VERSION 5.8 ;
BUSBITCHARS "[]" ;
DIVIDERCHAR "/" ;
UNITS
    DATABASE MICRONS 1000 ;
END UNITS

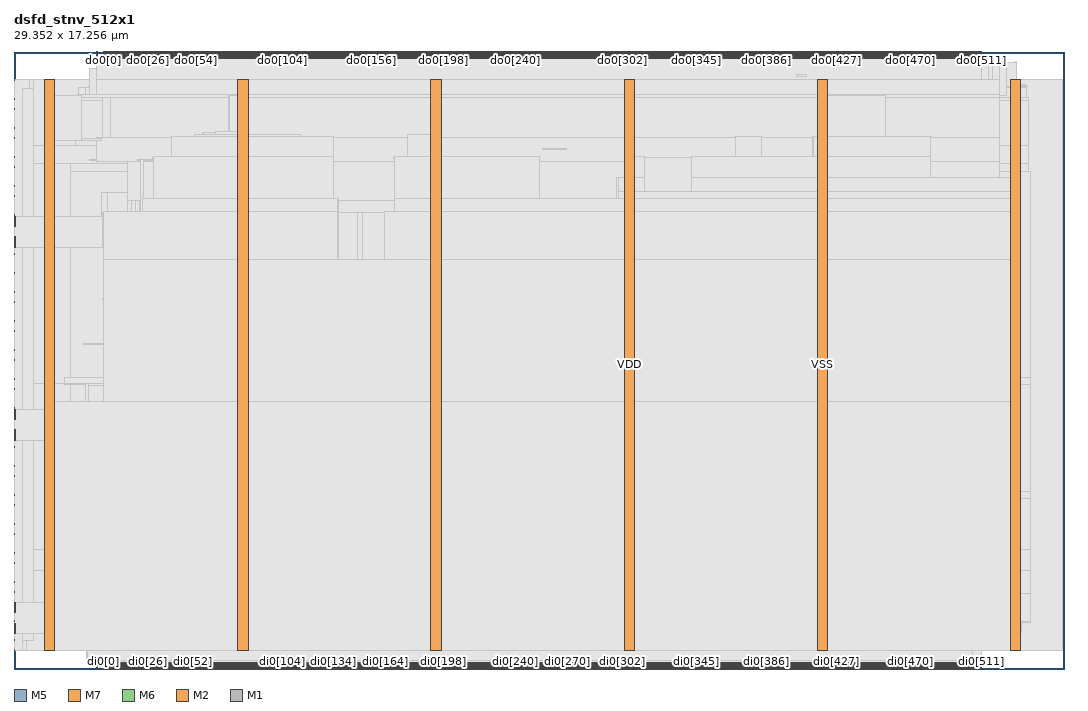
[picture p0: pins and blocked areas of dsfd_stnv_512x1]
MACRO dsfd_stnv_512x1
  FOREIGN dsfd_stnv_512x1 0 0 ;
  CLASS BLOCK ;
  SIZE 29.352 BY 17.256 ;
  PIN di0[0]
    DIRECTION INPUT ;
    USE SIGNAL ;
    PORT
      LAYER M5 ;
        RECT  2.496 0 2.52 0.192 ;
    END
  END di0[0]
  PIN di0[100]
    DIRECTION INPUT ;
    USE SIGNAL ;
    PORT
      LAYER M5 ;
        RECT  7.296 0 7.32 0.192 ;
    END
  END di0[100]
  PIN di0[101]
    DIRECTION INPUT ;
    USE SIGNAL ;
    PORT
      LAYER M5 ;
        RECT  7.344 0 7.368 0.192 ;
    END
  END di0[101]
  PIN di0[102]
    DIRECTION INPUT ;
    USE SIGNAL ;
    PORT
      LAYER M5 ;
        RECT  7.392 0 7.416 0.192 ;
    END
  END di0[102]
  PIN di0[103]
    DIRECTION INPUT ;
    USE SIGNAL ;
    PORT
      LAYER M5 ;
        RECT  7.44 0 7.464 0.192 ;
    END
  END di0[103]
  PIN di0[104]
    DIRECTION INPUT ;
    USE SIGNAL ;
    PORT
      LAYER M5 ;
        RECT  7.488 0 7.512 0.192 ;
    END
  END di0[104]
  PIN di0[105]
    DIRECTION INPUT ;
    USE SIGNAL ;
    PORT
      LAYER M5 ;
        RECT  7.536 0 7.56 0.192 ;
    END
  END di0[105]
  PIN di0[106]
    DIRECTION INPUT ;
    USE SIGNAL ;
    PORT
      LAYER M5 ;
        RECT  7.584 0 7.608 0.192 ;
    END
  END di0[106]
  PIN di0[107]
    DIRECTION INPUT ;
    USE SIGNAL ;
    PORT
      LAYER M5 ;
        RECT  7.632 0 7.656 0.192 ;
    END
  END di0[107]
  PIN di0[108]
    DIRECTION INPUT ;
    USE SIGNAL ;
    PORT
      LAYER M5 ;
        RECT  7.68 0 7.704 0.192 ;
    END
  END di0[108]
  PIN di0[109]
    DIRECTION INPUT ;
    USE SIGNAL ;
    PORT
      LAYER M5 ;
        RECT  7.728 0 7.752 0.192 ;
    END
  END di0[109]
  PIN di0[10]
    DIRECTION INPUT ;
    USE SIGNAL ;
    PORT
      LAYER M5 ;
        RECT  2.976 0 3 0.192 ;
    END
  END di0[10]
  PIN di0[110]
    DIRECTION INPUT ;
    USE SIGNAL ;
    PORT
      LAYER M5 ;
        RECT  7.776 0 7.8 0.192 ;
    END
  END di0[110]
  PIN di0[111]
    DIRECTION INPUT ;
    USE SIGNAL ;
    PORT
      LAYER M5 ;
        RECT  7.824 0 7.848 0.192 ;
    END
  END di0[111]
  PIN di0[112]
    DIRECTION INPUT ;
    USE SIGNAL ;
    PORT
      LAYER M5 ;
        RECT  7.872 0 7.896 0.192 ;
    END
  END di0[112]
  PIN di0[113]
    DIRECTION INPUT ;
    USE SIGNAL ;
    PORT
      LAYER M5 ;
        RECT  7.92 0 7.944 0.192 ;
    END
  END di0[113]
  PIN di0[114]
    DIRECTION INPUT ;
    USE SIGNAL ;
    PORT
      LAYER M5 ;
        RECT  7.968 0 7.992 0.192 ;
    END
  END di0[114]
  PIN di0[115]
    DIRECTION INPUT ;
    USE SIGNAL ;
    PORT
      LAYER M5 ;
        RECT  8.016 0 8.04 0.192 ;
    END
  END di0[115]
  PIN di0[116]
    DIRECTION INPUT ;
    USE SIGNAL ;
    PORT
      LAYER M5 ;
        RECT  8.064 0 8.088 0.192 ;
    END
  END di0[116]
  PIN di0[117]
    DIRECTION INPUT ;
    USE SIGNAL ;
    PORT
      LAYER M5 ;
        RECT  8.112 0 8.136 0.192 ;
    END
  END di0[117]
  PIN di0[118]
    DIRECTION INPUT ;
    USE SIGNAL ;
    PORT
      LAYER M5 ;
        RECT  8.16 0 8.184 0.192 ;
    END
  END di0[118]
  PIN di0[119]
    DIRECTION INPUT ;
    USE SIGNAL ;
    PORT
      LAYER M5 ;
        RECT  8.208 0 8.232 0.192 ;
    END
  END di0[119]
  PIN di0[11]
    DIRECTION INPUT ;
    USE SIGNAL ;
    PORT
      LAYER M5 ;
        RECT  3.024 0 3.048 0.192 ;
    END
  END di0[11]
  PIN di0[120]
    DIRECTION INPUT ;
    USE SIGNAL ;
    PORT
      LAYER M5 ;
        RECT  8.256 0 8.28 0.192 ;
    END
  END di0[120]
  PIN di0[121]
    DIRECTION INPUT ;
    USE SIGNAL ;
    PORT
      LAYER M5 ;
        RECT  8.304 0 8.328 0.192 ;
    END
  END di0[121]
  PIN di0[122]
    DIRECTION INPUT ;
    USE SIGNAL ;
    PORT
      LAYER M5 ;
        RECT  8.352 0 8.376 0.192 ;
    END
  END di0[122]
  PIN di0[123]
    DIRECTION INPUT ;
    USE SIGNAL ;
    PORT
      LAYER M5 ;
        RECT  8.4 0 8.424 0.192 ;
    END
  END di0[123]
  PIN di0[124]
    DIRECTION INPUT ;
    USE SIGNAL ;
    PORT
      LAYER M5 ;
        RECT  8.448 0 8.472 0.192 ;
    END
  END di0[124]
  PIN di0[125]
    DIRECTION INPUT ;
    USE SIGNAL ;
    PORT
      LAYER M5 ;
        RECT  8.496 0 8.52 0.192 ;
    END
  END di0[125]
  PIN di0[126]
    DIRECTION INPUT ;
    USE SIGNAL ;
    PORT
      LAYER M5 ;
        RECT  8.544 0 8.568 0.192 ;
    END
  END di0[126]
  PIN di0[127]
    DIRECTION INPUT ;
    USE SIGNAL ;
    PORT
      LAYER M5 ;
        RECT  8.592 0 8.616 0.192 ;
    END
  END di0[127]
  PIN di0[128]
    DIRECTION INPUT ;
    USE SIGNAL ;
    PORT
      LAYER M5 ;
        RECT  8.64 0 8.664 0.192 ;
    END
  END di0[128]
  PIN di0[129]
    DIRECTION INPUT ;
    USE SIGNAL ;
    PORT
      LAYER M5 ;
        RECT  8.688 0 8.712 0.192 ;
    END
  END di0[129]
  PIN di0[12]
    DIRECTION INPUT ;
    USE SIGNAL ;
    PORT
      LAYER M5 ;
        RECT  3.072 0 3.096 0.192 ;
    END
  END di0[12]
  PIN di0[130]
    DIRECTION INPUT ;
    USE SIGNAL ;
    PORT
      LAYER M5 ;
        RECT  8.736 0 8.76 0.192 ;
    END
  END di0[130]
  PIN di0[131]
    DIRECTION INPUT ;
    USE SIGNAL ;
    PORT
      LAYER M5 ;
        RECT  8.784 0 8.808 0.192 ;
    END
  END di0[131]
  PIN di0[132]
    DIRECTION INPUT ;
    USE SIGNAL ;
    PORT
      LAYER M5 ;
        RECT  8.832 0 8.856 0.192 ;
    END
  END di0[132]
  PIN di0[133]
    DIRECTION INPUT ;
    USE SIGNAL ;
    PORT
      LAYER M5 ;
        RECT  8.88 0 8.904 0.192 ;
    END
  END di0[133]
  PIN di0[134]
    DIRECTION INPUT ;
    USE SIGNAL ;
    PORT
      LAYER M5 ;
        RECT  8.928 0 8.952 0.192 ;
    END
  END di0[134]
  PIN di0[135]
    DIRECTION INPUT ;
    USE SIGNAL ;
    PORT
      LAYER M5 ;
        RECT  8.976 0 9 0.192 ;
    END
  END di0[135]
  PIN di0[136]
    DIRECTION INPUT ;
    USE SIGNAL ;
    PORT
      LAYER M5 ;
        RECT  9.024 0 9.048 0.192 ;
    END
  END di0[136]
  PIN di0[137]
    DIRECTION INPUT ;
    USE SIGNAL ;
    PORT
      LAYER M5 ;
        RECT  9.072 0 9.096 0.192 ;
    END
  END di0[137]
  PIN di0[138]
    DIRECTION INPUT ;
    USE SIGNAL ;
    PORT
      LAYER M5 ;
        RECT  9.12 0 9.144 0.192 ;
    END
  END di0[138]
  PIN di0[139]
    DIRECTION INPUT ;
    USE SIGNAL ;
    PORT
      LAYER M5 ;
        RECT  9.168 0 9.192 0.192 ;
    END
  END di0[139]
  PIN di0[13]
    DIRECTION INPUT ;
    USE SIGNAL ;
    PORT
      LAYER M5 ;
        RECT  3.12 0 3.144 0.192 ;
    END
  END di0[13]
  PIN di0[140]
    DIRECTION INPUT ;
    USE SIGNAL ;
    PORT
      LAYER M5 ;
        RECT  9.216 0 9.24 0.192 ;
    END
  END di0[140]
  PIN di0[141]
    DIRECTION INPUT ;
    USE SIGNAL ;
    PORT
      LAYER M5 ;
        RECT  9.264 0 9.288 0.192 ;
    END
  END di0[141]
  PIN di0[142]
    DIRECTION INPUT ;
    USE SIGNAL ;
    PORT
      LAYER M5 ;
        RECT  9.312 0 9.336 0.192 ;
    END
  END di0[142]
  PIN di0[143]
    DIRECTION INPUT ;
    USE SIGNAL ;
    PORT
      LAYER M5 ;
        RECT  9.36 0 9.384 0.192 ;
    END
  END di0[143]
  PIN di0[144]
    DIRECTION INPUT ;
    USE SIGNAL ;
    PORT
      LAYER M5 ;
        RECT  9.408 0 9.432 0.192 ;
    END
  END di0[144]
  PIN di0[145]
    DIRECTION INPUT ;
    USE SIGNAL ;
    PORT
      LAYER M5 ;
        RECT  9.456 0 9.48 0.192 ;
    END
  END di0[145]
  PIN di0[146]
    DIRECTION INPUT ;
    USE SIGNAL ;
    PORT
      LAYER M5 ;
        RECT  9.504 0 9.528 0.192 ;
    END
  END di0[146]
  PIN di0[147]
    DIRECTION INPUT ;
    USE SIGNAL ;
    PORT
      LAYER M5 ;
        RECT  9.552 0 9.576 0.192 ;
    END
  END di0[147]
  PIN di0[148]
    DIRECTION INPUT ;
    USE SIGNAL ;
    PORT
      LAYER M5 ;
        RECT  9.6 0 9.624 0.192 ;
    END
  END di0[148]
  PIN di0[149]
    DIRECTION INPUT ;
    USE SIGNAL ;
    PORT
      LAYER M5 ;
        RECT  9.648 0 9.672 0.192 ;
    END
  END di0[149]
  PIN di0[14]
    DIRECTION INPUT ;
    USE SIGNAL ;
    PORT
      LAYER M5 ;
        RECT  3.168 0 3.192 0.192 ;
    END
  END di0[14]
  PIN di0[150]
    DIRECTION INPUT ;
    USE SIGNAL ;
    PORT
      LAYER M5 ;
        RECT  9.696 0 9.72 0.192 ;
    END
  END di0[150]
  PIN di0[151]
    DIRECTION INPUT ;
    USE SIGNAL ;
    PORT
      LAYER M5 ;
        RECT  9.744 0 9.768 0.192 ;
    END
  END di0[151]
  PIN di0[152]
    DIRECTION INPUT ;
    USE SIGNAL ;
    PORT
      LAYER M5 ;
        RECT  9.792 0 9.816 0.192 ;
    END
  END di0[152]
  PIN di0[153]
    DIRECTION INPUT ;
    USE SIGNAL ;
    PORT
      LAYER M5 ;
        RECT  9.84 0 9.864 0.192 ;
    END
  END di0[153]
  PIN di0[154]
    DIRECTION INPUT ;
    USE SIGNAL ;
    PORT
      LAYER M5 ;
        RECT  9.888 0 9.912 0.192 ;
    END
  END di0[154]
  PIN di0[155]
    DIRECTION INPUT ;
    USE SIGNAL ;
    PORT
      LAYER M5 ;
        RECT  9.936 0 9.96 0.192 ;
    END
  END di0[155]
  PIN di0[156]
    DIRECTION INPUT ;
    USE SIGNAL ;
    PORT
      LAYER M5 ;
        RECT  9.984 0 10.008 0.192 ;
    END
  END di0[156]
  PIN di0[157]
    DIRECTION INPUT ;
    USE SIGNAL ;
    PORT
      LAYER M5 ;
        RECT  10.032 0 10.056 0.192 ;
    END
  END di0[157]
  PIN di0[158]
    DIRECTION INPUT ;
    USE SIGNAL ;
    PORT
      LAYER M5 ;
        RECT  10.08 0 10.104 0.192 ;
    END
  END di0[158]
  PIN di0[159]
    DIRECTION INPUT ;
    USE SIGNAL ;
    PORT
      LAYER M5 ;
        RECT  10.128 0 10.152 0.192 ;
    END
  END di0[159]
  PIN di0[15]
    DIRECTION INPUT ;
    USE SIGNAL ;
    PORT
      LAYER M5 ;
        RECT  3.216 0 3.24 0.192 ;
    END
  END di0[15]
  PIN di0[160]
    DIRECTION INPUT ;
    USE SIGNAL ;
    PORT
      LAYER M5 ;
        RECT  10.176 0 10.2 0.192 ;
    END
  END di0[160]
  PIN di0[161]
    DIRECTION INPUT ;
    USE SIGNAL ;
    PORT
      LAYER M5 ;
        RECT  10.224 0 10.248 0.192 ;
    END
  END di0[161]
  PIN di0[162]
    DIRECTION INPUT ;
    USE SIGNAL ;
    PORT
      LAYER M5 ;
        RECT  10.272 0 10.296 0.192 ;
    END
  END di0[162]
  PIN di0[163]
    DIRECTION INPUT ;
    USE SIGNAL ;
    PORT
      LAYER M5 ;
        RECT  10.32 0 10.344 0.192 ;
    END
  END di0[163]
  PIN di0[164]
    DIRECTION INPUT ;
    USE SIGNAL ;
    PORT
      LAYER M5 ;
        RECT  10.368 0 10.392 0.192 ;
    END
  END di0[164]
  PIN di0[165]
    DIRECTION INPUT ;
    USE SIGNAL ;
    PORT
      LAYER M5 ;
        RECT  10.416 0 10.44 0.192 ;
    END
  END di0[165]
  PIN di0[166]
    DIRECTION INPUT ;
    USE SIGNAL ;
    PORT
      LAYER M5 ;
        RECT  10.464 0 10.488 0.192 ;
    END
  END di0[166]
  PIN di0[167]
    DIRECTION INPUT ;
    USE SIGNAL ;
    PORT
      LAYER M5 ;
        RECT  10.512 0 10.536 0.192 ;
    END
  END di0[167]
  PIN di0[168]
    DIRECTION INPUT ;
    USE SIGNAL ;
    PORT
      LAYER M5 ;
        RECT  10.56 0 10.584 0.192 ;
    END
  END di0[168]
  PIN di0[169]
    DIRECTION INPUT ;
    USE SIGNAL ;
    PORT
      LAYER M5 ;
        RECT  10.608 0 10.632 0.192 ;
    END
  END di0[169]
  PIN di0[16]
    DIRECTION INPUT ;
    USE SIGNAL ;
    PORT
      LAYER M5 ;
        RECT  3.264 0 3.288 0.192 ;
    END
  END di0[16]
  PIN di0[170]
    DIRECTION INPUT ;
    USE SIGNAL ;
    PORT
      LAYER M5 ;
        RECT  10.656 0 10.68 0.192 ;
    END
  END di0[170]
  PIN di0[171]
    DIRECTION INPUT ;
    USE SIGNAL ;
    PORT
      LAYER M5 ;
        RECT  10.704 0 10.728 0.192 ;
    END
  END di0[171]
  PIN di0[172]
    DIRECTION INPUT ;
    USE SIGNAL ;
    PORT
      LAYER M5 ;
        RECT  10.752 0 10.776 0.192 ;
    END
  END di0[172]
  PIN di0[173]
    DIRECTION INPUT ;
    USE SIGNAL ;
    PORT
      LAYER M5 ;
        RECT  10.8 0 10.824 0.192 ;
    END
  END di0[173]
  PIN di0[174]
    DIRECTION INPUT ;
    USE SIGNAL ;
    PORT
      LAYER M5 ;
        RECT  10.848 0 10.872 0.192 ;
    END
  END di0[174]
  PIN di0[175]
    DIRECTION INPUT ;
    USE SIGNAL ;
    PORT
      LAYER M5 ;
        RECT  10.896 0 10.92 0.192 ;
    END
  END di0[175]
  PIN di0[176]
    DIRECTION INPUT ;
    USE SIGNAL ;
    PORT
      LAYER M5 ;
        RECT  10.944 0 10.968 0.192 ;
    END
  END di0[176]
  PIN di0[177]
    DIRECTION INPUT ;
    USE SIGNAL ;
    PORT
      LAYER M5 ;
        RECT  10.992 0 11.016 0.192 ;
    END
  END di0[177]
  PIN di0[178]
    DIRECTION INPUT ;
    USE SIGNAL ;
    PORT
      LAYER M5 ;
        RECT  11.04 0 11.064 0.192 ;
    END
  END di0[178]
  PIN di0[179]
    DIRECTION INPUT ;
    USE SIGNAL ;
    PORT
      LAYER M5 ;
        RECT  11.088 0 11.112 0.192 ;
    END
  END di0[179]
  PIN di0[17]
    DIRECTION INPUT ;
    USE SIGNAL ;
    PORT
      LAYER M5 ;
        RECT  3.312 0 3.336 0.192 ;
    END
  END di0[17]
  PIN di0[180]
    DIRECTION INPUT ;
    USE SIGNAL ;
    PORT
      LAYER M5 ;
        RECT  11.136 0 11.16 0.192 ;
    END
  END di0[180]
  PIN di0[181]
    DIRECTION INPUT ;
    USE SIGNAL ;
    PORT
      LAYER M5 ;
        RECT  11.184 0 11.208 0.192 ;
    END
  END di0[181]
  PIN di0[182]
    DIRECTION INPUT ;
    USE SIGNAL ;
    PORT
      LAYER M5 ;
        RECT  11.232 0 11.256 0.192 ;
    END
  END di0[182]
  PIN di0[183]
    DIRECTION INPUT ;
    USE SIGNAL ;
    PORT
      LAYER M5 ;
        RECT  11.28 0 11.304 0.192 ;
    END
  END di0[183]
  PIN di0[184]
    DIRECTION INPUT ;
    USE SIGNAL ;
    PORT
      LAYER M5 ;
        RECT  11.328 0 11.352 0.192 ;
    END
  END di0[184]
  PIN di0[185]
    DIRECTION INPUT ;
    USE SIGNAL ;
    PORT
      LAYER M5 ;
        RECT  11.376 0 11.4 0.192 ;
    END
  END di0[185]
  PIN di0[186]
    DIRECTION INPUT ;
    USE SIGNAL ;
    PORT
      LAYER M5 ;
        RECT  11.424 0 11.448 0.192 ;
    END
  END di0[186]
  PIN di0[187]
    DIRECTION INPUT ;
    USE SIGNAL ;
    PORT
      LAYER M5 ;
        RECT  11.472 0 11.496 0.192 ;
    END
  END di0[187]
  PIN di0[188]
    DIRECTION INPUT ;
    USE SIGNAL ;
    PORT
      LAYER M5 ;
        RECT  11.52 0 11.544 0.192 ;
    END
  END di0[188]
  PIN di0[189]
    DIRECTION INPUT ;
    USE SIGNAL ;
    PORT
      LAYER M5 ;
        RECT  11.568 0 11.592 0.192 ;
    END
  END di0[189]
  PIN di0[18]
    DIRECTION INPUT ;
    USE SIGNAL ;
    PORT
      LAYER M5 ;
        RECT  3.36 0 3.384 0.192 ;
    END
  END di0[18]
  PIN di0[190]
    DIRECTION INPUT ;
    USE SIGNAL ;
    PORT
      LAYER M5 ;
        RECT  11.616 0 11.64 0.192 ;
    END
  END di0[190]
  PIN di0[191]
    DIRECTION INPUT ;
    USE SIGNAL ;
    PORT
      LAYER M5 ;
        RECT  11.664 0 11.688 0.192 ;
    END
  END di0[191]
  PIN di0[192]
    DIRECTION INPUT ;
    USE SIGNAL ;
    PORT
      LAYER M5 ;
        RECT  11.712 0 11.736 0.192 ;
    END
  END di0[192]
  PIN di0[193]
    DIRECTION INPUT ;
    USE SIGNAL ;
    PORT
      LAYER M5 ;
        RECT  11.76 0 11.784 0.192 ;
    END
  END di0[193]
  PIN di0[194]
    DIRECTION INPUT ;
    USE SIGNAL ;
    PORT
      LAYER M5 ;
        RECT  11.808 0 11.832 0.192 ;
    END
  END di0[194]
  PIN di0[195]
    DIRECTION INPUT ;
    USE SIGNAL ;
    PORT
      LAYER M5 ;
        RECT  11.856 0 11.88 0.192 ;
    END
  END di0[195]
  PIN di0[196]
    DIRECTION INPUT ;
    USE SIGNAL ;
    PORT
      LAYER M5 ;
        RECT  11.904 0 11.928 0.192 ;
    END
  END di0[196]
  PIN di0[197]
    DIRECTION INPUT ;
    USE SIGNAL ;
    PORT
      LAYER M5 ;
        RECT  11.952 0 11.976 0.192 ;
    END
  END di0[197]
  PIN di0[198]
    DIRECTION INPUT ;
    USE SIGNAL ;
    PORT
      LAYER M5 ;
        RECT  12 0 12.024 0.192 ;
    END
  END di0[198]
  PIN di0[199]
    DIRECTION INPUT ;
    USE SIGNAL ;
    PORT
      LAYER M5 ;
        RECT  12.048 0 12.072 0.192 ;
    END
  END di0[199]
  PIN di0[19]
    DIRECTION INPUT ;
    USE SIGNAL ;
    PORT
      LAYER M5 ;
        RECT  3.408 0 3.432 0.192 ;
    END
  END di0[19]
  PIN di0[1]
    DIRECTION INPUT ;
    USE SIGNAL ;
    PORT
      LAYER M5 ;
        RECT  2.544 0 2.568 0.192 ;
    END
  END di0[1]
  PIN di0[200]
    DIRECTION INPUT ;
    USE SIGNAL ;
    PORT
      LAYER M5 ;
        RECT  12.096 0 12.12 0.192 ;
    END
  END di0[200]
  PIN di0[201]
    DIRECTION INPUT ;
    USE SIGNAL ;
    PORT
      LAYER M5 ;
        RECT  12.144 0 12.168 0.192 ;
    END
  END di0[201]
  PIN di0[202]
    DIRECTION INPUT ;
    USE SIGNAL ;
    PORT
      LAYER M5 ;
        RECT  12.192 0 12.216 0.192 ;
    END
  END di0[202]
  PIN di0[203]
    DIRECTION INPUT ;
    USE SIGNAL ;
    PORT
      LAYER M5 ;
        RECT  12.24 0 12.264 0.192 ;
    END
  END di0[203]
  PIN di0[204]
    DIRECTION INPUT ;
    USE SIGNAL ;
    PORT
      LAYER M5 ;
        RECT  12.288 0 12.312 0.192 ;
    END
  END di0[204]
  PIN di0[205]
    DIRECTION INPUT ;
    USE SIGNAL ;
    PORT
      LAYER M5 ;
        RECT  12.336 0 12.36 0.192 ;
    END
  END di0[205]
  PIN di0[206]
    DIRECTION INPUT ;
    USE SIGNAL ;
    PORT
      LAYER M5 ;
        RECT  12.384 0 12.408 0.192 ;
    END
  END di0[206]
  PIN di0[207]
    DIRECTION INPUT ;
    USE SIGNAL ;
    PORT
      LAYER M5 ;
        RECT  12.432 0 12.456 0.192 ;
    END
  END di0[207]
  PIN di0[208]
    DIRECTION INPUT ;
    USE SIGNAL ;
    PORT
      LAYER M5 ;
        RECT  12.48 0 12.504 0.192 ;
    END
  END di0[208]
  PIN di0[209]
    DIRECTION INPUT ;
    USE SIGNAL ;
    PORT
      LAYER M5 ;
        RECT  12.528 0 12.552 0.192 ;
    END
  END di0[209]
  PIN di0[20]
    DIRECTION INPUT ;
    USE SIGNAL ;
    PORT
      LAYER M5 ;
        RECT  3.456 0 3.48 0.192 ;
    END
  END di0[20]
  PIN di0[210]
    DIRECTION INPUT ;
    USE SIGNAL ;
    PORT
      LAYER M5 ;
        RECT  12.576 0 12.6 0.192 ;
    END
  END di0[210]
  PIN di0[211]
    DIRECTION INPUT ;
    USE SIGNAL ;
    PORT
      LAYER M5 ;
        RECT  12.624 0 12.648 0.192 ;
    END
  END di0[211]
  PIN di0[212]
    DIRECTION INPUT ;
    USE SIGNAL ;
    PORT
      LAYER M5 ;
        RECT  12.672 0 12.696 0.192 ;
    END
  END di0[212]
  PIN di0[213]
    DIRECTION INPUT ;
    USE SIGNAL ;
    PORT
      LAYER M5 ;
        RECT  12.72 0 12.744 0.192 ;
    END
  END di0[213]
  PIN di0[214]
    DIRECTION INPUT ;
    USE SIGNAL ;
    PORT
      LAYER M5 ;
        RECT  12.768 0 12.792 0.192 ;
    END
  END di0[214]
  PIN di0[215]
    DIRECTION INPUT ;
    USE SIGNAL ;
    PORT
      LAYER M5 ;
        RECT  12.816 0 12.84 0.192 ;
    END
  END di0[215]
  PIN di0[216]
    DIRECTION INPUT ;
    USE SIGNAL ;
    PORT
      LAYER M5 ;
        RECT  12.864 0 12.888 0.192 ;
    END
  END di0[216]
  PIN di0[217]
    DIRECTION INPUT ;
    USE SIGNAL ;
    PORT
      LAYER M5 ;
        RECT  12.912 0 12.936 0.192 ;
    END
  END di0[217]
  PIN di0[218]
    DIRECTION INPUT ;
    USE SIGNAL ;
    PORT
      LAYER M5 ;
        RECT  12.96 0 12.984 0.192 ;
    END
  END di0[218]
  PIN di0[219]
    DIRECTION INPUT ;
    USE SIGNAL ;
    PORT
      LAYER M5 ;
        RECT  13.008 0 13.032 0.192 ;
    END
  END di0[219]
  PIN di0[21]
    DIRECTION INPUT ;
    USE SIGNAL ;
    PORT
      LAYER M5 ;
        RECT  3.504 0 3.528 0.192 ;
    END
  END di0[21]
  PIN di0[220]
    DIRECTION INPUT ;
    USE SIGNAL ;
    PORT
      LAYER M5 ;
        RECT  13.056 0 13.08 0.192 ;
    END
  END di0[220]
  PIN di0[221]
    DIRECTION INPUT ;
    USE SIGNAL ;
    PORT
      LAYER M5 ;
        RECT  13.104 0 13.128 0.192 ;
    END
  END di0[221]
  PIN di0[222]
    DIRECTION INPUT ;
    USE SIGNAL ;
    PORT
      LAYER M5 ;
        RECT  13.152 0 13.176 0.192 ;
    END
  END di0[222]
  PIN di0[223]
    DIRECTION INPUT ;
    USE SIGNAL ;
    PORT
      LAYER M5 ;
        RECT  13.2 0 13.224 0.192 ;
    END
  END di0[223]
  PIN di0[224]
    DIRECTION INPUT ;
    USE SIGNAL ;
    PORT
      LAYER M5 ;
        RECT  13.248 0 13.272 0.192 ;
    END
  END di0[224]
  PIN di0[225]
    DIRECTION INPUT ;
    USE SIGNAL ;
    PORT
      LAYER M5 ;
        RECT  13.296 0 13.32 0.192 ;
    END
  END di0[225]
  PIN di0[226]
    DIRECTION INPUT ;
    USE SIGNAL ;
    PORT
      LAYER M5 ;
        RECT  13.344 0 13.368 0.192 ;
    END
  END di0[226]
  PIN di0[227]
    DIRECTION INPUT ;
    USE SIGNAL ;
    PORT
      LAYER M5 ;
        RECT  13.392 0 13.416 0.192 ;
    END
  END di0[227]
  PIN di0[228]
    DIRECTION INPUT ;
    USE SIGNAL ;
    PORT
      LAYER M5 ;
        RECT  13.44 0 13.464 0.192 ;
    END
  END di0[228]
  PIN di0[229]
    DIRECTION INPUT ;
    USE SIGNAL ;
    PORT
      LAYER M5 ;
        RECT  13.488 0 13.512 0.192 ;
    END
  END di0[229]
  PIN di0[22]
    DIRECTION INPUT ;
    USE SIGNAL ;
    PORT
      LAYER M5 ;
        RECT  3.552 0 3.576 0.192 ;
    END
  END di0[22]
  PIN di0[230]
    DIRECTION INPUT ;
    USE SIGNAL ;
    PORT
      LAYER M5 ;
        RECT  13.536 0 13.56 0.192 ;
    END
  END di0[230]
  PIN di0[231]
    DIRECTION INPUT ;
    USE SIGNAL ;
    PORT
      LAYER M5 ;
        RECT  13.584 0 13.608 0.192 ;
    END
  END di0[231]
  PIN di0[232]
    DIRECTION INPUT ;
    USE SIGNAL ;
    PORT
      LAYER M5 ;
        RECT  13.632 0 13.656 0.192 ;
    END
  END di0[232]
  PIN di0[233]
    DIRECTION INPUT ;
    USE SIGNAL ;
    PORT
      LAYER M5 ;
        RECT  13.68 0 13.704 0.192 ;
    END
  END di0[233]
  PIN di0[234]
    DIRECTION INPUT ;
    USE SIGNAL ;
    PORT
      LAYER M5 ;
        RECT  13.728 0 13.752 0.192 ;
    END
  END di0[234]
  PIN di0[235]
    DIRECTION INPUT ;
    USE SIGNAL ;
    PORT
      LAYER M5 ;
        RECT  13.776 0 13.8 0.192 ;
    END
  END di0[235]
  PIN di0[236]
    DIRECTION INPUT ;
    USE SIGNAL ;
    PORT
      LAYER M5 ;
        RECT  13.824 0 13.848 0.192 ;
    END
  END di0[236]
  PIN di0[237]
    DIRECTION INPUT ;
    USE SIGNAL ;
    PORT
      LAYER M5 ;
        RECT  13.872 0 13.896 0.192 ;
    END
  END di0[237]
  PIN di0[238]
    DIRECTION INPUT ;
    USE SIGNAL ;
    PORT
      LAYER M5 ;
        RECT  13.92 0 13.944 0.192 ;
    END
  END di0[238]
  PIN di0[239]
    DIRECTION INPUT ;
    USE SIGNAL ;
    PORT
      LAYER M5 ;
        RECT  13.968 0 13.992 0.192 ;
    END
  END di0[239]
  PIN di0[23]
    DIRECTION INPUT ;
    USE SIGNAL ;
    PORT
      LAYER M5 ;
        RECT  3.6 0 3.624 0.192 ;
    END
  END di0[23]
  PIN di0[240]
    DIRECTION INPUT ;
    USE SIGNAL ;
    PORT
      LAYER M5 ;
        RECT  14.016 0 14.04 0.192 ;
    END
  END di0[240]
  PIN di0[241]
    DIRECTION INPUT ;
    USE SIGNAL ;
    PORT
      LAYER M5 ;
        RECT  14.064 0 14.088 0.192 ;
    END
  END di0[241]
  PIN di0[242]
    DIRECTION INPUT ;
    USE SIGNAL ;
    PORT
      LAYER M5 ;
        RECT  14.112 0 14.136 0.192 ;
    END
  END di0[242]
  PIN di0[243]
    DIRECTION INPUT ;
    USE SIGNAL ;
    PORT
      LAYER M5 ;
        RECT  14.16 0 14.184 0.192 ;
    END
  END di0[243]
  PIN di0[244]
    DIRECTION INPUT ;
    USE SIGNAL ;
    PORT
      LAYER M5 ;
        RECT  14.208 0 14.232 0.192 ;
    END
  END di0[244]
  PIN di0[245]
    DIRECTION INPUT ;
    USE SIGNAL ;
    PORT
      LAYER M5 ;
        RECT  14.256 0 14.28 0.192 ;
    END
  END di0[245]
  PIN di0[246]
    DIRECTION INPUT ;
    USE SIGNAL ;
    PORT
      LAYER M5 ;
        RECT  14.304 0 14.328 0.192 ;
    END
  END di0[246]
  PIN di0[247]
    DIRECTION INPUT ;
    USE SIGNAL ;
    PORT
      LAYER M5 ;
        RECT  14.352 0 14.376 0.192 ;
    END
  END di0[247]
  PIN di0[248]
    DIRECTION INPUT ;
    USE SIGNAL ;
    PORT
      LAYER M5 ;
        RECT  14.4 0 14.424 0.192 ;
    END
  END di0[248]
  PIN di0[249]
    DIRECTION INPUT ;
    USE SIGNAL ;
    PORT
      LAYER M5 ;
        RECT  14.448 0 14.472 0.192 ;
    END
  END di0[249]
  PIN di0[24]
    DIRECTION INPUT ;
    USE SIGNAL ;
    PORT
      LAYER M5 ;
        RECT  3.648 0 3.672 0.192 ;
    END
  END di0[24]
  PIN di0[250]
    DIRECTION INPUT ;
    USE SIGNAL ;
    PORT
      LAYER M5 ;
        RECT  14.496 0 14.52 0.192 ;
    END
  END di0[250]
  PIN di0[251]
    DIRECTION INPUT ;
    USE SIGNAL ;
    PORT
      LAYER M5 ;
        RECT  14.544 0 14.568 0.192 ;
    END
  END di0[251]
  PIN di0[252]
    DIRECTION INPUT ;
    USE SIGNAL ;
    PORT
      LAYER M5 ;
        RECT  14.592 0 14.616 0.192 ;
    END
  END di0[252]
  PIN di0[253]
    DIRECTION INPUT ;
    USE SIGNAL ;
    PORT
      LAYER M5 ;
        RECT  14.64 0 14.664 0.192 ;
    END
  END di0[253]
  PIN di0[254]
    DIRECTION INPUT ;
    USE SIGNAL ;
    PORT
      LAYER M5 ;
        RECT  14.688 0 14.712 0.192 ;
    END
  END di0[254]
  PIN di0[255]
    DIRECTION INPUT ;
    USE SIGNAL ;
    PORT
      LAYER M5 ;
        RECT  14.736 0 14.76 0.192 ;
    END
  END di0[255]
  PIN di0[256]
    DIRECTION INPUT ;
    USE SIGNAL ;
    PORT
      LAYER M5 ;
        RECT  14.784 0 14.808 0.192 ;
    END
  END di0[256]
  PIN di0[257]
    DIRECTION INPUT ;
    USE SIGNAL ;
    PORT
      LAYER M5 ;
        RECT  14.832 0 14.856 0.192 ;
    END
  END di0[257]
  PIN di0[258]
    DIRECTION INPUT ;
    USE SIGNAL ;
    PORT
      LAYER M5 ;
        RECT  14.88 0 14.904 0.192 ;
    END
  END di0[258]
  PIN di0[259]
    DIRECTION INPUT ;
    USE SIGNAL ;
    PORT
      LAYER M5 ;
        RECT  14.928 0 14.952 0.192 ;
    END
  END di0[259]
  PIN di0[25]
    DIRECTION INPUT ;
    USE SIGNAL ;
    PORT
      LAYER M5 ;
        RECT  3.696 0 3.72 0.192 ;
    END
  END di0[25]
  PIN di0[260]
    DIRECTION INPUT ;
    USE SIGNAL ;
    PORT
      LAYER M5 ;
        RECT  14.976 0 15 0.192 ;
    END
  END di0[260]
  PIN di0[261]
    DIRECTION INPUT ;
    USE SIGNAL ;
    PORT
      LAYER M5 ;
        RECT  15.024 0 15.048 0.192 ;
    END
  END di0[261]
  PIN di0[262]
    DIRECTION INPUT ;
    USE SIGNAL ;
    PORT
      LAYER M5 ;
        RECT  15.072 0 15.096 0.192 ;
    END
  END di0[262]
  PIN di0[263]
    DIRECTION INPUT ;
    USE SIGNAL ;
    PORT
      LAYER M5 ;
        RECT  15.12 0 15.144 0.192 ;
    END
  END di0[263]
  PIN di0[264]
    DIRECTION INPUT ;
    USE SIGNAL ;
    PORT
      LAYER M5 ;
        RECT  15.168 0 15.192 0.192 ;
    END
  END di0[264]
  PIN di0[265]
    DIRECTION INPUT ;
    USE SIGNAL ;
    PORT
      LAYER M5 ;
        RECT  15.216 0 15.24 0.192 ;
    END
  END di0[265]
  PIN di0[266]
    DIRECTION INPUT ;
    USE SIGNAL ;
    PORT
      LAYER M5 ;
        RECT  15.264 0 15.288 0.192 ;
    END
  END di0[266]
  PIN di0[267]
    DIRECTION INPUT ;
    USE SIGNAL ;
    PORT
      LAYER M5 ;
        RECT  15.312 0 15.336 0.192 ;
    END
  END di0[267]
  PIN di0[268]
    DIRECTION INPUT ;
    USE SIGNAL ;
    PORT
      LAYER M5 ;
        RECT  15.36 0 15.384 0.192 ;
    END
  END di0[268]
  PIN di0[269]
    DIRECTION INPUT ;
    USE SIGNAL ;
    PORT
      LAYER M5 ;
        RECT  15.408 0 15.432 0.192 ;
    END
  END di0[269]
  PIN di0[26]
    DIRECTION INPUT ;
    USE SIGNAL ;
    PORT
      LAYER M5 ;
        RECT  3.744 0 3.768 0.192 ;
    END
  END di0[26]
  PIN di0[270]
    DIRECTION INPUT ;
    USE SIGNAL ;
    PORT
      LAYER M5 ;
        RECT  15.456 0 15.48 0.192 ;
    END
  END di0[270]
  PIN di0[271]
    DIRECTION INPUT ;
    USE SIGNAL ;
    PORT
      LAYER M5 ;
        RECT  15.504 0 15.528 0.192 ;
    END
  END di0[271]
  PIN di0[272]
    DIRECTION INPUT ;
    USE SIGNAL ;
    PORT
      LAYER M5 ;
        RECT  15.552 0 15.576 0.192 ;
    END
  END di0[272]
  PIN di0[273]
    DIRECTION INPUT ;
    USE SIGNAL ;
    PORT
      LAYER M5 ;
        RECT  15.6 0 15.624 0.192 ;
    END
  END di0[273]
  PIN di0[274]
    DIRECTION INPUT ;
    USE SIGNAL ;
    PORT
      LAYER M5 ;
        RECT  15.648 0 15.672 0.192 ;
    END
  END di0[274]
  PIN di0[275]
    DIRECTION INPUT ;
    USE SIGNAL ;
    PORT
      LAYER M5 ;
        RECT  15.696 0 15.72 0.192 ;
    END
  END di0[275]
  PIN di0[276]
    DIRECTION INPUT ;
    USE SIGNAL ;
    PORT
      LAYER M5 ;
        RECT  15.744 0 15.768 0.192 ;
    END
  END di0[276]
  PIN di0[277]
    DIRECTION INPUT ;
    USE SIGNAL ;
    PORT
      LAYER M5 ;
        RECT  15.792 0 15.816 0.192 ;
    END
  END di0[277]
  PIN di0[278]
    DIRECTION INPUT ;
    USE SIGNAL ;
    PORT
      LAYER M5 ;
        RECT  15.84 0 15.864 0.192 ;
    END
  END di0[278]
  PIN di0[279]
    DIRECTION INPUT ;
    USE SIGNAL ;
    PORT
      LAYER M5 ;
        RECT  15.888 0 15.912 0.192 ;
    END
  END di0[279]
  PIN di0[27]
    DIRECTION INPUT ;
    USE SIGNAL ;
    PORT
      LAYER M5 ;
        RECT  3.792 0 3.816 0.192 ;
    END
  END di0[27]
  PIN di0[280]
    DIRECTION INPUT ;
    USE SIGNAL ;
    PORT
      LAYER M5 ;
        RECT  15.936 0 15.96 0.192 ;
    END
  END di0[280]
  PIN di0[281]
    DIRECTION INPUT ;
    USE SIGNAL ;
    PORT
      LAYER M5 ;
        RECT  15.984 0 16.008 0.192 ;
    END
  END di0[281]
  PIN di0[282]
    DIRECTION INPUT ;
    USE SIGNAL ;
    PORT
      LAYER M5 ;
        RECT  16.032 0 16.056 0.192 ;
    END
  END di0[282]
  PIN di0[283]
    DIRECTION INPUT ;
    USE SIGNAL ;
    PORT
      LAYER M5 ;
        RECT  16.08 0 16.104 0.192 ;
    END
  END di0[283]
  PIN di0[284]
    DIRECTION INPUT ;
    USE SIGNAL ;
    PORT
      LAYER M5 ;
        RECT  16.128 0 16.152 0.192 ;
    END
  END di0[284]
  PIN di0[285]
    DIRECTION INPUT ;
    USE SIGNAL ;
    PORT
      LAYER M5 ;
        RECT  16.176 0 16.2 0.192 ;
    END
  END di0[285]
  PIN di0[286]
    DIRECTION INPUT ;
    USE SIGNAL ;
    PORT
      LAYER M5 ;
        RECT  16.224 0 16.248 0.192 ;
    END
  END di0[286]
  PIN di0[287]
    DIRECTION INPUT ;
    USE SIGNAL ;
    PORT
      LAYER M5 ;
        RECT  16.272 0 16.296 0.192 ;
    END
  END di0[287]
  PIN di0[288]
    DIRECTION INPUT ;
    USE SIGNAL ;
    PORT
      LAYER M5 ;
        RECT  16.32 0 16.344 0.192 ;
    END
  END di0[288]
  PIN di0[289]
    DIRECTION INPUT ;
    USE SIGNAL ;
    PORT
      LAYER M5 ;
        RECT  16.368 0 16.392 0.192 ;
    END
  END di0[289]
  PIN di0[28]
    DIRECTION INPUT ;
    USE SIGNAL ;
    PORT
      LAYER M5 ;
        RECT  3.84 0 3.864 0.192 ;
    END
  END di0[28]
  PIN di0[290]
    DIRECTION INPUT ;
    USE SIGNAL ;
    PORT
      LAYER M5 ;
        RECT  16.416 0 16.44 0.192 ;
    END
  END di0[290]
  PIN di0[291]
    DIRECTION INPUT ;
    USE SIGNAL ;
    PORT
      LAYER M5 ;
        RECT  16.464 0 16.488 0.192 ;
    END
  END di0[291]
  PIN di0[292]
    DIRECTION INPUT ;
    USE SIGNAL ;
    PORT
      LAYER M5 ;
        RECT  16.512 0 16.536 0.192 ;
    END
  END di0[292]
  PIN di0[293]
    DIRECTION INPUT ;
    USE SIGNAL ;
    PORT
      LAYER M5 ;
        RECT  16.56 0 16.584 0.192 ;
    END
  END di0[293]
  PIN di0[294]
    DIRECTION INPUT ;
    USE SIGNAL ;
    PORT
      LAYER M5 ;
        RECT  16.608 0 16.632 0.192 ;
    END
  END di0[294]
  PIN di0[295]
    DIRECTION INPUT ;
    USE SIGNAL ;
    PORT
      LAYER M5 ;
        RECT  16.656 0 16.68 0.192 ;
    END
  END di0[295]
  PIN di0[296]
    DIRECTION INPUT ;
    USE SIGNAL ;
    PORT
      LAYER M5 ;
        RECT  16.704 0 16.728 0.192 ;
    END
  END di0[296]
  PIN di0[297]
    DIRECTION INPUT ;
    USE SIGNAL ;
    PORT
      LAYER M5 ;
        RECT  16.752 0 16.776 0.192 ;
    END
  END di0[297]
  PIN di0[298]
    DIRECTION INPUT ;
    USE SIGNAL ;
    PORT
      LAYER M5 ;
        RECT  16.8 0 16.824 0.192 ;
    END
  END di0[298]
  PIN di0[299]
    DIRECTION INPUT ;
    USE SIGNAL ;
    PORT
      LAYER M5 ;
        RECT  16.848 0 16.872 0.192 ;
    END
  END di0[299]
  PIN di0[29]
    DIRECTION INPUT ;
    USE SIGNAL ;
    PORT
      LAYER M5 ;
        RECT  3.888 0 3.912 0.192 ;
    END
  END di0[29]
  PIN di0[2]
    DIRECTION INPUT ;
    USE SIGNAL ;
    PORT
      LAYER M5 ;
        RECT  2.592 0 2.616 0.192 ;
    END
  END di0[2]
  PIN di0[300]
    DIRECTION INPUT ;
    USE SIGNAL ;
    PORT
      LAYER M5 ;
        RECT  16.896 0 16.92 0.192 ;
    END
  END di0[300]
  PIN di0[301]
    DIRECTION INPUT ;
    USE SIGNAL ;
    PORT
      LAYER M5 ;
        RECT  16.944 0 16.968 0.192 ;
    END
  END di0[301]
  PIN di0[302]
    DIRECTION INPUT ;
    USE SIGNAL ;
    PORT
      LAYER M5 ;
        RECT  16.992 0 17.016 0.192 ;
    END
  END di0[302]
  PIN di0[303]
    DIRECTION INPUT ;
    USE SIGNAL ;
    PORT
      LAYER M5 ;
        RECT  17.04 0 17.064 0.192 ;
    END
  END di0[303]
  PIN di0[304]
    DIRECTION INPUT ;
    USE SIGNAL ;
    PORT
      LAYER M5 ;
        RECT  17.088 0 17.112 0.192 ;
    END
  END di0[304]
  PIN di0[305]
    DIRECTION INPUT ;
    USE SIGNAL ;
    PORT
      LAYER M5 ;
        RECT  17.136 0 17.16 0.192 ;
    END
  END di0[305]
  PIN di0[306]
    DIRECTION INPUT ;
    USE SIGNAL ;
    PORT
      LAYER M5 ;
        RECT  17.184 0 17.208 0.192 ;
    END
  END di0[306]
  PIN di0[307]
    DIRECTION INPUT ;
    USE SIGNAL ;
    PORT
      LAYER M5 ;
        RECT  17.232 0 17.256 0.192 ;
    END
  END di0[307]
  PIN di0[308]
    DIRECTION INPUT ;
    USE SIGNAL ;
    PORT
      LAYER M5 ;
        RECT  17.28 0 17.304 0.192 ;
    END
  END di0[308]
  PIN di0[309]
    DIRECTION INPUT ;
    USE SIGNAL ;
    PORT
      LAYER M5 ;
        RECT  17.328 0 17.352 0.192 ;
    END
  END di0[309]
  PIN di0[30]
    DIRECTION INPUT ;
    USE SIGNAL ;
    PORT
      LAYER M5 ;
        RECT  3.936 0 3.96 0.192 ;
    END
  END di0[30]
  PIN di0[310]
    DIRECTION INPUT ;
    USE SIGNAL ;
    PORT
      LAYER M5 ;
        RECT  17.376 0 17.4 0.192 ;
    END
  END di0[310]
  PIN di0[311]
    DIRECTION INPUT ;
    USE SIGNAL ;
    PORT
      LAYER M5 ;
        RECT  17.424 0 17.448 0.192 ;
    END
  END di0[311]
  PIN di0[312]
    DIRECTION INPUT ;
    USE SIGNAL ;
    PORT
      LAYER M5 ;
        RECT  17.472 0 17.496 0.192 ;
    END
  END di0[312]
  PIN di0[313]
    DIRECTION INPUT ;
    USE SIGNAL ;
    PORT
      LAYER M5 ;
        RECT  17.52 0 17.544 0.192 ;
    END
  END di0[313]
  PIN di0[314]
    DIRECTION INPUT ;
    USE SIGNAL ;
    PORT
      LAYER M5 ;
        RECT  17.568 0 17.592 0.192 ;
    END
  END di0[314]
  PIN di0[315]
    DIRECTION INPUT ;
    USE SIGNAL ;
    PORT
      LAYER M5 ;
        RECT  17.616 0 17.64 0.192 ;
    END
  END di0[315]
  PIN di0[316]
    DIRECTION INPUT ;
    USE SIGNAL ;
    PORT
      LAYER M5 ;
        RECT  17.664 0 17.688 0.192 ;
    END
  END di0[316]
  PIN di0[317]
    DIRECTION INPUT ;
    USE SIGNAL ;
    PORT
      LAYER M5 ;
        RECT  17.712 0 17.736 0.192 ;
    END
  END di0[317]
  PIN di0[318]
    DIRECTION INPUT ;
    USE SIGNAL ;
    PORT
      LAYER M5 ;
        RECT  17.76 0 17.784 0.192 ;
    END
  END di0[318]
  PIN di0[319]
    DIRECTION INPUT ;
    USE SIGNAL ;
    PORT
      LAYER M5 ;
        RECT  17.808 0 17.832 0.192 ;
    END
  END di0[319]
  PIN di0[31]
    DIRECTION INPUT ;
    USE SIGNAL ;
    PORT
      LAYER M5 ;
        RECT  3.984 0 4.008 0.192 ;
    END
  END di0[31]
  PIN di0[320]
    DIRECTION INPUT ;
    USE SIGNAL ;
    PORT
      LAYER M5 ;
        RECT  17.856 0 17.88 0.192 ;
    END
  END di0[320]
  PIN di0[321]
    DIRECTION INPUT ;
    USE SIGNAL ;
    PORT
      LAYER M5 ;
        RECT  17.904 0 17.928 0.192 ;
    END
  END di0[321]
  PIN di0[322]
    DIRECTION INPUT ;
    USE SIGNAL ;
    PORT
      LAYER M5 ;
        RECT  17.952 0 17.976 0.192 ;
    END
  END di0[322]
  PIN di0[323]
    DIRECTION INPUT ;
    USE SIGNAL ;
    PORT
      LAYER M5 ;
        RECT  18 0 18.024 0.192 ;
    END
  END di0[323]
  PIN di0[324]
    DIRECTION INPUT ;
    USE SIGNAL ;
    PORT
      LAYER M5 ;
        RECT  18.048 0 18.072 0.192 ;
    END
  END di0[324]
  PIN di0[325]
    DIRECTION INPUT ;
    USE SIGNAL ;
    PORT
      LAYER M5 ;
        RECT  18.096 0 18.12 0.192 ;
    END
  END di0[325]
  PIN di0[326]
    DIRECTION INPUT ;
    USE SIGNAL ;
    PORT
      LAYER M5 ;
        RECT  18.144 0 18.168 0.192 ;
    END
  END di0[326]
  PIN di0[327]
    DIRECTION INPUT ;
    USE SIGNAL ;
    PORT
      LAYER M5 ;
        RECT  18.192 0 18.216 0.192 ;
    END
  END di0[327]
  PIN di0[328]
    DIRECTION INPUT ;
    USE SIGNAL ;
    PORT
      LAYER M5 ;
        RECT  18.24 0 18.264 0.192 ;
    END
  END di0[328]
  PIN di0[329]
    DIRECTION INPUT ;
    USE SIGNAL ;
    PORT
      LAYER M5 ;
        RECT  18.288 0 18.312 0.192 ;
    END
  END di0[329]
  PIN di0[32]
    DIRECTION INPUT ;
    USE SIGNAL ;
    PORT
      LAYER M5 ;
        RECT  4.032 0 4.056 0.192 ;
    END
  END di0[32]
  PIN di0[330]
    DIRECTION INPUT ;
    USE SIGNAL ;
    PORT
      LAYER M5 ;
        RECT  18.336 0 18.36 0.192 ;
    END
  END di0[330]
  PIN di0[331]
    DIRECTION INPUT ;
    USE SIGNAL ;
    PORT
      LAYER M5 ;
        RECT  18.384 0 18.408 0.192 ;
    END
  END di0[331]
  PIN di0[332]
    DIRECTION INPUT ;
    USE SIGNAL ;
    PORT
      LAYER M5 ;
        RECT  18.432 0 18.456 0.192 ;
    END
  END di0[332]
  PIN di0[333]
    DIRECTION INPUT ;
    USE SIGNAL ;
    PORT
      LAYER M5 ;
        RECT  18.48 0 18.504 0.192 ;
    END
  END di0[333]
  PIN di0[334]
    DIRECTION INPUT ;
    USE SIGNAL ;
    PORT
      LAYER M5 ;
        RECT  18.528 0 18.552 0.192 ;
    END
  END di0[334]
  PIN di0[335]
    DIRECTION INPUT ;
    USE SIGNAL ;
    PORT
      LAYER M5 ;
        RECT  18.576 0 18.6 0.192 ;
    END
  END di0[335]
  PIN di0[336]
    DIRECTION INPUT ;
    USE SIGNAL ;
    PORT
      LAYER M5 ;
        RECT  18.624 0 18.648 0.192 ;
    END
  END di0[336]
  PIN di0[337]
    DIRECTION INPUT ;
    USE SIGNAL ;
    PORT
      LAYER M5 ;
        RECT  18.672 0 18.696 0.192 ;
    END
  END di0[337]
  PIN di0[338]
    DIRECTION INPUT ;
    USE SIGNAL ;
    PORT
      LAYER M5 ;
        RECT  18.72 0 18.744 0.192 ;
    END
  END di0[338]
  PIN di0[339]
    DIRECTION INPUT ;
    USE SIGNAL ;
    PORT
      LAYER M5 ;
        RECT  18.768 0 18.792 0.192 ;
    END
  END di0[339]
  PIN di0[33]
    DIRECTION INPUT ;
    USE SIGNAL ;
    PORT
      LAYER M5 ;
        RECT  4.08 0 4.104 0.192 ;
    END
  END di0[33]
  PIN di0[340]
    DIRECTION INPUT ;
    USE SIGNAL ;
    PORT
      LAYER M5 ;
        RECT  18.816 0 18.84 0.192 ;
    END
  END di0[340]
  PIN di0[341]
    DIRECTION INPUT ;
    USE SIGNAL ;
    PORT
      LAYER M5 ;
        RECT  18.864 0 18.888 0.192 ;
    END
  END di0[341]
  PIN di0[342]
    DIRECTION INPUT ;
    USE SIGNAL ;
    PORT
      LAYER M5 ;
        RECT  18.912 0 18.936 0.192 ;
    END
  END di0[342]
  PIN di0[343]
    DIRECTION INPUT ;
    USE SIGNAL ;
    PORT
      LAYER M5 ;
        RECT  18.96 0 18.984 0.192 ;
    END
  END di0[343]
  PIN di0[344]
    DIRECTION INPUT ;
    USE SIGNAL ;
    PORT
      LAYER M5 ;
        RECT  19.008 0 19.032 0.192 ;
    END
  END di0[344]
  PIN di0[345]
    DIRECTION INPUT ;
    USE SIGNAL ;
    PORT
      LAYER M5 ;
        RECT  19.056 0 19.08 0.192 ;
    END
  END di0[345]
  PIN di0[346]
    DIRECTION INPUT ;
    USE SIGNAL ;
    PORT
      LAYER M5 ;
        RECT  19.104 0 19.128 0.192 ;
    END
  END di0[346]
  PIN di0[347]
    DIRECTION INPUT ;
    USE SIGNAL ;
    PORT
      LAYER M5 ;
        RECT  19.152 0 19.176 0.192 ;
    END
  END di0[347]
  PIN di0[348]
    DIRECTION INPUT ;
    USE SIGNAL ;
    PORT
      LAYER M5 ;
        RECT  19.2 0 19.224 0.192 ;
    END
  END di0[348]
  PIN di0[349]
    DIRECTION INPUT ;
    USE SIGNAL ;
    PORT
      LAYER M5 ;
        RECT  19.248 0 19.272 0.192 ;
    END
  END di0[349]
  PIN di0[34]
    DIRECTION INPUT ;
    USE SIGNAL ;
    PORT
      LAYER M5 ;
        RECT  4.128 0 4.152 0.192 ;
    END
  END di0[34]
  PIN di0[350]
    DIRECTION INPUT ;
    USE SIGNAL ;
    PORT
      LAYER M5 ;
        RECT  19.296 0 19.32 0.192 ;
    END
  END di0[350]
  PIN di0[351]
    DIRECTION INPUT ;
    USE SIGNAL ;
    PORT
      LAYER M5 ;
        RECT  19.344 0 19.368 0.192 ;
    END
  END di0[351]
  PIN di0[352]
    DIRECTION INPUT ;
    USE SIGNAL ;
    PORT
      LAYER M5 ;
        RECT  19.392 0 19.416 0.192 ;
    END
  END di0[352]
  PIN di0[353]
    DIRECTION INPUT ;
    USE SIGNAL ;
    PORT
      LAYER M5 ;
        RECT  19.44 0 19.464 0.192 ;
    END
  END di0[353]
  PIN di0[354]
    DIRECTION INPUT ;
    USE SIGNAL ;
    PORT
      LAYER M5 ;
        RECT  19.488 0 19.512 0.192 ;
    END
  END di0[354]
  PIN di0[355]
    DIRECTION INPUT ;
    USE SIGNAL ;
    PORT
      LAYER M5 ;
        RECT  19.536 0 19.56 0.192 ;
    END
  END di0[355]
  PIN di0[356]
    DIRECTION INPUT ;
    USE SIGNAL ;
    PORT
      LAYER M5 ;
        RECT  19.584 0 19.608 0.192 ;
    END
  END di0[356]
  PIN di0[357]
    DIRECTION INPUT ;
    USE SIGNAL ;
    PORT
      LAYER M5 ;
        RECT  19.632 0 19.656 0.192 ;
    END
  END di0[357]
  PIN di0[358]
    DIRECTION INPUT ;
    USE SIGNAL ;
    PORT
      LAYER M5 ;
        RECT  19.68 0 19.704 0.192 ;
    END
  END di0[358]
  PIN di0[359]
    DIRECTION INPUT ;
    USE SIGNAL ;
    PORT
      LAYER M5 ;
        RECT  19.728 0 19.752 0.192 ;
    END
  END di0[359]
  PIN di0[35]
    DIRECTION INPUT ;
    USE SIGNAL ;
    PORT
      LAYER M5 ;
        RECT  4.176 0 4.2 0.192 ;
    END
  END di0[35]
  PIN di0[360]
    DIRECTION INPUT ;
    USE SIGNAL ;
    PORT
      LAYER M5 ;
        RECT  19.776 0 19.8 0.192 ;
    END
  END di0[360]
  PIN di0[361]
    DIRECTION INPUT ;
    USE SIGNAL ;
    PORT
      LAYER M5 ;
        RECT  19.824 0 19.848 0.192 ;
    END
  END di0[361]
  PIN di0[362]
    DIRECTION INPUT ;
    USE SIGNAL ;
    PORT
      LAYER M5 ;
        RECT  19.872 0 19.896 0.192 ;
    END
  END di0[362]
  PIN di0[363]
    DIRECTION INPUT ;
    USE SIGNAL ;
    PORT
      LAYER M5 ;
        RECT  19.92 0 19.944 0.192 ;
    END
  END di0[363]
  PIN di0[364]
    DIRECTION INPUT ;
    USE SIGNAL ;
    PORT
      LAYER M5 ;
        RECT  19.968 0 19.992 0.192 ;
    END
  END di0[364]
  PIN di0[365]
    DIRECTION INPUT ;
    USE SIGNAL ;
    PORT
      LAYER M5 ;
        RECT  20.016 0 20.04 0.192 ;
    END
  END di0[365]
  PIN di0[366]
    DIRECTION INPUT ;
    USE SIGNAL ;
    PORT
      LAYER M5 ;
        RECT  20.064 0 20.088 0.192 ;
    END
  END di0[366]
  PIN di0[367]
    DIRECTION INPUT ;
    USE SIGNAL ;
    PORT
      LAYER M5 ;
        RECT  20.112 0 20.136 0.192 ;
    END
  END di0[367]
  PIN di0[368]
    DIRECTION INPUT ;
    USE SIGNAL ;
    PORT
      LAYER M5 ;
        RECT  20.16 0 20.184 0.192 ;
    END
  END di0[368]
  PIN di0[369]
    DIRECTION INPUT ;
    USE SIGNAL ;
    PORT
      LAYER M5 ;
        RECT  20.208 0 20.232 0.192 ;
    END
  END di0[369]
  PIN di0[36]
    DIRECTION INPUT ;
    USE SIGNAL ;
    PORT
      LAYER M5 ;
        RECT  4.224 0 4.248 0.192 ;
    END
  END di0[36]
  PIN di0[370]
    DIRECTION INPUT ;
    USE SIGNAL ;
    PORT
      LAYER M5 ;
        RECT  20.256 0 20.28 0.192 ;
    END
  END di0[370]
  PIN di0[371]
    DIRECTION INPUT ;
    USE SIGNAL ;
    PORT
      LAYER M5 ;
        RECT  20.304 0 20.328 0.192 ;
    END
  END di0[371]
  PIN di0[372]
    DIRECTION INPUT ;
    USE SIGNAL ;
    PORT
      LAYER M5 ;
        RECT  20.352 0 20.376 0.192 ;
    END
  END di0[372]
  PIN di0[373]
    DIRECTION INPUT ;
    USE SIGNAL ;
    PORT
      LAYER M5 ;
        RECT  20.4 0 20.424 0.192 ;
    END
  END di0[373]
  PIN di0[374]
    DIRECTION INPUT ;
    USE SIGNAL ;
    PORT
      LAYER M5 ;
        RECT  20.448 0 20.472 0.192 ;
    END
  END di0[374]
  PIN di0[375]
    DIRECTION INPUT ;
    USE SIGNAL ;
    PORT
      LAYER M5 ;
        RECT  20.496 0 20.52 0.192 ;
    END
  END di0[375]
  PIN di0[376]
    DIRECTION INPUT ;
    USE SIGNAL ;
    PORT
      LAYER M5 ;
        RECT  20.544 0 20.568 0.192 ;
    END
  END di0[376]
  PIN di0[377]
    DIRECTION INPUT ;
    USE SIGNAL ;
    PORT
      LAYER M5 ;
        RECT  20.592 0 20.616 0.192 ;
    END
  END di0[377]
  PIN di0[378]
    DIRECTION INPUT ;
    USE SIGNAL ;
    PORT
      LAYER M5 ;
        RECT  20.64 0 20.664 0.192 ;
    END
  END di0[378]
  PIN di0[379]
    DIRECTION INPUT ;
    USE SIGNAL ;
    PORT
      LAYER M5 ;
        RECT  20.688 0 20.712 0.192 ;
    END
  END di0[379]
  PIN di0[37]
    DIRECTION INPUT ;
    USE SIGNAL ;
    PORT
      LAYER M5 ;
        RECT  4.272 0 4.296 0.192 ;
    END
  END di0[37]
  PIN di0[380]
    DIRECTION INPUT ;
    USE SIGNAL ;
    PORT
      LAYER M5 ;
        RECT  20.736 0 20.76 0.192 ;
    END
  END di0[380]
  PIN di0[381]
    DIRECTION INPUT ;
    USE SIGNAL ;
    PORT
      LAYER M5 ;
        RECT  20.784 0 20.808 0.192 ;
    END
  END di0[381]
  PIN di0[382]
    DIRECTION INPUT ;
    USE SIGNAL ;
    PORT
      LAYER M5 ;
        RECT  20.832 0 20.856 0.192 ;
    END
  END di0[382]
  PIN di0[383]
    DIRECTION INPUT ;
    USE SIGNAL ;
    PORT
      LAYER M5 ;
        RECT  20.88 0 20.904 0.192 ;
    END
  END di0[383]
  PIN di0[384]
    DIRECTION INPUT ;
    USE SIGNAL ;
    PORT
      LAYER M5 ;
        RECT  20.928 0 20.952 0.192 ;
    END
  END di0[384]
  PIN di0[385]
    DIRECTION INPUT ;
    USE SIGNAL ;
    PORT
      LAYER M5 ;
        RECT  20.976 0 21 0.192 ;
    END
  END di0[385]
  PIN di0[386]
    DIRECTION INPUT ;
    USE SIGNAL ;
    PORT
      LAYER M5 ;
        RECT  21.024 0 21.048 0.192 ;
    END
  END di0[386]
  PIN di0[387]
    DIRECTION INPUT ;
    USE SIGNAL ;
    PORT
      LAYER M5 ;
        RECT  21.072 0 21.096 0.192 ;
    END
  END di0[387]
  PIN di0[388]
    DIRECTION INPUT ;
    USE SIGNAL ;
    PORT
      LAYER M5 ;
        RECT  21.12 0 21.144 0.192 ;
    END
  END di0[388]
  PIN di0[389]
    DIRECTION INPUT ;
    USE SIGNAL ;
    PORT
      LAYER M5 ;
        RECT  21.168 0 21.192 0.192 ;
    END
  END di0[389]
  PIN di0[38]
    DIRECTION INPUT ;
    USE SIGNAL ;
    PORT
      LAYER M5 ;
        RECT  4.32 0 4.344 0.192 ;
    END
  END di0[38]
  PIN di0[390]
    DIRECTION INPUT ;
    USE SIGNAL ;
    PORT
      LAYER M5 ;
        RECT  21.216 0 21.24 0.192 ;
    END
  END di0[390]
  PIN di0[391]
    DIRECTION INPUT ;
    USE SIGNAL ;
    PORT
      LAYER M5 ;
        RECT  21.264 0 21.288 0.192 ;
    END
  END di0[391]
  PIN di0[392]
    DIRECTION INPUT ;
    USE SIGNAL ;
    PORT
      LAYER M5 ;
        RECT  21.312 0 21.336 0.192 ;
    END
  END di0[392]
  PIN di0[393]
    DIRECTION INPUT ;
    USE SIGNAL ;
    PORT
      LAYER M5 ;
        RECT  21.36 0 21.384 0.192 ;
    END
  END di0[393]
  PIN di0[394]
    DIRECTION INPUT ;
    USE SIGNAL ;
    PORT
      LAYER M5 ;
        RECT  21.408 0 21.432 0.192 ;
    END
  END di0[394]
  PIN di0[395]
    DIRECTION INPUT ;
    USE SIGNAL ;
    PORT
      LAYER M5 ;
        RECT  21.456 0 21.48 0.192 ;
    END
  END di0[395]
  PIN di0[396]
    DIRECTION INPUT ;
    USE SIGNAL ;
    PORT
      LAYER M5 ;
        RECT  21.504 0 21.528 0.192 ;
    END
  END di0[396]
  PIN di0[397]
    DIRECTION INPUT ;
    USE SIGNAL ;
    PORT
      LAYER M5 ;
        RECT  21.552 0 21.576 0.192 ;
    END
  END di0[397]
  PIN di0[398]
    DIRECTION INPUT ;
    USE SIGNAL ;
    PORT
      LAYER M5 ;
        RECT  21.6 0 21.624 0.192 ;
    END
  END di0[398]
  PIN di0[399]
    DIRECTION INPUT ;
    USE SIGNAL ;
    PORT
      LAYER M5 ;
        RECT  21.648 0 21.672 0.192 ;
    END
  END di0[399]
  PIN di0[39]
    DIRECTION INPUT ;
    USE SIGNAL ;
    PORT
      LAYER M5 ;
        RECT  4.368 0 4.392 0.192 ;
    END
  END di0[39]
  PIN di0[3]
    DIRECTION INPUT ;
    USE SIGNAL ;
    PORT
      LAYER M5 ;
        RECT  2.64 0 2.664 0.192 ;
    END
  END di0[3]
  PIN di0[400]
    DIRECTION INPUT ;
    USE SIGNAL ;
    PORT
      LAYER M5 ;
        RECT  21.696 0 21.72 0.192 ;
    END
  END di0[400]
  PIN di0[401]
    DIRECTION INPUT ;
    USE SIGNAL ;
    PORT
      LAYER M5 ;
        RECT  21.744 0 21.768 0.192 ;
    END
  END di0[401]
  PIN di0[402]
    DIRECTION INPUT ;
    USE SIGNAL ;
    PORT
      LAYER M5 ;
        RECT  21.792 0 21.816 0.192 ;
    END
  END di0[402]
  PIN di0[403]
    DIRECTION INPUT ;
    USE SIGNAL ;
    PORT
      LAYER M5 ;
        RECT  21.84 0 21.864 0.192 ;
    END
  END di0[403]
  PIN di0[404]
    DIRECTION INPUT ;
    USE SIGNAL ;
    PORT
      LAYER M5 ;
        RECT  21.888 0 21.912 0.192 ;
    END
  END di0[404]
  PIN di0[405]
    DIRECTION INPUT ;
    USE SIGNAL ;
    PORT
      LAYER M5 ;
        RECT  21.936 0 21.96 0.192 ;
    END
  END di0[405]
  PIN di0[406]
    DIRECTION INPUT ;
    USE SIGNAL ;
    PORT
      LAYER M5 ;
        RECT  21.984 0 22.008 0.192 ;
    END
  END di0[406]
  PIN di0[407]
    DIRECTION INPUT ;
    USE SIGNAL ;
    PORT
      LAYER M5 ;
        RECT  22.032 0 22.056 0.192 ;
    END
  END di0[407]
  PIN di0[408]
    DIRECTION INPUT ;
    USE SIGNAL ;
    PORT
      LAYER M5 ;
        RECT  22.08 0 22.104 0.192 ;
    END
  END di0[408]
  PIN di0[409]
    DIRECTION INPUT ;
    USE SIGNAL ;
    PORT
      LAYER M5 ;
        RECT  22.128 0 22.152 0.192 ;
    END
  END di0[409]
  PIN di0[40]
    DIRECTION INPUT ;
    USE SIGNAL ;
    PORT
      LAYER M5 ;
        RECT  4.416 0 4.44 0.192 ;
    END
  END di0[40]
  PIN di0[410]
    DIRECTION INPUT ;
    USE SIGNAL ;
    PORT
      LAYER M5 ;
        RECT  22.176 0 22.2 0.192 ;
    END
  END di0[410]
  PIN di0[411]
    DIRECTION INPUT ;
    USE SIGNAL ;
    PORT
      LAYER M5 ;
        RECT  22.224 0 22.248 0.192 ;
    END
  END di0[411]
  PIN di0[412]
    DIRECTION INPUT ;
    USE SIGNAL ;
    PORT
      LAYER M5 ;
        RECT  22.272 0 22.296 0.192 ;
    END
  END di0[412]
  PIN di0[413]
    DIRECTION INPUT ;
    USE SIGNAL ;
    PORT
      LAYER M5 ;
        RECT  22.32 0 22.344 0.192 ;
    END
  END di0[413]
  PIN di0[414]
    DIRECTION INPUT ;
    USE SIGNAL ;
    PORT
      LAYER M5 ;
        RECT  22.368 0 22.392 0.192 ;
    END
  END di0[414]
  PIN di0[415]
    DIRECTION INPUT ;
    USE SIGNAL ;
    PORT
      LAYER M5 ;
        RECT  22.416 0 22.44 0.192 ;
    END
  END di0[415]
  PIN di0[416]
    DIRECTION INPUT ;
    USE SIGNAL ;
    PORT
      LAYER M5 ;
        RECT  22.464 0 22.488 0.192 ;
    END
  END di0[416]
  PIN di0[417]
    DIRECTION INPUT ;
    USE SIGNAL ;
    PORT
      LAYER M5 ;
        RECT  22.512 0 22.536 0.192 ;
    END
  END di0[417]
  PIN di0[418]
    DIRECTION INPUT ;
    USE SIGNAL ;
    PORT
      LAYER M5 ;
        RECT  22.56 0 22.584 0.192 ;
    END
  END di0[418]
  PIN di0[419]
    DIRECTION INPUT ;
    USE SIGNAL ;
    PORT
      LAYER M5 ;
        RECT  22.608 0 22.632 0.192 ;
    END
  END di0[419]
  PIN di0[41]
    DIRECTION INPUT ;
    USE SIGNAL ;
    PORT
      LAYER M5 ;
        RECT  4.464 0 4.488 0.192 ;
    END
  END di0[41]
  PIN di0[420]
    DIRECTION INPUT ;
    USE SIGNAL ;
    PORT
      LAYER M5 ;
        RECT  22.656 0 22.68 0.192 ;
    END
  END di0[420]
  PIN di0[421]
    DIRECTION INPUT ;
    USE SIGNAL ;
    PORT
      LAYER M5 ;
        RECT  22.704 0 22.728 0.192 ;
    END
  END di0[421]
  PIN di0[422]
    DIRECTION INPUT ;
    USE SIGNAL ;
    PORT
      LAYER M5 ;
        RECT  22.752 0 22.776 0.192 ;
    END
  END di0[422]
  PIN di0[423]
    DIRECTION INPUT ;
    USE SIGNAL ;
    PORT
      LAYER M5 ;
        RECT  22.8 0 22.824 0.192 ;
    END
  END di0[423]
  PIN di0[424]
    DIRECTION INPUT ;
    USE SIGNAL ;
    PORT
      LAYER M5 ;
        RECT  22.848 0 22.872 0.192 ;
    END
  END di0[424]
  PIN di0[425]
    DIRECTION INPUT ;
    USE SIGNAL ;
    PORT
      LAYER M5 ;
        RECT  22.896 0 22.92 0.192 ;
    END
  END di0[425]
  PIN di0[426]
    DIRECTION INPUT ;
    USE SIGNAL ;
    PORT
      LAYER M5 ;
        RECT  22.944 0 22.968 0.192 ;
    END
  END di0[426]
  PIN di0[427]
    DIRECTION INPUT ;
    USE SIGNAL ;
    PORT
      LAYER M5 ;
        RECT  22.992 0 23.016 0.192 ;
    END
  END di0[427]
  PIN di0[428]
    DIRECTION INPUT ;
    USE SIGNAL ;
    PORT
      LAYER M5 ;
        RECT  23.04 0 23.064 0.192 ;
    END
  END di0[428]
  PIN di0[429]
    DIRECTION INPUT ;
    USE SIGNAL ;
    PORT
      LAYER M5 ;
        RECT  23.088 0 23.112 0.192 ;
    END
  END di0[429]
  PIN di0[42]
    DIRECTION INPUT ;
    USE SIGNAL ;
    PORT
      LAYER M5 ;
        RECT  4.512 0 4.536 0.192 ;
    END
  END di0[42]
  PIN di0[430]
    DIRECTION INPUT ;
    USE SIGNAL ;
    PORT
      LAYER M5 ;
        RECT  23.136 0 23.16 0.192 ;
    END
  END di0[430]
  PIN di0[431]
    DIRECTION INPUT ;
    USE SIGNAL ;
    PORT
      LAYER M5 ;
        RECT  23.184 0 23.208 0.192 ;
    END
  END di0[431]
  PIN di0[432]
    DIRECTION INPUT ;
    USE SIGNAL ;
    PORT
      LAYER M5 ;
        RECT  23.232 0 23.256 0.192 ;
    END
  END di0[432]
  PIN di0[433]
    DIRECTION INPUT ;
    USE SIGNAL ;
    PORT
      LAYER M5 ;
        RECT  23.28 0 23.304 0.192 ;
    END
  END di0[433]
  PIN di0[434]
    DIRECTION INPUT ;
    USE SIGNAL ;
    PORT
      LAYER M5 ;
        RECT  23.328 0 23.352 0.192 ;
    END
  END di0[434]
  PIN di0[435]
    DIRECTION INPUT ;
    USE SIGNAL ;
    PORT
      LAYER M5 ;
        RECT  23.376 0 23.4 0.192 ;
    END
  END di0[435]
  PIN di0[436]
    DIRECTION INPUT ;
    USE SIGNAL ;
    PORT
      LAYER M5 ;
        RECT  23.424 0 23.448 0.192 ;
    END
  END di0[436]
  PIN di0[437]
    DIRECTION INPUT ;
    USE SIGNAL ;
    PORT
      LAYER M5 ;
        RECT  23.472 0 23.496 0.192 ;
    END
  END di0[437]
  PIN di0[438]
    DIRECTION INPUT ;
    USE SIGNAL ;
    PORT
      LAYER M5 ;
        RECT  23.52 0 23.544 0.192 ;
    END
  END di0[438]
  PIN di0[439]
    DIRECTION INPUT ;
    USE SIGNAL ;
    PORT
      LAYER M5 ;
        RECT  23.568 0 23.592 0.192 ;
    END
  END di0[439]
  PIN di0[43]
    DIRECTION INPUT ;
    USE SIGNAL ;
    PORT
      LAYER M5 ;
        RECT  4.56 0 4.584 0.192 ;
    END
  END di0[43]
  PIN di0[440]
    DIRECTION INPUT ;
    USE SIGNAL ;
    PORT
      LAYER M5 ;
        RECT  23.616 0 23.64 0.192 ;
    END
  END di0[440]
  PIN di0[441]
    DIRECTION INPUT ;
    USE SIGNAL ;
    PORT
      LAYER M5 ;
        RECT  23.664 0 23.688 0.192 ;
    END
  END di0[441]
  PIN di0[442]
    DIRECTION INPUT ;
    USE SIGNAL ;
    PORT
      LAYER M5 ;
        RECT  23.712 0 23.736 0.192 ;
    END
  END di0[442]
  PIN di0[443]
    DIRECTION INPUT ;
    USE SIGNAL ;
    PORT
      LAYER M5 ;
        RECT  23.76 0 23.784 0.192 ;
    END
  END di0[443]
  PIN di0[444]
    DIRECTION INPUT ;
    USE SIGNAL ;
    PORT
      LAYER M5 ;
        RECT  23.808 0 23.832 0.192 ;
    END
  END di0[444]
  PIN di0[445]
    DIRECTION INPUT ;
    USE SIGNAL ;
    PORT
      LAYER M5 ;
        RECT  23.856 0 23.88 0.192 ;
    END
  END di0[445]
  PIN di0[446]
    DIRECTION INPUT ;
    USE SIGNAL ;
    PORT
      LAYER M5 ;
        RECT  23.904 0 23.928 0.192 ;
    END
  END di0[446]
  PIN di0[447]
    DIRECTION INPUT ;
    USE SIGNAL ;
    PORT
      LAYER M5 ;
        RECT  23.952 0 23.976 0.192 ;
    END
  END di0[447]
  PIN di0[448]
    DIRECTION INPUT ;
    USE SIGNAL ;
    PORT
      LAYER M5 ;
        RECT  24 0 24.024 0.192 ;
    END
  END di0[448]
  PIN di0[449]
    DIRECTION INPUT ;
    USE SIGNAL ;
    PORT
      LAYER M5 ;
        RECT  24.048 0 24.072 0.192 ;
    END
  END di0[449]
  PIN di0[44]
    DIRECTION INPUT ;
    USE SIGNAL ;
    PORT
      LAYER M5 ;
        RECT  4.608 0 4.632 0.192 ;
    END
  END di0[44]
  PIN di0[450]
    DIRECTION INPUT ;
    USE SIGNAL ;
    PORT
      LAYER M5 ;
        RECT  24.096 0 24.12 0.192 ;
    END
  END di0[450]
  PIN di0[451]
    DIRECTION INPUT ;
    USE SIGNAL ;
    PORT
      LAYER M5 ;
        RECT  24.144 0 24.168 0.192 ;
    END
  END di0[451]
  PIN di0[452]
    DIRECTION INPUT ;
    USE SIGNAL ;
    PORT
      LAYER M5 ;
        RECT  24.192 0 24.216 0.192 ;
    END
  END di0[452]
  PIN di0[453]
    DIRECTION INPUT ;
    USE SIGNAL ;
    PORT
      LAYER M5 ;
        RECT  24.24 0 24.264 0.192 ;
    END
  END di0[453]
  PIN di0[454]
    DIRECTION INPUT ;
    USE SIGNAL ;
    PORT
      LAYER M5 ;
        RECT  24.288 0 24.312 0.192 ;
    END
  END di0[454]
  PIN di0[455]
    DIRECTION INPUT ;
    USE SIGNAL ;
    PORT
      LAYER M5 ;
        RECT  24.336 0 24.36 0.192 ;
    END
  END di0[455]
  PIN di0[456]
    DIRECTION INPUT ;
    USE SIGNAL ;
    PORT
      LAYER M5 ;
        RECT  24.384 0 24.408 0.192 ;
    END
  END di0[456]
  PIN di0[457]
    DIRECTION INPUT ;
    USE SIGNAL ;
    PORT
      LAYER M5 ;
        RECT  24.432 0 24.456 0.192 ;
    END
  END di0[457]
  PIN di0[458]
    DIRECTION INPUT ;
    USE SIGNAL ;
    PORT
      LAYER M5 ;
        RECT  24.48 0 24.504 0.192 ;
    END
  END di0[458]
  PIN di0[459]
    DIRECTION INPUT ;
    USE SIGNAL ;
    PORT
      LAYER M5 ;
        RECT  24.528 0 24.552 0.192 ;
    END
  END di0[459]
  PIN di0[45]
    DIRECTION INPUT ;
    USE SIGNAL ;
    PORT
      LAYER M5 ;
        RECT  4.656 0 4.68 0.192 ;
    END
  END di0[45]
  PIN di0[460]
    DIRECTION INPUT ;
    USE SIGNAL ;
    PORT
      LAYER M5 ;
        RECT  24.576 0 24.6 0.192 ;
    END
  END di0[460]
  PIN di0[461]
    DIRECTION INPUT ;
    USE SIGNAL ;
    PORT
      LAYER M5 ;
        RECT  24.624 0 24.648 0.192 ;
    END
  END di0[461]
  PIN di0[462]
    DIRECTION INPUT ;
    USE SIGNAL ;
    PORT
      LAYER M5 ;
        RECT  24.672 0 24.696 0.192 ;
    END
  END di0[462]
  PIN di0[463]
    DIRECTION INPUT ;
    USE SIGNAL ;
    PORT
      LAYER M5 ;
        RECT  24.72 0 24.744 0.192 ;
    END
  END di0[463]
  PIN di0[464]
    DIRECTION INPUT ;
    USE SIGNAL ;
    PORT
      LAYER M5 ;
        RECT  24.768 0 24.792 0.192 ;
    END
  END di0[464]
  PIN di0[465]
    DIRECTION INPUT ;
    USE SIGNAL ;
    PORT
      LAYER M5 ;
        RECT  24.816 0 24.84 0.192 ;
    END
  END di0[465]
  PIN di0[466]
    DIRECTION INPUT ;
    USE SIGNAL ;
    PORT
      LAYER M5 ;
        RECT  24.864 0 24.888 0.192 ;
    END
  END di0[466]
  PIN di0[467]
    DIRECTION INPUT ;
    USE SIGNAL ;
    PORT
      LAYER M5 ;
        RECT  24.912 0 24.936 0.192 ;
    END
  END di0[467]
  PIN di0[468]
    DIRECTION INPUT ;
    USE SIGNAL ;
    PORT
      LAYER M5 ;
        RECT  24.96 0 24.984 0.192 ;
    END
  END di0[468]
  PIN di0[469]
    DIRECTION INPUT ;
    USE SIGNAL ;
    PORT
      LAYER M5 ;
        RECT  25.008 0 25.032 0.192 ;
    END
  END di0[469]
  PIN di0[46]
    DIRECTION INPUT ;
    USE SIGNAL ;
    PORT
      LAYER M5 ;
        RECT  4.704 0 4.728 0.192 ;
    END
  END di0[46]
  PIN di0[470]
    DIRECTION INPUT ;
    USE SIGNAL ;
    PORT
      LAYER M5 ;
        RECT  25.056 0 25.08 0.192 ;
    END
  END di0[470]
  PIN di0[471]
    DIRECTION INPUT ;
    USE SIGNAL ;
    PORT
      LAYER M5 ;
        RECT  25.104 0 25.128 0.192 ;
    END
  END di0[471]
  PIN di0[472]
    DIRECTION INPUT ;
    USE SIGNAL ;
    PORT
      LAYER M5 ;
        RECT  25.152 0 25.176 0.192 ;
    END
  END di0[472]
  PIN di0[473]
    DIRECTION INPUT ;
    USE SIGNAL ;
    PORT
      LAYER M5 ;
        RECT  25.2 0 25.224 0.192 ;
    END
  END di0[473]
  PIN di0[474]
    DIRECTION INPUT ;
    USE SIGNAL ;
    PORT
      LAYER M5 ;
        RECT  25.248 0 25.272 0.192 ;
    END
  END di0[474]
  PIN di0[475]
    DIRECTION INPUT ;
    USE SIGNAL ;
    PORT
      LAYER M5 ;
        RECT  25.296 0 25.32 0.192 ;
    END
  END di0[475]
  PIN di0[476]
    DIRECTION INPUT ;
    USE SIGNAL ;
    PORT
      LAYER M5 ;
        RECT  25.344 0 25.368 0.192 ;
    END
  END di0[476]
  PIN di0[477]
    DIRECTION INPUT ;
    USE SIGNAL ;
    PORT
      LAYER M5 ;
        RECT  25.392 0 25.416 0.192 ;
    END
  END di0[477]
  PIN di0[478]
    DIRECTION INPUT ;
    USE SIGNAL ;
    PORT
      LAYER M5 ;
        RECT  25.44 0 25.464 0.192 ;
    END
  END di0[478]
  PIN di0[479]
    DIRECTION INPUT ;
    USE SIGNAL ;
    PORT
      LAYER M5 ;
        RECT  25.488 0 25.512 0.192 ;
    END
  END di0[479]
  PIN di0[47]
    DIRECTION INPUT ;
    USE SIGNAL ;
    PORT
      LAYER M5 ;
        RECT  4.752 0 4.776 0.192 ;
    END
  END di0[47]
  PIN di0[480]
    DIRECTION INPUT ;
    USE SIGNAL ;
    PORT
      LAYER M5 ;
        RECT  25.536 0 25.56 0.192 ;
    END
  END di0[480]
  PIN di0[481]
    DIRECTION INPUT ;
    USE SIGNAL ;
    PORT
      LAYER M5 ;
        RECT  25.584 0 25.608 0.192 ;
    END
  END di0[481]
  PIN di0[482]
    DIRECTION INPUT ;
    USE SIGNAL ;
    PORT
      LAYER M5 ;
        RECT  25.632 0 25.656 0.192 ;
    END
  END di0[482]
  PIN di0[483]
    DIRECTION INPUT ;
    USE SIGNAL ;
    PORT
      LAYER M5 ;
        RECT  25.68 0 25.704 0.192 ;
    END
  END di0[483]
  PIN di0[484]
    DIRECTION INPUT ;
    USE SIGNAL ;
    PORT
      LAYER M5 ;
        RECT  25.728 0 25.752 0.192 ;
    END
  END di0[484]
  PIN di0[485]
    DIRECTION INPUT ;
    USE SIGNAL ;
    PORT
      LAYER M5 ;
        RECT  25.776 0 25.8 0.192 ;
    END
  END di0[485]
  PIN di0[486]
    DIRECTION INPUT ;
    USE SIGNAL ;
    PORT
      LAYER M5 ;
        RECT  25.824 0 25.848 0.192 ;
    END
  END di0[486]
  PIN di0[487]
    DIRECTION INPUT ;
    USE SIGNAL ;
    PORT
      LAYER M5 ;
        RECT  25.872 0 25.896 0.192 ;
    END
  END di0[487]
  PIN di0[488]
    DIRECTION INPUT ;
    USE SIGNAL ;
    PORT
      LAYER M5 ;
        RECT  25.92 0 25.944 0.192 ;
    END
  END di0[488]
  PIN di0[489]
    DIRECTION INPUT ;
    USE SIGNAL ;
    PORT
      LAYER M5 ;
        RECT  25.968 0 25.992 0.192 ;
    END
  END di0[489]
  PIN di0[48]
    DIRECTION INPUT ;
    USE SIGNAL ;
    PORT
      LAYER M5 ;
        RECT  4.8 0 4.824 0.192 ;
    END
  END di0[48]
  PIN di0[490]
    DIRECTION INPUT ;
    USE SIGNAL ;
    PORT
      LAYER M5 ;
        RECT  26.016 0 26.04 0.192 ;
    END
  END di0[490]
  PIN di0[491]
    DIRECTION INPUT ;
    USE SIGNAL ;
    PORT
      LAYER M5 ;
        RECT  26.064 0 26.088 0.192 ;
    END
  END di0[491]
  PIN di0[492]
    DIRECTION INPUT ;
    USE SIGNAL ;
    PORT
      LAYER M5 ;
        RECT  26.112 0 26.136 0.192 ;
    END
  END di0[492]
  PIN di0[493]
    DIRECTION INPUT ;
    USE SIGNAL ;
    PORT
      LAYER M5 ;
        RECT  26.16 0 26.184 0.192 ;
    END
  END di0[493]
  PIN di0[494]
    DIRECTION INPUT ;
    USE SIGNAL ;
    PORT
      LAYER M5 ;
        RECT  26.208 0 26.232 0.192 ;
    END
  END di0[494]
  PIN di0[495]
    DIRECTION INPUT ;
    USE SIGNAL ;
    PORT
      LAYER M5 ;
        RECT  26.256 0 26.28 0.192 ;
    END
  END di0[495]
  PIN di0[496]
    DIRECTION INPUT ;
    USE SIGNAL ;
    PORT
      LAYER M5 ;
        RECT  26.304 0 26.328 0.192 ;
    END
  END di0[496]
  PIN di0[497]
    DIRECTION INPUT ;
    USE SIGNAL ;
    PORT
      LAYER M5 ;
        RECT  26.352 0 26.376 0.192 ;
    END
  END di0[497]
  PIN di0[498]
    DIRECTION INPUT ;
    USE SIGNAL ;
    PORT
      LAYER M5 ;
        RECT  26.4 0 26.424 0.192 ;
    END
  END di0[498]
  PIN di0[499]
    DIRECTION INPUT ;
    USE SIGNAL ;
    PORT
      LAYER M5 ;
        RECT  26.448 0 26.472 0.192 ;
    END
  END di0[499]
  PIN di0[49]
    DIRECTION INPUT ;
    USE SIGNAL ;
    PORT
      LAYER M5 ;
        RECT  4.848 0 4.872 0.192 ;
    END
  END di0[49]
  PIN di0[4]
    DIRECTION INPUT ;
    USE SIGNAL ;
    PORT
      LAYER M5 ;
        RECT  2.688 0 2.712 0.192 ;
    END
  END di0[4]
  PIN di0[500]
    DIRECTION INPUT ;
    USE SIGNAL ;
    PORT
      LAYER M5 ;
        RECT  26.496 0 26.52 0.192 ;
    END
  END di0[500]
  PIN di0[501]
    DIRECTION INPUT ;
    USE SIGNAL ;
    PORT
      LAYER M5 ;
        RECT  26.544 0 26.568 0.192 ;
    END
  END di0[501]
  PIN di0[502]
    DIRECTION INPUT ;
    USE SIGNAL ;
    PORT
      LAYER M5 ;
        RECT  26.592 0 26.616 0.192 ;
    END
  END di0[502]
  PIN di0[503]
    DIRECTION INPUT ;
    USE SIGNAL ;
    PORT
      LAYER M5 ;
        RECT  26.64 0 26.664 0.192 ;
    END
  END di0[503]
  PIN di0[504]
    DIRECTION INPUT ;
    USE SIGNAL ;
    PORT
      LAYER M5 ;
        RECT  26.688 0 26.712 0.192 ;
    END
  END di0[504]
  PIN di0[505]
    DIRECTION INPUT ;
    USE SIGNAL ;
    PORT
      LAYER M5 ;
        RECT  26.736 0 26.76 0.192 ;
    END
  END di0[505]
  PIN di0[506]
    DIRECTION INPUT ;
    USE SIGNAL ;
    PORT
      LAYER M5 ;
        RECT  26.784 0 26.808 0.192 ;
    END
  END di0[506]
  PIN di0[507]
    DIRECTION INPUT ;
    USE SIGNAL ;
    PORT
      LAYER M5 ;
        RECT  26.832 0 26.856 0.192 ;
    END
  END di0[507]
  PIN di0[508]
    DIRECTION INPUT ;
    USE SIGNAL ;
    PORT
      LAYER M5 ;
        RECT  26.88 0 26.904 0.192 ;
    END
  END di0[508]
  PIN di0[509]
    DIRECTION INPUT ;
    USE SIGNAL ;
    PORT
      LAYER M5 ;
        RECT  26.928 0 26.952 0.192 ;
    END
  END di0[509]
  PIN di0[50]
    DIRECTION INPUT ;
    USE SIGNAL ;
    PORT
      LAYER M5 ;
        RECT  4.896 0 4.92 0.192 ;
    END
  END di0[50]
  PIN di0[510]
    DIRECTION INPUT ;
    USE SIGNAL ;
    PORT
      LAYER M5 ;
        RECT  26.976 0 27 0.192 ;
    END
  END di0[510]
  PIN di0[511]
    DIRECTION INPUT ;
    USE SIGNAL ;
    PORT
      LAYER M5 ;
        RECT  27.024 0 27.048 0.192 ;
    END
  END di0[511]
  PIN di0[51]
    DIRECTION INPUT ;
    USE SIGNAL ;
    PORT
      LAYER M5 ;
        RECT  4.944 0 4.968 0.192 ;
    END
  END di0[51]
  PIN di0[52]
    DIRECTION INPUT ;
    USE SIGNAL ;
    PORT
      LAYER M5 ;
        RECT  4.992 0 5.016 0.192 ;
    END
  END di0[52]
  PIN di0[53]
    DIRECTION INPUT ;
    USE SIGNAL ;
    PORT
      LAYER M5 ;
        RECT  5.04 0 5.064 0.192 ;
    END
  END di0[53]
  PIN di0[54]
    DIRECTION INPUT ;
    USE SIGNAL ;
    PORT
      LAYER M5 ;
        RECT  5.088 0 5.112 0.192 ;
    END
  END di0[54]
  PIN di0[55]
    DIRECTION INPUT ;
    USE SIGNAL ;
    PORT
      LAYER M5 ;
        RECT  5.136 0 5.16 0.192 ;
    END
  END di0[55]
  PIN di0[56]
    DIRECTION INPUT ;
    USE SIGNAL ;
    PORT
      LAYER M5 ;
        RECT  5.184 0 5.208 0.192 ;
    END
  END di0[56]
  PIN di0[57]
    DIRECTION INPUT ;
    USE SIGNAL ;
    PORT
      LAYER M5 ;
        RECT  5.232 0 5.256 0.192 ;
    END
  END di0[57]
  PIN di0[58]
    DIRECTION INPUT ;
    USE SIGNAL ;
    PORT
      LAYER M5 ;
        RECT  5.28 0 5.304 0.192 ;
    END
  END di0[58]
  PIN di0[59]
    DIRECTION INPUT ;
    USE SIGNAL ;
    PORT
      LAYER M5 ;
        RECT  5.328 0 5.352 0.192 ;
    END
  END di0[59]
  PIN di0[5]
    DIRECTION INPUT ;
    USE SIGNAL ;
    PORT
      LAYER M5 ;
        RECT  2.736 0 2.76 0.192 ;
    END
  END di0[5]
  PIN di0[60]
    DIRECTION INPUT ;
    USE SIGNAL ;
    PORT
      LAYER M5 ;
        RECT  5.376 0 5.4 0.192 ;
    END
  END di0[60]
  PIN di0[61]
    DIRECTION INPUT ;
    USE SIGNAL ;
    PORT
      LAYER M5 ;
        RECT  5.424 0 5.448 0.192 ;
    END
  END di0[61]
  PIN di0[62]
    DIRECTION INPUT ;
    USE SIGNAL ;
    PORT
      LAYER M5 ;
        RECT  5.472 0 5.496 0.192 ;
    END
  END di0[62]
  PIN di0[63]
    DIRECTION INPUT ;
    USE SIGNAL ;
    PORT
      LAYER M5 ;
        RECT  5.52 0 5.544 0.192 ;
    END
  END di0[63]
  PIN di0[64]
    DIRECTION INPUT ;
    USE SIGNAL ;
    PORT
      LAYER M5 ;
        RECT  5.568 0 5.592 0.192 ;
    END
  END di0[64]
  PIN di0[65]
    DIRECTION INPUT ;
    USE SIGNAL ;
    PORT
      LAYER M5 ;
        RECT  5.616 0 5.64 0.192 ;
    END
  END di0[65]
  PIN di0[66]
    DIRECTION INPUT ;
    USE SIGNAL ;
    PORT
      LAYER M5 ;
        RECT  5.664 0 5.688 0.192 ;
    END
  END di0[66]
  PIN di0[67]
    DIRECTION INPUT ;
    USE SIGNAL ;
    PORT
      LAYER M5 ;
        RECT  5.712 0 5.736 0.192 ;
    END
  END di0[67]
  PIN di0[68]
    DIRECTION INPUT ;
    USE SIGNAL ;
    PORT
      LAYER M5 ;
        RECT  5.76 0 5.784 0.192 ;
    END
  END di0[68]
  PIN di0[69]
    DIRECTION INPUT ;
    USE SIGNAL ;
    PORT
      LAYER M5 ;
        RECT  5.808 0 5.832 0.192 ;
    END
  END di0[69]
  PIN di0[6]
    DIRECTION INPUT ;
    USE SIGNAL ;
    PORT
      LAYER M5 ;
        RECT  2.784 0 2.808 0.192 ;
    END
  END di0[6]
  PIN di0[70]
    DIRECTION INPUT ;
    USE SIGNAL ;
    PORT
      LAYER M5 ;
        RECT  5.856 0 5.88 0.192 ;
    END
  END di0[70]
  PIN di0[71]
    DIRECTION INPUT ;
    USE SIGNAL ;
    PORT
      LAYER M5 ;
        RECT  5.904 0 5.928 0.192 ;
    END
  END di0[71]
  PIN di0[72]
    DIRECTION INPUT ;
    USE SIGNAL ;
    PORT
      LAYER M5 ;
        RECT  5.952 0 5.976 0.192 ;
    END
  END di0[72]
  PIN di0[73]
    DIRECTION INPUT ;
    USE SIGNAL ;
    PORT
      LAYER M5 ;
        RECT  6 0 6.024 0.192 ;
    END
  END di0[73]
  PIN di0[74]
    DIRECTION INPUT ;
    USE SIGNAL ;
    PORT
      LAYER M5 ;
        RECT  6.048 0 6.072 0.192 ;
    END
  END di0[74]
  PIN di0[75]
    DIRECTION INPUT ;
    USE SIGNAL ;
    PORT
      LAYER M5 ;
        RECT  6.096 0 6.12 0.192 ;
    END
  END di0[75]
  PIN di0[76]
    DIRECTION INPUT ;
    USE SIGNAL ;
    PORT
      LAYER M5 ;
        RECT  6.144 0 6.168 0.192 ;
    END
  END di0[76]
  PIN di0[77]
    DIRECTION INPUT ;
    USE SIGNAL ;
    PORT
      LAYER M5 ;
        RECT  6.192 0 6.216 0.192 ;
    END
  END di0[77]
  PIN di0[78]
    DIRECTION INPUT ;
    USE SIGNAL ;
    PORT
      LAYER M5 ;
        RECT  6.24 0 6.264 0.192 ;
    END
  END di0[78]
  PIN di0[79]
    DIRECTION INPUT ;
    USE SIGNAL ;
    PORT
      LAYER M5 ;
        RECT  6.288 0 6.312 0.192 ;
    END
  END di0[79]
  PIN di0[7]
    DIRECTION INPUT ;
    USE SIGNAL ;
    PORT
      LAYER M5 ;
        RECT  2.832 0 2.856 0.192 ;
    END
  END di0[7]
  PIN di0[80]
    DIRECTION INPUT ;
    USE SIGNAL ;
    PORT
      LAYER M5 ;
        RECT  6.336 0 6.36 0.192 ;
    END
  END di0[80]
  PIN di0[81]
    DIRECTION INPUT ;
    USE SIGNAL ;
    PORT
      LAYER M5 ;
        RECT  6.384 0 6.408 0.192 ;
    END
  END di0[81]
  PIN di0[82]
    DIRECTION INPUT ;
    USE SIGNAL ;
    PORT
      LAYER M5 ;
        RECT  6.432 0 6.456 0.192 ;
    END
  END di0[82]
  PIN di0[83]
    DIRECTION INPUT ;
    USE SIGNAL ;
    PORT
      LAYER M5 ;
        RECT  6.48 0 6.504 0.192 ;
    END
  END di0[83]
  PIN di0[84]
    DIRECTION INPUT ;
    USE SIGNAL ;
    PORT
      LAYER M5 ;
        RECT  6.528 0 6.552 0.192 ;
    END
  END di0[84]
  PIN di0[85]
    DIRECTION INPUT ;
    USE SIGNAL ;
    PORT
      LAYER M5 ;
        RECT  6.576 0 6.6 0.192 ;
    END
  END di0[85]
  PIN di0[86]
    DIRECTION INPUT ;
    USE SIGNAL ;
    PORT
      LAYER M5 ;
        RECT  6.624 0 6.648 0.192 ;
    END
  END di0[86]
  PIN di0[87]
    DIRECTION INPUT ;
    USE SIGNAL ;
    PORT
      LAYER M5 ;
        RECT  6.672 0 6.696 0.192 ;
    END
  END di0[87]
  PIN di0[88]
    DIRECTION INPUT ;
    USE SIGNAL ;
    PORT
      LAYER M5 ;
        RECT  6.72 0 6.744 0.192 ;
    END
  END di0[88]
  PIN di0[89]
    DIRECTION INPUT ;
    USE SIGNAL ;
    PORT
      LAYER M5 ;
        RECT  6.768 0 6.792 0.192 ;
    END
  END di0[89]
  PIN di0[8]
    DIRECTION INPUT ;
    USE SIGNAL ;
    PORT
      LAYER M5 ;
        RECT  2.88 0 2.904 0.192 ;
    END
  END di0[8]
  PIN di0[90]
    DIRECTION INPUT ;
    USE SIGNAL ;
    PORT
      LAYER M5 ;
        RECT  6.816 0 6.84 0.192 ;
    END
  END di0[90]
  PIN di0[91]
    DIRECTION INPUT ;
    USE SIGNAL ;
    PORT
      LAYER M5 ;
        RECT  6.864 0 6.888 0.192 ;
    END
  END di0[91]
  PIN di0[92]
    DIRECTION INPUT ;
    USE SIGNAL ;
    PORT
      LAYER M5 ;
        RECT  6.912 0 6.936 0.192 ;
    END
  END di0[92]
  PIN di0[93]
    DIRECTION INPUT ;
    USE SIGNAL ;
    PORT
      LAYER M5 ;
        RECT  6.96 0 6.984 0.192 ;
    END
  END di0[93]
  PIN di0[94]
    DIRECTION INPUT ;
    USE SIGNAL ;
    PORT
      LAYER M5 ;
        RECT  7.008 0 7.032 0.192 ;
    END
  END di0[94]
  PIN di0[95]
    DIRECTION INPUT ;
    USE SIGNAL ;
    PORT
      LAYER M5 ;
        RECT  7.056 0 7.08 0.192 ;
    END
  END di0[95]
  PIN di0[96]
    DIRECTION INPUT ;
    USE SIGNAL ;
    PORT
      LAYER M5 ;
        RECT  7.104 0 7.128 0.192 ;
    END
  END di0[96]
  PIN di0[97]
    DIRECTION INPUT ;
    USE SIGNAL ;
    PORT
      LAYER M5 ;
        RECT  7.152 0 7.176 0.192 ;
    END
  END di0[97]
  PIN di0[98]
    DIRECTION INPUT ;
    USE SIGNAL ;
    PORT
      LAYER M5 ;
        RECT  7.2 0 7.224 0.192 ;
    END
  END di0[98]
  PIN di0[99]
    DIRECTION INPUT ;
    USE SIGNAL ;
    PORT
      LAYER M5 ;
        RECT  7.248 0 7.272 0.192 ;
    END
  END di0[99]
  PIN di0[9]
    DIRECTION INPUT ;
    USE SIGNAL ;
    PORT
      LAYER M5 ;
        RECT  2.928 0 2.952 0.192 ;
    END
  END di0[9]
  PIN do0[0]
    DIRECTION OUTPUT ;
    USE SIGNAL ;
    PORT
      LAYER M5 ;
        RECT  2.496 17.064 2.52 17.256 ;
    END
  END do0[0]
  PIN do0[100]
    DIRECTION OUTPUT ;
    USE SIGNAL ;
    PORT
      LAYER M5 ;
        RECT  7.296 17.064 7.32 17.256 ;
    END
  END do0[100]
  PIN do0[101]
    DIRECTION OUTPUT ;
    USE SIGNAL ;
    PORT
      LAYER M5 ;
        RECT  7.344 17.064 7.368 17.256 ;
    END
  END do0[101]
  PIN do0[102]
    DIRECTION OUTPUT ;
    USE SIGNAL ;
    PORT
      LAYER M5 ;
        RECT  7.392 17.064 7.416 17.256 ;
    END
  END do0[102]
  PIN do0[103]
    DIRECTION OUTPUT ;
    USE SIGNAL ;
    PORT
      LAYER M5 ;
        RECT  7.44 17.064 7.464 17.256 ;
    END
  END do0[103]
  PIN do0[104]
    DIRECTION OUTPUT ;
    USE SIGNAL ;
    PORT
      LAYER M5 ;
        RECT  7.488 17.064 7.512 17.256 ;
    END
  END do0[104]
  PIN do0[105]
    DIRECTION OUTPUT ;
    USE SIGNAL ;
    PORT
      LAYER M5 ;
        RECT  7.536 17.064 7.56 17.256 ;
    END
  END do0[105]
  PIN do0[106]
    DIRECTION OUTPUT ;
    USE SIGNAL ;
    PORT
      LAYER M5 ;
        RECT  7.584 17.064 7.608 17.256 ;
    END
  END do0[106]
  PIN do0[107]
    DIRECTION OUTPUT ;
    USE SIGNAL ;
    PORT
      LAYER M5 ;
        RECT  7.632 17.064 7.656 17.256 ;
    END
  END do0[107]
  PIN do0[108]
    DIRECTION OUTPUT ;
    USE SIGNAL ;
    PORT
      LAYER M5 ;
        RECT  7.68 17.064 7.704 17.256 ;
    END
  END do0[108]
  PIN do0[109]
    DIRECTION OUTPUT ;
    USE SIGNAL ;
    PORT
      LAYER M5 ;
        RECT  7.728 17.064 7.752 17.256 ;
    END
  END do0[109]
  PIN do0[10]
    DIRECTION OUTPUT ;
    USE SIGNAL ;
    PORT
      LAYER M5 ;
        RECT  2.976 17.064 3 17.256 ;
    END
  END do0[10]
  PIN do0[110]
    DIRECTION OUTPUT ;
    USE SIGNAL ;
    PORT
      LAYER M5 ;
        RECT  7.776 17.064 7.8 17.256 ;
    END
  END do0[110]
  PIN do0[111]
    DIRECTION OUTPUT ;
    USE SIGNAL ;
    PORT
      LAYER M5 ;
        RECT  7.824 17.064 7.848 17.256 ;
    END
  END do0[111]
  PIN do0[112]
    DIRECTION OUTPUT ;
    USE SIGNAL ;
    PORT
      LAYER M5 ;
        RECT  7.872 17.064 7.896 17.256 ;
    END
  END do0[112]
  PIN do0[113]
    DIRECTION OUTPUT ;
    USE SIGNAL ;
    PORT
      LAYER M5 ;
        RECT  7.92 17.064 7.944 17.256 ;
    END
  END do0[113]
  PIN do0[114]
    DIRECTION OUTPUT ;
    USE SIGNAL ;
    PORT
      LAYER M5 ;
        RECT  7.968 17.064 7.992 17.256 ;
    END
  END do0[114]
  PIN do0[115]
    DIRECTION OUTPUT ;
    USE SIGNAL ;
    PORT
      LAYER M5 ;
        RECT  8.016 17.064 8.04 17.256 ;
    END
  END do0[115]
  PIN do0[116]
    DIRECTION OUTPUT ;
    USE SIGNAL ;
    PORT
      LAYER M5 ;
        RECT  8.064 17.064 8.088 17.256 ;
    END
  END do0[116]
  PIN do0[117]
    DIRECTION OUTPUT ;
    USE SIGNAL ;
    PORT
      LAYER M5 ;
        RECT  8.112 17.064 8.136 17.256 ;
    END
  END do0[117]
  PIN do0[118]
    DIRECTION OUTPUT ;
    USE SIGNAL ;
    PORT
      LAYER M5 ;
        RECT  8.16 17.064 8.184 17.256 ;
    END
  END do0[118]
  PIN do0[119]
    DIRECTION OUTPUT ;
    USE SIGNAL ;
    PORT
      LAYER M5 ;
        RECT  8.208 17.064 8.232 17.256 ;
    END
  END do0[119]
  PIN do0[11]
    DIRECTION OUTPUT ;
    USE SIGNAL ;
    PORT
      LAYER M5 ;
        RECT  3.024 17.064 3.048 17.256 ;
    END
  END do0[11]
  PIN do0[120]
    DIRECTION OUTPUT ;
    USE SIGNAL ;
    PORT
      LAYER M5 ;
        RECT  8.256 17.064 8.28 17.256 ;
    END
  END do0[120]
  PIN do0[121]
    DIRECTION OUTPUT ;
    USE SIGNAL ;
    PORT
      LAYER M5 ;
        RECT  8.304 17.064 8.328 17.256 ;
    END
  END do0[121]
  PIN do0[122]
    DIRECTION OUTPUT ;
    USE SIGNAL ;
    PORT
      LAYER M5 ;
        RECT  8.352 17.064 8.376 17.256 ;
    END
  END do0[122]
  PIN do0[123]
    DIRECTION OUTPUT ;
    USE SIGNAL ;
    PORT
      LAYER M5 ;
        RECT  8.4 17.064 8.424 17.256 ;
    END
  END do0[123]
  PIN do0[124]
    DIRECTION OUTPUT ;
    USE SIGNAL ;
    PORT
      LAYER M5 ;
        RECT  8.448 17.064 8.472 17.256 ;
    END
  END do0[124]
  PIN do0[125]
    DIRECTION OUTPUT ;
    USE SIGNAL ;
    PORT
      LAYER M5 ;
        RECT  8.496 17.064 8.52 17.256 ;
    END
  END do0[125]
  PIN do0[126]
    DIRECTION OUTPUT ;
    USE SIGNAL ;
    PORT
      LAYER M5 ;
        RECT  8.544 17.064 8.568 17.256 ;
    END
  END do0[126]
  PIN do0[127]
    DIRECTION OUTPUT ;
    USE SIGNAL ;
    PORT
      LAYER M5 ;
        RECT  8.592 17.064 8.616 17.256 ;
    END
  END do0[127]
  PIN do0[128]
    DIRECTION OUTPUT ;
    USE SIGNAL ;
    PORT
      LAYER M5 ;
        RECT  8.64 17.064 8.664 17.256 ;
    END
  END do0[128]
  PIN do0[129]
    DIRECTION OUTPUT ;
    USE SIGNAL ;
    PORT
      LAYER M5 ;
        RECT  8.688 17.064 8.712 17.256 ;
    END
  END do0[129]
  PIN do0[12]
    DIRECTION OUTPUT ;
    USE SIGNAL ;
    PORT
      LAYER M5 ;
        RECT  3.072 17.064 3.096 17.256 ;
    END
  END do0[12]
  PIN do0[130]
    DIRECTION OUTPUT ;
    USE SIGNAL ;
    PORT
      LAYER M5 ;
        RECT  8.736 17.064 8.76 17.256 ;
    END
  END do0[130]
  PIN do0[131]
    DIRECTION OUTPUT ;
    USE SIGNAL ;
    PORT
      LAYER M5 ;
        RECT  8.784 17.064 8.808 17.256 ;
    END
  END do0[131]
  PIN do0[132]
    DIRECTION OUTPUT ;
    USE SIGNAL ;
    PORT
      LAYER M5 ;
        RECT  8.832 17.064 8.856 17.256 ;
    END
  END do0[132]
  PIN do0[133]
    DIRECTION OUTPUT ;
    USE SIGNAL ;
    PORT
      LAYER M5 ;
        RECT  8.88 17.064 8.904 17.256 ;
    END
  END do0[133]
  PIN do0[134]
    DIRECTION OUTPUT ;
    USE SIGNAL ;
    PORT
      LAYER M5 ;
        RECT  8.928 17.064 8.952 17.256 ;
    END
  END do0[134]
  PIN do0[135]
    DIRECTION OUTPUT ;
    USE SIGNAL ;
    PORT
      LAYER M5 ;
        RECT  8.976 17.064 9 17.256 ;
    END
  END do0[135]
  PIN do0[136]
    DIRECTION OUTPUT ;
    USE SIGNAL ;
    PORT
      LAYER M5 ;
        RECT  9.024 17.064 9.048 17.256 ;
    END
  END do0[136]
  PIN do0[137]
    DIRECTION OUTPUT ;
    USE SIGNAL ;
    PORT
      LAYER M5 ;
        RECT  9.072 17.064 9.096 17.256 ;
    END
  END do0[137]
  PIN do0[138]
    DIRECTION OUTPUT ;
    USE SIGNAL ;
    PORT
      LAYER M5 ;
        RECT  9.12 17.064 9.144 17.256 ;
    END
  END do0[138]
  PIN do0[139]
    DIRECTION OUTPUT ;
    USE SIGNAL ;
    PORT
      LAYER M5 ;
        RECT  9.168 17.064 9.192 17.256 ;
    END
  END do0[139]
  PIN do0[13]
    DIRECTION OUTPUT ;
    USE SIGNAL ;
    PORT
      LAYER M5 ;
        RECT  3.12 17.064 3.144 17.256 ;
    END
  END do0[13]
  PIN do0[140]
    DIRECTION OUTPUT ;
    USE SIGNAL ;
    PORT
      LAYER M5 ;
        RECT  9.216 17.064 9.24 17.256 ;
    END
  END do0[140]
  PIN do0[141]
    DIRECTION OUTPUT ;
    USE SIGNAL ;
    PORT
      LAYER M5 ;
        RECT  9.264 17.064 9.288 17.256 ;
    END
  END do0[141]
  PIN do0[142]
    DIRECTION OUTPUT ;
    USE SIGNAL ;
    PORT
      LAYER M5 ;
        RECT  9.312 17.064 9.336 17.256 ;
    END
  END do0[142]
  PIN do0[143]
    DIRECTION OUTPUT ;
    USE SIGNAL ;
    PORT
      LAYER M5 ;
        RECT  9.36 17.064 9.384 17.256 ;
    END
  END do0[143]
  PIN do0[144]
    DIRECTION OUTPUT ;
    USE SIGNAL ;
    PORT
      LAYER M5 ;
        RECT  9.408 17.064 9.432 17.256 ;
    END
  END do0[144]
  PIN do0[145]
    DIRECTION OUTPUT ;
    USE SIGNAL ;
    PORT
      LAYER M5 ;
        RECT  9.456 17.064 9.48 17.256 ;
    END
  END do0[145]
  PIN do0[146]
    DIRECTION OUTPUT ;
    USE SIGNAL ;
    PORT
      LAYER M5 ;
        RECT  9.504 17.064 9.528 17.256 ;
    END
  END do0[146]
  PIN do0[147]
    DIRECTION OUTPUT ;
    USE SIGNAL ;
    PORT
      LAYER M5 ;
        RECT  9.552 17.064 9.576 17.256 ;
    END
  END do0[147]
  PIN do0[148]
    DIRECTION OUTPUT ;
    USE SIGNAL ;
    PORT
      LAYER M5 ;
        RECT  9.6 17.064 9.624 17.256 ;
    END
  END do0[148]
  PIN do0[149]
    DIRECTION OUTPUT ;
    USE SIGNAL ;
    PORT
      LAYER M5 ;
        RECT  9.648 17.064 9.672 17.256 ;
    END
  END do0[149]
  PIN do0[14]
    DIRECTION OUTPUT ;
    USE SIGNAL ;
    PORT
      LAYER M5 ;
        RECT  3.168 17.064 3.192 17.256 ;
    END
  END do0[14]
  PIN do0[150]
    DIRECTION OUTPUT ;
    USE SIGNAL ;
    PORT
      LAYER M5 ;
        RECT  9.696 17.064 9.72 17.256 ;
    END
  END do0[150]
  PIN do0[151]
    DIRECTION OUTPUT ;
    USE SIGNAL ;
    PORT
      LAYER M5 ;
        RECT  9.744 17.064 9.768 17.256 ;
    END
  END do0[151]
  PIN do0[152]
    DIRECTION OUTPUT ;
    USE SIGNAL ;
    PORT
      LAYER M5 ;
        RECT  9.792 17.064 9.816 17.256 ;
    END
  END do0[152]
  PIN do0[153]
    DIRECTION OUTPUT ;
    USE SIGNAL ;
    PORT
      LAYER M5 ;
        RECT  9.84 17.064 9.864 17.256 ;
    END
  END do0[153]
  PIN do0[154]
    DIRECTION OUTPUT ;
    USE SIGNAL ;
    PORT
      LAYER M5 ;
        RECT  9.888 17.064 9.912 17.256 ;
    END
  END do0[154]
  PIN do0[155]
    DIRECTION OUTPUT ;
    USE SIGNAL ;
    PORT
      LAYER M5 ;
        RECT  9.936 17.064 9.96 17.256 ;
    END
  END do0[155]
  PIN do0[156]
    DIRECTION OUTPUT ;
    USE SIGNAL ;
    PORT
      LAYER M5 ;
        RECT  9.984 17.064 10.008 17.256 ;
    END
  END do0[156]
  PIN do0[157]
    DIRECTION OUTPUT ;
    USE SIGNAL ;
    PORT
      LAYER M5 ;
        RECT  10.032 17.064 10.056 17.256 ;
    END
  END do0[157]
  PIN do0[158]
    DIRECTION OUTPUT ;
    USE SIGNAL ;
    PORT
      LAYER M5 ;
        RECT  10.08 17.064 10.104 17.256 ;
    END
  END do0[158]
  PIN do0[159]
    DIRECTION OUTPUT ;
    USE SIGNAL ;
    PORT
      LAYER M5 ;
        RECT  10.128 17.064 10.152 17.256 ;
    END
  END do0[159]
  PIN do0[15]
    DIRECTION OUTPUT ;
    USE SIGNAL ;
    PORT
      LAYER M5 ;
        RECT  3.216 17.064 3.24 17.256 ;
    END
  END do0[15]
  PIN do0[160]
    DIRECTION OUTPUT ;
    USE SIGNAL ;
    PORT
      LAYER M5 ;
        RECT  10.176 17.064 10.2 17.256 ;
    END
  END do0[160]
  PIN do0[161]
    DIRECTION OUTPUT ;
    USE SIGNAL ;
    PORT
      LAYER M5 ;
        RECT  10.224 17.064 10.248 17.256 ;
    END
  END do0[161]
  PIN do0[162]
    DIRECTION OUTPUT ;
    USE SIGNAL ;
    PORT
      LAYER M5 ;
        RECT  10.272 17.064 10.296 17.256 ;
    END
  END do0[162]
  PIN do0[163]
    DIRECTION OUTPUT ;
    USE SIGNAL ;
    PORT
      LAYER M5 ;
        RECT  10.32 17.064 10.344 17.256 ;
    END
  END do0[163]
  PIN do0[164]
    DIRECTION OUTPUT ;
    USE SIGNAL ;
    PORT
      LAYER M5 ;
        RECT  10.368 17.064 10.392 17.256 ;
    END
  END do0[164]
  PIN do0[165]
    DIRECTION OUTPUT ;
    USE SIGNAL ;
    PORT
      LAYER M5 ;
        RECT  10.416 17.064 10.44 17.256 ;
    END
  END do0[165]
  PIN do0[166]
    DIRECTION OUTPUT ;
    USE SIGNAL ;
    PORT
      LAYER M5 ;
        RECT  10.464 17.064 10.488 17.256 ;
    END
  END do0[166]
  PIN do0[167]
    DIRECTION OUTPUT ;
    USE SIGNAL ;
    PORT
      LAYER M5 ;
        RECT  10.512 17.064 10.536 17.256 ;
    END
  END do0[167]
  PIN do0[168]
    DIRECTION OUTPUT ;
    USE SIGNAL ;
    PORT
      LAYER M5 ;
        RECT  10.56 17.064 10.584 17.256 ;
    END
  END do0[168]
  PIN do0[169]
    DIRECTION OUTPUT ;
    USE SIGNAL ;
    PORT
      LAYER M5 ;
        RECT  10.608 17.064 10.632 17.256 ;
    END
  END do0[169]
  PIN do0[16]
    DIRECTION OUTPUT ;
    USE SIGNAL ;
    PORT
      LAYER M5 ;
        RECT  3.264 17.064 3.288 17.256 ;
    END
  END do0[16]
  PIN do0[170]
    DIRECTION OUTPUT ;
    USE SIGNAL ;
    PORT
      LAYER M5 ;
        RECT  10.656 17.064 10.68 17.256 ;
    END
  END do0[170]
  PIN do0[171]
    DIRECTION OUTPUT ;
    USE SIGNAL ;
    PORT
      LAYER M5 ;
        RECT  10.704 17.064 10.728 17.256 ;
    END
  END do0[171]
  PIN do0[172]
    DIRECTION OUTPUT ;
    USE SIGNAL ;
    PORT
      LAYER M5 ;
        RECT  10.752 17.064 10.776 17.256 ;
    END
  END do0[172]
  PIN do0[173]
    DIRECTION OUTPUT ;
    USE SIGNAL ;
    PORT
      LAYER M5 ;
        RECT  10.8 17.064 10.824 17.256 ;
    END
  END do0[173]
  PIN do0[174]
    DIRECTION OUTPUT ;
    USE SIGNAL ;
    PORT
      LAYER M5 ;
        RECT  10.848 17.064 10.872 17.256 ;
    END
  END do0[174]
  PIN do0[175]
    DIRECTION OUTPUT ;
    USE SIGNAL ;
    PORT
      LAYER M5 ;
        RECT  10.896 17.064 10.92 17.256 ;
    END
  END do0[175]
  PIN do0[176]
    DIRECTION OUTPUT ;
    USE SIGNAL ;
    PORT
      LAYER M5 ;
        RECT  10.944 17.064 10.968 17.256 ;
    END
  END do0[176]
  PIN do0[177]
    DIRECTION OUTPUT ;
    USE SIGNAL ;
    PORT
      LAYER M5 ;
        RECT  10.992 17.064 11.016 17.256 ;
    END
  END do0[177]
  PIN do0[178]
    DIRECTION OUTPUT ;
    USE SIGNAL ;
    PORT
      LAYER M5 ;
        RECT  11.04 17.064 11.064 17.256 ;
    END
  END do0[178]
  PIN do0[179]
    DIRECTION OUTPUT ;
    USE SIGNAL ;
    PORT
      LAYER M5 ;
        RECT  11.088 17.064 11.112 17.256 ;
    END
  END do0[179]
  PIN do0[17]
    DIRECTION OUTPUT ;
    USE SIGNAL ;
    PORT
      LAYER M5 ;
        RECT  3.312 17.064 3.336 17.256 ;
    END
  END do0[17]
  PIN do0[180]
    DIRECTION OUTPUT ;
    USE SIGNAL ;
    PORT
      LAYER M5 ;
        RECT  11.136 17.064 11.16 17.256 ;
    END
  END do0[180]
  PIN do0[181]
    DIRECTION OUTPUT ;
    USE SIGNAL ;
    PORT
      LAYER M5 ;
        RECT  11.184 17.064 11.208 17.256 ;
    END
  END do0[181]
  PIN do0[182]
    DIRECTION OUTPUT ;
    USE SIGNAL ;
    PORT
      LAYER M5 ;
        RECT  11.232 17.064 11.256 17.256 ;
    END
  END do0[182]
  PIN do0[183]
    DIRECTION OUTPUT ;
    USE SIGNAL ;
    PORT
      LAYER M5 ;
        RECT  11.28 17.064 11.304 17.256 ;
    END
  END do0[183]
  PIN do0[184]
    DIRECTION OUTPUT ;
    USE SIGNAL ;
    PORT
      LAYER M5 ;
        RECT  11.328 17.064 11.352 17.256 ;
    END
  END do0[184]
  PIN do0[185]
    DIRECTION OUTPUT ;
    USE SIGNAL ;
    PORT
      LAYER M5 ;
        RECT  11.376 17.064 11.4 17.256 ;
    END
  END do0[185]
  PIN do0[186]
    DIRECTION OUTPUT ;
    USE SIGNAL ;
    PORT
      LAYER M5 ;
        RECT  11.424 17.064 11.448 17.256 ;
    END
  END do0[186]
  PIN do0[187]
    DIRECTION OUTPUT ;
    USE SIGNAL ;
    PORT
      LAYER M5 ;
        RECT  11.472 17.064 11.496 17.256 ;
    END
  END do0[187]
  PIN do0[188]
    DIRECTION OUTPUT ;
    USE SIGNAL ;
    PORT
      LAYER M5 ;
        RECT  11.52 17.064 11.544 17.256 ;
    END
  END do0[188]
  PIN do0[189]
    DIRECTION OUTPUT ;
    USE SIGNAL ;
    PORT
      LAYER M5 ;
        RECT  11.568 17.064 11.592 17.256 ;
    END
  END do0[189]
  PIN do0[18]
    DIRECTION OUTPUT ;
    USE SIGNAL ;
    PORT
      LAYER M5 ;
        RECT  3.36 17.064 3.384 17.256 ;
    END
  END do0[18]
  PIN do0[190]
    DIRECTION OUTPUT ;
    USE SIGNAL ;
    PORT
      LAYER M5 ;
        RECT  11.616 17.064 11.64 17.256 ;
    END
  END do0[190]
  PIN do0[191]
    DIRECTION OUTPUT ;
    USE SIGNAL ;
    PORT
      LAYER M5 ;
        RECT  11.664 17.064 11.688 17.256 ;
    END
  END do0[191]
  PIN do0[192]
    DIRECTION OUTPUT ;
    USE SIGNAL ;
    PORT
      LAYER M5 ;
        RECT  11.712 17.064 11.736 17.256 ;
    END
  END do0[192]
  PIN do0[193]
    DIRECTION OUTPUT ;
    USE SIGNAL ;
    PORT
      LAYER M5 ;
        RECT  11.76 17.064 11.784 17.256 ;
    END
  END do0[193]
  PIN do0[194]
    DIRECTION OUTPUT ;
    USE SIGNAL ;
    PORT
      LAYER M5 ;
        RECT  11.808 17.064 11.832 17.256 ;
    END
  END do0[194]
  PIN do0[195]
    DIRECTION OUTPUT ;
    USE SIGNAL ;
    PORT
      LAYER M5 ;
        RECT  11.856 17.064 11.88 17.256 ;
    END
  END do0[195]
  PIN do0[196]
    DIRECTION OUTPUT ;
    USE SIGNAL ;
    PORT
      LAYER M5 ;
        RECT  11.904 17.064 11.928 17.256 ;
    END
  END do0[196]
  PIN do0[197]
    DIRECTION OUTPUT ;
    USE SIGNAL ;
    PORT
      LAYER M5 ;
        RECT  11.952 17.064 11.976 17.256 ;
    END
  END do0[197]
  PIN do0[198]
    DIRECTION OUTPUT ;
    USE SIGNAL ;
    PORT
      LAYER M5 ;
        RECT  12 17.064 12.024 17.256 ;
    END
  END do0[198]
  PIN do0[199]
    DIRECTION OUTPUT ;
    USE SIGNAL ;
    PORT
      LAYER M5 ;
        RECT  12.048 17.064 12.072 17.256 ;
    END
  END do0[199]
  PIN do0[19]
    DIRECTION OUTPUT ;
    USE SIGNAL ;
    PORT
      LAYER M5 ;
        RECT  3.408 17.064 3.432 17.256 ;
    END
  END do0[19]
  PIN do0[1]
    DIRECTION OUTPUT ;
    USE SIGNAL ;
    PORT
      LAYER M5 ;
        RECT  2.544 17.064 2.568 17.256 ;
    END
  END do0[1]
  PIN do0[200]
    DIRECTION OUTPUT ;
    USE SIGNAL ;
    PORT
      LAYER M5 ;
        RECT  12.096 17.064 12.12 17.256 ;
    END
  END do0[200]
  PIN do0[201]
    DIRECTION OUTPUT ;
    USE SIGNAL ;
    PORT
      LAYER M5 ;
        RECT  12.144 17.064 12.168 17.256 ;
    END
  END do0[201]
  PIN do0[202]
    DIRECTION OUTPUT ;
    USE SIGNAL ;
    PORT
      LAYER M5 ;
        RECT  12.192 17.064 12.216 17.256 ;
    END
  END do0[202]
  PIN do0[203]
    DIRECTION OUTPUT ;
    USE SIGNAL ;
    PORT
      LAYER M5 ;
        RECT  12.24 17.064 12.264 17.256 ;
    END
  END do0[203]
  PIN do0[204]
    DIRECTION OUTPUT ;
    USE SIGNAL ;
    PORT
      LAYER M5 ;
        RECT  12.288 17.064 12.312 17.256 ;
    END
  END do0[204]
  PIN do0[205]
    DIRECTION OUTPUT ;
    USE SIGNAL ;
    PORT
      LAYER M5 ;
        RECT  12.336 17.064 12.36 17.256 ;
    END
  END do0[205]
  PIN do0[206]
    DIRECTION OUTPUT ;
    USE SIGNAL ;
    PORT
      LAYER M5 ;
        RECT  12.384 17.064 12.408 17.256 ;
    END
  END do0[206]
  PIN do0[207]
    DIRECTION OUTPUT ;
    USE SIGNAL ;
    PORT
      LAYER M5 ;
        RECT  12.432 17.064 12.456 17.256 ;
    END
  END do0[207]
  PIN do0[208]
    DIRECTION OUTPUT ;
    USE SIGNAL ;
    PORT
      LAYER M5 ;
        RECT  12.48 17.064 12.504 17.256 ;
    END
  END do0[208]
  PIN do0[209]
    DIRECTION OUTPUT ;
    USE SIGNAL ;
    PORT
      LAYER M5 ;
        RECT  12.528 17.064 12.552 17.256 ;
    END
  END do0[209]
  PIN do0[20]
    DIRECTION OUTPUT ;
    USE SIGNAL ;
    PORT
      LAYER M5 ;
        RECT  3.456 17.064 3.48 17.256 ;
    END
  END do0[20]
  PIN do0[210]
    DIRECTION OUTPUT ;
    USE SIGNAL ;
    PORT
      LAYER M5 ;
        RECT  12.576 17.064 12.6 17.256 ;
    END
  END do0[210]
  PIN do0[211]
    DIRECTION OUTPUT ;
    USE SIGNAL ;
    PORT
      LAYER M5 ;
        RECT  12.624 17.064 12.648 17.256 ;
    END
  END do0[211]
  PIN do0[212]
    DIRECTION OUTPUT ;
    USE SIGNAL ;
    PORT
      LAYER M5 ;
        RECT  12.672 17.064 12.696 17.256 ;
    END
  END do0[212]
  PIN do0[213]
    DIRECTION OUTPUT ;
    USE SIGNAL ;
    PORT
      LAYER M5 ;
        RECT  12.72 17.064 12.744 17.256 ;
    END
  END do0[213]
  PIN do0[214]
    DIRECTION OUTPUT ;
    USE SIGNAL ;
    PORT
      LAYER M5 ;
        RECT  12.768 17.064 12.792 17.256 ;
    END
  END do0[214]
  PIN do0[215]
    DIRECTION OUTPUT ;
    USE SIGNAL ;
    PORT
      LAYER M5 ;
        RECT  12.816 17.064 12.84 17.256 ;
    END
  END do0[215]
  PIN do0[216]
    DIRECTION OUTPUT ;
    USE SIGNAL ;
    PORT
      LAYER M5 ;
        RECT  12.864 17.064 12.888 17.256 ;
    END
  END do0[216]
  PIN do0[217]
    DIRECTION OUTPUT ;
    USE SIGNAL ;
    PORT
      LAYER M5 ;
        RECT  12.912 17.064 12.936 17.256 ;
    END
  END do0[217]
  PIN do0[218]
    DIRECTION OUTPUT ;
    USE SIGNAL ;
    PORT
      LAYER M5 ;
        RECT  12.96 17.064 12.984 17.256 ;
    END
  END do0[218]
  PIN do0[219]
    DIRECTION OUTPUT ;
    USE SIGNAL ;
    PORT
      LAYER M5 ;
        RECT  13.008 17.064 13.032 17.256 ;
    END
  END do0[219]
  PIN do0[21]
    DIRECTION OUTPUT ;
    USE SIGNAL ;
    PORT
      LAYER M5 ;
        RECT  3.504 17.064 3.528 17.256 ;
    END
  END do0[21]
  PIN do0[220]
    DIRECTION OUTPUT ;
    USE SIGNAL ;
    PORT
      LAYER M5 ;
        RECT  13.056 17.064 13.08 17.256 ;
    END
  END do0[220]
  PIN do0[221]
    DIRECTION OUTPUT ;
    USE SIGNAL ;
    PORT
      LAYER M5 ;
        RECT  13.104 17.064 13.128 17.256 ;
    END
  END do0[221]
  PIN do0[222]
    DIRECTION OUTPUT ;
    USE SIGNAL ;
    PORT
      LAYER M5 ;
        RECT  13.152 17.064 13.176 17.256 ;
    END
  END do0[222]
  PIN do0[223]
    DIRECTION OUTPUT ;
    USE SIGNAL ;
    PORT
      LAYER M5 ;
        RECT  13.2 17.064 13.224 17.256 ;
    END
  END do0[223]
  PIN do0[224]
    DIRECTION OUTPUT ;
    USE SIGNAL ;
    PORT
      LAYER M5 ;
        RECT  13.248 17.064 13.272 17.256 ;
    END
  END do0[224]
  PIN do0[225]
    DIRECTION OUTPUT ;
    USE SIGNAL ;
    PORT
      LAYER M5 ;
        RECT  13.296 17.064 13.32 17.256 ;
    END
  END do0[225]
  PIN do0[226]
    DIRECTION OUTPUT ;
    USE SIGNAL ;
    PORT
      LAYER M5 ;
        RECT  13.344 17.064 13.368 17.256 ;
    END
  END do0[226]
  PIN do0[227]
    DIRECTION OUTPUT ;
    USE SIGNAL ;
    PORT
      LAYER M5 ;
        RECT  13.392 17.064 13.416 17.256 ;
    END
  END do0[227]
  PIN do0[228]
    DIRECTION OUTPUT ;
    USE SIGNAL ;
    PORT
      LAYER M5 ;
        RECT  13.44 17.064 13.464 17.256 ;
    END
  END do0[228]
  PIN do0[229]
    DIRECTION OUTPUT ;
    USE SIGNAL ;
    PORT
      LAYER M5 ;
        RECT  13.488 17.064 13.512 17.256 ;
    END
  END do0[229]
  PIN do0[22]
    DIRECTION OUTPUT ;
    USE SIGNAL ;
    PORT
      LAYER M5 ;
        RECT  3.552 17.064 3.576 17.256 ;
    END
  END do0[22]
  PIN do0[230]
    DIRECTION OUTPUT ;
    USE SIGNAL ;
    PORT
      LAYER M5 ;
        RECT  13.536 17.064 13.56 17.256 ;
    END
  END do0[230]
  PIN do0[231]
    DIRECTION OUTPUT ;
    USE SIGNAL ;
    PORT
      LAYER M5 ;
        RECT  13.584 17.064 13.608 17.256 ;
    END
  END do0[231]
  PIN do0[232]
    DIRECTION OUTPUT ;
    USE SIGNAL ;
    PORT
      LAYER M5 ;
        RECT  13.632 17.064 13.656 17.256 ;
    END
  END do0[232]
  PIN do0[233]
    DIRECTION OUTPUT ;
    USE SIGNAL ;
    PORT
      LAYER M5 ;
        RECT  13.68 17.064 13.704 17.256 ;
    END
  END do0[233]
  PIN do0[234]
    DIRECTION OUTPUT ;
    USE SIGNAL ;
    PORT
      LAYER M5 ;
        RECT  13.728 17.064 13.752 17.256 ;
    END
  END do0[234]
  PIN do0[235]
    DIRECTION OUTPUT ;
    USE SIGNAL ;
    PORT
      LAYER M5 ;
        RECT  13.776 17.064 13.8 17.256 ;
    END
  END do0[235]
  PIN do0[236]
    DIRECTION OUTPUT ;
    USE SIGNAL ;
    PORT
      LAYER M5 ;
        RECT  13.824 17.064 13.848 17.256 ;
    END
  END do0[236]
  PIN do0[237]
    DIRECTION OUTPUT ;
    USE SIGNAL ;
    PORT
      LAYER M5 ;
        RECT  13.872 17.064 13.896 17.256 ;
    END
  END do0[237]
  PIN do0[238]
    DIRECTION OUTPUT ;
    USE SIGNAL ;
    PORT
      LAYER M5 ;
        RECT  13.92 17.064 13.944 17.256 ;
    END
  END do0[238]
  PIN do0[239]
    DIRECTION OUTPUT ;
    USE SIGNAL ;
    PORT
      LAYER M5 ;
        RECT  13.968 17.064 13.992 17.256 ;
    END
  END do0[239]
  PIN do0[23]
    DIRECTION OUTPUT ;
    USE SIGNAL ;
    PORT
      LAYER M5 ;
        RECT  3.6 17.064 3.624 17.256 ;
    END
  END do0[23]
  PIN do0[240]
    DIRECTION OUTPUT ;
    USE SIGNAL ;
    PORT
      LAYER M5 ;
        RECT  14.016 17.064 14.04 17.256 ;
    END
  END do0[240]
  PIN do0[241]
    DIRECTION OUTPUT ;
    USE SIGNAL ;
    PORT
      LAYER M5 ;
        RECT  14.064 17.064 14.088 17.256 ;
    END
  END do0[241]
  PIN do0[242]
    DIRECTION OUTPUT ;
    USE SIGNAL ;
    PORT
      LAYER M5 ;
        RECT  14.112 17.064 14.136 17.256 ;
    END
  END do0[242]
  PIN do0[243]
    DIRECTION OUTPUT ;
    USE SIGNAL ;
    PORT
      LAYER M5 ;
        RECT  14.16 17.064 14.184 17.256 ;
    END
  END do0[243]
  PIN do0[244]
    DIRECTION OUTPUT ;
    USE SIGNAL ;
    PORT
      LAYER M5 ;
        RECT  14.208 17.064 14.232 17.256 ;
    END
  END do0[244]
  PIN do0[245]
    DIRECTION OUTPUT ;
    USE SIGNAL ;
    PORT
      LAYER M5 ;
        RECT  14.256 17.064 14.28 17.256 ;
    END
  END do0[245]
  PIN do0[246]
    DIRECTION OUTPUT ;
    USE SIGNAL ;
    PORT
      LAYER M5 ;
        RECT  14.304 17.064 14.328 17.256 ;
    END
  END do0[246]
  PIN do0[247]
    DIRECTION OUTPUT ;
    USE SIGNAL ;
    PORT
      LAYER M5 ;
        RECT  14.352 17.064 14.376 17.256 ;
    END
  END do0[247]
  PIN do0[248]
    DIRECTION OUTPUT ;
    USE SIGNAL ;
    PORT
      LAYER M5 ;
        RECT  14.4 17.064 14.424 17.256 ;
    END
  END do0[248]
  PIN do0[249]
    DIRECTION OUTPUT ;
    USE SIGNAL ;
    PORT
      LAYER M5 ;
        RECT  14.448 17.064 14.472 17.256 ;
    END
  END do0[249]
  PIN do0[24]
    DIRECTION OUTPUT ;
    USE SIGNAL ;
    PORT
      LAYER M5 ;
        RECT  3.648 17.064 3.672 17.256 ;
    END
  END do0[24]
  PIN do0[250]
    DIRECTION OUTPUT ;
    USE SIGNAL ;
    PORT
      LAYER M5 ;
        RECT  14.496 17.064 14.52 17.256 ;
    END
  END do0[250]
  PIN do0[251]
    DIRECTION OUTPUT ;
    USE SIGNAL ;
    PORT
      LAYER M5 ;
        RECT  14.544 17.064 14.568 17.256 ;
    END
  END do0[251]
  PIN do0[252]
    DIRECTION OUTPUT ;
    USE SIGNAL ;
    PORT
      LAYER M5 ;
        RECT  14.592 17.064 14.616 17.256 ;
    END
  END do0[252]
  PIN do0[253]
    DIRECTION OUTPUT ;
    USE SIGNAL ;
    PORT
      LAYER M5 ;
        RECT  14.64 17.064 14.664 17.256 ;
    END
  END do0[253]
  PIN do0[254]
    DIRECTION OUTPUT ;
    USE SIGNAL ;
    PORT
      LAYER M5 ;
        RECT  14.688 17.064 14.712 17.256 ;
    END
  END do0[254]
  PIN do0[255]
    DIRECTION OUTPUT ;
    USE SIGNAL ;
    PORT
      LAYER M5 ;
        RECT  14.736 17.064 14.76 17.256 ;
    END
  END do0[255]
  PIN do0[256]
    DIRECTION OUTPUT ;
    USE SIGNAL ;
    PORT
      LAYER M5 ;
        RECT  14.784 17.064 14.808 17.256 ;
    END
  END do0[256]
  PIN do0[257]
    DIRECTION OUTPUT ;
    USE SIGNAL ;
    PORT
      LAYER M5 ;
        RECT  14.832 17.064 14.856 17.256 ;
    END
  END do0[257]
  PIN do0[258]
    DIRECTION OUTPUT ;
    USE SIGNAL ;
    PORT
      LAYER M5 ;
        RECT  14.88 17.064 14.904 17.256 ;
    END
  END do0[258]
  PIN do0[259]
    DIRECTION OUTPUT ;
    USE SIGNAL ;
    PORT
      LAYER M5 ;
        RECT  14.928 17.064 14.952 17.256 ;
    END
  END do0[259]
  PIN do0[25]
    DIRECTION OUTPUT ;
    USE SIGNAL ;
    PORT
      LAYER M5 ;
        RECT  3.696 17.064 3.72 17.256 ;
    END
  END do0[25]
  PIN do0[260]
    DIRECTION OUTPUT ;
    USE SIGNAL ;
    PORT
      LAYER M5 ;
        RECT  14.976 17.064 15 17.256 ;
    END
  END do0[260]
  PIN do0[261]
    DIRECTION OUTPUT ;
    USE SIGNAL ;
    PORT
      LAYER M5 ;
        RECT  15.024 17.064 15.048 17.256 ;
    END
  END do0[261]
  PIN do0[262]
    DIRECTION OUTPUT ;
    USE SIGNAL ;
    PORT
      LAYER M5 ;
        RECT  15.072 17.064 15.096 17.256 ;
    END
  END do0[262]
  PIN do0[263]
    DIRECTION OUTPUT ;
    USE SIGNAL ;
    PORT
      LAYER M5 ;
        RECT  15.12 17.064 15.144 17.256 ;
    END
  END do0[263]
  PIN do0[264]
    DIRECTION OUTPUT ;
    USE SIGNAL ;
    PORT
      LAYER M5 ;
        RECT  15.168 17.064 15.192 17.256 ;
    END
  END do0[264]
  PIN do0[265]
    DIRECTION OUTPUT ;
    USE SIGNAL ;
    PORT
      LAYER M5 ;
        RECT  15.216 17.064 15.24 17.256 ;
    END
  END do0[265]
  PIN do0[266]
    DIRECTION OUTPUT ;
    USE SIGNAL ;
    PORT
      LAYER M5 ;
        RECT  15.264 17.064 15.288 17.256 ;
    END
  END do0[266]
  PIN do0[267]
    DIRECTION OUTPUT ;
    USE SIGNAL ;
    PORT
      LAYER M5 ;
        RECT  15.312 17.064 15.336 17.256 ;
    END
  END do0[267]
  PIN do0[268]
    DIRECTION OUTPUT ;
    USE SIGNAL ;
    PORT
      LAYER M5 ;
        RECT  15.36 17.064 15.384 17.256 ;
    END
  END do0[268]
  PIN do0[269]
    DIRECTION OUTPUT ;
    USE SIGNAL ;
    PORT
      LAYER M5 ;
        RECT  15.408 17.064 15.432 17.256 ;
    END
  END do0[269]
  PIN do0[26]
    DIRECTION OUTPUT ;
    USE SIGNAL ;
    PORT
      LAYER M5 ;
        RECT  3.744 17.064 3.768 17.256 ;
    END
  END do0[26]
  PIN do0[270]
    DIRECTION OUTPUT ;
    USE SIGNAL ;
    PORT
      LAYER M5 ;
        RECT  15.456 17.064 15.48 17.256 ;
    END
  END do0[270]
  PIN do0[271]
    DIRECTION OUTPUT ;
    USE SIGNAL ;
    PORT
      LAYER M5 ;
        RECT  15.504 17.064 15.528 17.256 ;
    END
  END do0[271]
  PIN do0[272]
    DIRECTION OUTPUT ;
    USE SIGNAL ;
    PORT
      LAYER M5 ;
        RECT  15.552 17.064 15.576 17.256 ;
    END
  END do0[272]
  PIN do0[273]
    DIRECTION OUTPUT ;
    USE SIGNAL ;
    PORT
      LAYER M5 ;
        RECT  15.6 17.064 15.624 17.256 ;
    END
  END do0[273]
  PIN do0[274]
    DIRECTION OUTPUT ;
    USE SIGNAL ;
    PORT
      LAYER M5 ;
        RECT  15.648 17.064 15.672 17.256 ;
    END
  END do0[274]
  PIN do0[275]
    DIRECTION OUTPUT ;
    USE SIGNAL ;
    PORT
      LAYER M5 ;
        RECT  15.696 17.064 15.72 17.256 ;
    END
  END do0[275]
  PIN do0[276]
    DIRECTION OUTPUT ;
    USE SIGNAL ;
    PORT
      LAYER M5 ;
        RECT  15.744 17.064 15.768 17.256 ;
    END
  END do0[276]
  PIN do0[277]
    DIRECTION OUTPUT ;
    USE SIGNAL ;
    PORT
      LAYER M5 ;
        RECT  15.792 17.064 15.816 17.256 ;
    END
  END do0[277]
  PIN do0[278]
    DIRECTION OUTPUT ;
    USE SIGNAL ;
    PORT
      LAYER M5 ;
        RECT  15.84 17.064 15.864 17.256 ;
    END
  END do0[278]
  PIN do0[279]
    DIRECTION OUTPUT ;
    USE SIGNAL ;
    PORT
      LAYER M5 ;
        RECT  15.888 17.064 15.912 17.256 ;
    END
  END do0[279]
  PIN do0[27]
    DIRECTION OUTPUT ;
    USE SIGNAL ;
    PORT
      LAYER M5 ;
        RECT  3.792 17.064 3.816 17.256 ;
    END
  END do0[27]
  PIN do0[280]
    DIRECTION OUTPUT ;
    USE SIGNAL ;
    PORT
      LAYER M5 ;
        RECT  15.936 17.064 15.96 17.256 ;
    END
  END do0[280]
  PIN do0[281]
    DIRECTION OUTPUT ;
    USE SIGNAL ;
    PORT
      LAYER M5 ;
        RECT  15.984 17.064 16.008 17.256 ;
    END
  END do0[281]
  PIN do0[282]
    DIRECTION OUTPUT ;
    USE SIGNAL ;
    PORT
      LAYER M5 ;
        RECT  16.032 17.064 16.056 17.256 ;
    END
  END do0[282]
  PIN do0[283]
    DIRECTION OUTPUT ;
    USE SIGNAL ;
    PORT
      LAYER M5 ;
        RECT  16.08 17.064 16.104 17.256 ;
    END
  END do0[283]
  PIN do0[284]
    DIRECTION OUTPUT ;
    USE SIGNAL ;
    PORT
      LAYER M5 ;
        RECT  16.128 17.064 16.152 17.256 ;
    END
  END do0[284]
  PIN do0[285]
    DIRECTION OUTPUT ;
    USE SIGNAL ;
    PORT
      LAYER M5 ;
        RECT  16.176 17.064 16.2 17.256 ;
    END
  END do0[285]
  PIN do0[286]
    DIRECTION OUTPUT ;
    USE SIGNAL ;
    PORT
      LAYER M5 ;
        RECT  16.224 17.064 16.248 17.256 ;
    END
  END do0[286]
  PIN do0[287]
    DIRECTION OUTPUT ;
    USE SIGNAL ;
    PORT
      LAYER M5 ;
        RECT  16.272 17.064 16.296 17.256 ;
    END
  END do0[287]
  PIN do0[288]
    DIRECTION OUTPUT ;
    USE SIGNAL ;
    PORT
      LAYER M5 ;
        RECT  16.32 17.064 16.344 17.256 ;
    END
  END do0[288]
  PIN do0[289]
    DIRECTION OUTPUT ;
    USE SIGNAL ;
    PORT
      LAYER M5 ;
        RECT  16.368 17.064 16.392 17.256 ;
    END
  END do0[289]
  PIN do0[28]
    DIRECTION OUTPUT ;
    USE SIGNAL ;
    PORT
      LAYER M5 ;
        RECT  3.84 17.064 3.864 17.256 ;
    END
  END do0[28]
  PIN do0[290]
    DIRECTION OUTPUT ;
    USE SIGNAL ;
    PORT
      LAYER M5 ;
        RECT  16.416 17.064 16.44 17.256 ;
    END
  END do0[290]
  PIN do0[291]
    DIRECTION OUTPUT ;
    USE SIGNAL ;
    PORT
      LAYER M5 ;
        RECT  16.464 17.064 16.488 17.256 ;
    END
  END do0[291]
  PIN do0[292]
    DIRECTION OUTPUT ;
    USE SIGNAL ;
    PORT
      LAYER M5 ;
        RECT  16.512 17.064 16.536 17.256 ;
    END
  END do0[292]
  PIN do0[293]
    DIRECTION OUTPUT ;
    USE SIGNAL ;
    PORT
      LAYER M5 ;
        RECT  16.56 17.064 16.584 17.256 ;
    END
  END do0[293]
  PIN do0[294]
    DIRECTION OUTPUT ;
    USE SIGNAL ;
    PORT
      LAYER M5 ;
        RECT  16.608 17.064 16.632 17.256 ;
    END
  END do0[294]
  PIN do0[295]
    DIRECTION OUTPUT ;
    USE SIGNAL ;
    PORT
      LAYER M5 ;
        RECT  16.656 17.064 16.68 17.256 ;
    END
  END do0[295]
  PIN do0[296]
    DIRECTION OUTPUT ;
    USE SIGNAL ;
    PORT
      LAYER M5 ;
        RECT  16.704 17.064 16.728 17.256 ;
    END
  END do0[296]
  PIN do0[297]
    DIRECTION OUTPUT ;
    USE SIGNAL ;
    PORT
      LAYER M5 ;
        RECT  16.752 17.064 16.776 17.256 ;
    END
  END do0[297]
  PIN do0[298]
    DIRECTION OUTPUT ;
    USE SIGNAL ;
    PORT
      LAYER M5 ;
        RECT  16.8 17.064 16.824 17.256 ;
    END
  END do0[298]
  PIN do0[299]
    DIRECTION OUTPUT ;
    USE SIGNAL ;
    PORT
      LAYER M5 ;
        RECT  16.848 17.064 16.872 17.256 ;
    END
  END do0[299]
  PIN do0[29]
    DIRECTION OUTPUT ;
    USE SIGNAL ;
    PORT
      LAYER M5 ;
        RECT  3.888 17.064 3.912 17.256 ;
    END
  END do0[29]
  PIN do0[2]
    DIRECTION OUTPUT ;
    USE SIGNAL ;
    PORT
      LAYER M5 ;
        RECT  2.592 17.064 2.616 17.256 ;
    END
  END do0[2]
  PIN do0[300]
    DIRECTION OUTPUT ;
    USE SIGNAL ;
    PORT
      LAYER M5 ;
        RECT  16.896 17.064 16.92 17.256 ;
    END
  END do0[300]
  PIN do0[301]
    DIRECTION OUTPUT ;
    USE SIGNAL ;
    PORT
      LAYER M5 ;
        RECT  16.944 17.064 16.968 17.256 ;
    END
  END do0[301]
  PIN do0[302]
    DIRECTION OUTPUT ;
    USE SIGNAL ;
    PORT
      LAYER M5 ;
        RECT  16.992 17.064 17.016 17.256 ;
    END
  END do0[302]
  PIN do0[303]
    DIRECTION OUTPUT ;
    USE SIGNAL ;
    PORT
      LAYER M5 ;
        RECT  17.04 17.064 17.064 17.256 ;
    END
  END do0[303]
  PIN do0[304]
    DIRECTION OUTPUT ;
    USE SIGNAL ;
    PORT
      LAYER M5 ;
        RECT  17.088 17.064 17.112 17.256 ;
    END
  END do0[304]
  PIN do0[305]
    DIRECTION OUTPUT ;
    USE SIGNAL ;
    PORT
      LAYER M5 ;
        RECT  17.136 17.064 17.16 17.256 ;
    END
  END do0[305]
  PIN do0[306]
    DIRECTION OUTPUT ;
    USE SIGNAL ;
    PORT
      LAYER M5 ;
        RECT  17.184 17.064 17.208 17.256 ;
    END
  END do0[306]
  PIN do0[307]
    DIRECTION OUTPUT ;
    USE SIGNAL ;
    PORT
      LAYER M5 ;
        RECT  17.232 17.064 17.256 17.256 ;
    END
  END do0[307]
  PIN do0[308]
    DIRECTION OUTPUT ;
    USE SIGNAL ;
    PORT
      LAYER M5 ;
        RECT  17.28 17.064 17.304 17.256 ;
    END
  END do0[308]
  PIN do0[309]
    DIRECTION OUTPUT ;
    USE SIGNAL ;
    PORT
      LAYER M5 ;
        RECT  17.328 17.064 17.352 17.256 ;
    END
  END do0[309]
  PIN do0[30]
    DIRECTION OUTPUT ;
    USE SIGNAL ;
    PORT
      LAYER M5 ;
        RECT  3.936 17.064 3.96 17.256 ;
    END
  END do0[30]
  PIN do0[310]
    DIRECTION OUTPUT ;
    USE SIGNAL ;
    PORT
      LAYER M5 ;
        RECT  17.376 17.064 17.4 17.256 ;
    END
  END do0[310]
  PIN do0[311]
    DIRECTION OUTPUT ;
    USE SIGNAL ;
    PORT
      LAYER M5 ;
        RECT  17.424 17.064 17.448 17.256 ;
    END
  END do0[311]
  PIN do0[312]
    DIRECTION OUTPUT ;
    USE SIGNAL ;
    PORT
      LAYER M5 ;
        RECT  17.472 17.064 17.496 17.256 ;
    END
  END do0[312]
  PIN do0[313]
    DIRECTION OUTPUT ;
    USE SIGNAL ;
    PORT
      LAYER M5 ;
        RECT  17.52 17.064 17.544 17.256 ;
    END
  END do0[313]
  PIN do0[314]
    DIRECTION OUTPUT ;
    USE SIGNAL ;
    PORT
      LAYER M5 ;
        RECT  17.568 17.064 17.592 17.256 ;
    END
  END do0[314]
  PIN do0[315]
    DIRECTION OUTPUT ;
    USE SIGNAL ;
    PORT
      LAYER M5 ;
        RECT  17.616 17.064 17.64 17.256 ;
    END
  END do0[315]
  PIN do0[316]
    DIRECTION OUTPUT ;
    USE SIGNAL ;
    PORT
      LAYER M5 ;
        RECT  17.664 17.064 17.688 17.256 ;
    END
  END do0[316]
  PIN do0[317]
    DIRECTION OUTPUT ;
    USE SIGNAL ;
    PORT
      LAYER M5 ;
        RECT  17.712 17.064 17.736 17.256 ;
    END
  END do0[317]
  PIN do0[318]
    DIRECTION OUTPUT ;
    USE SIGNAL ;
    PORT
      LAYER M5 ;
        RECT  17.76 17.064 17.784 17.256 ;
    END
  END do0[318]
  PIN do0[319]
    DIRECTION OUTPUT ;
    USE SIGNAL ;
    PORT
      LAYER M5 ;
        RECT  17.808 17.064 17.832 17.256 ;
    END
  END do0[319]
  PIN do0[31]
    DIRECTION OUTPUT ;
    USE SIGNAL ;
    PORT
      LAYER M5 ;
        RECT  3.984 17.064 4.008 17.256 ;
    END
  END do0[31]
  PIN do0[320]
    DIRECTION OUTPUT ;
    USE SIGNAL ;
    PORT
      LAYER M5 ;
        RECT  17.856 17.064 17.88 17.256 ;
    END
  END do0[320]
  PIN do0[321]
    DIRECTION OUTPUT ;
    USE SIGNAL ;
    PORT
      LAYER M5 ;
        RECT  17.904 17.064 17.928 17.256 ;
    END
  END do0[321]
  PIN do0[322]
    DIRECTION OUTPUT ;
    USE SIGNAL ;
    PORT
      LAYER M5 ;
        RECT  17.952 17.064 17.976 17.256 ;
    END
  END do0[322]
  PIN do0[323]
    DIRECTION OUTPUT ;
    USE SIGNAL ;
    PORT
      LAYER M5 ;
        RECT  18 17.064 18.024 17.256 ;
    END
  END do0[323]
  PIN do0[324]
    DIRECTION OUTPUT ;
    USE SIGNAL ;
    PORT
      LAYER M5 ;
        RECT  18.048 17.064 18.072 17.256 ;
    END
  END do0[324]
  PIN do0[325]
    DIRECTION OUTPUT ;
    USE SIGNAL ;
    PORT
      LAYER M5 ;
        RECT  18.096 17.064 18.12 17.256 ;
    END
  END do0[325]
  PIN do0[326]
    DIRECTION OUTPUT ;
    USE SIGNAL ;
    PORT
      LAYER M5 ;
        RECT  18.144 17.064 18.168 17.256 ;
    END
  END do0[326]
  PIN do0[327]
    DIRECTION OUTPUT ;
    USE SIGNAL ;
    PORT
      LAYER M5 ;
        RECT  18.192 17.064 18.216 17.256 ;
    END
  END do0[327]
  PIN do0[328]
    DIRECTION OUTPUT ;
    USE SIGNAL ;
    PORT
      LAYER M5 ;
        RECT  18.24 17.064 18.264 17.256 ;
    END
  END do0[328]
  PIN do0[329]
    DIRECTION OUTPUT ;
    USE SIGNAL ;
    PORT
      LAYER M5 ;
        RECT  18.288 17.064 18.312 17.256 ;
    END
  END do0[329]
  PIN do0[32]
    DIRECTION OUTPUT ;
    USE SIGNAL ;
    PORT
      LAYER M5 ;
        RECT  4.032 17.064 4.056 17.256 ;
    END
  END do0[32]
  PIN do0[330]
    DIRECTION OUTPUT ;
    USE SIGNAL ;
    PORT
      LAYER M5 ;
        RECT  18.336 17.064 18.36 17.256 ;
    END
  END do0[330]
  PIN do0[331]
    DIRECTION OUTPUT ;
    USE SIGNAL ;
    PORT
      LAYER M5 ;
        RECT  18.384 17.064 18.408 17.256 ;
    END
  END do0[331]
  PIN do0[332]
    DIRECTION OUTPUT ;
    USE SIGNAL ;
    PORT
      LAYER M5 ;
        RECT  18.432 17.064 18.456 17.256 ;
    END
  END do0[332]
  PIN do0[333]
    DIRECTION OUTPUT ;
    USE SIGNAL ;
    PORT
      LAYER M5 ;
        RECT  18.48 17.064 18.504 17.256 ;
    END
  END do0[333]
  PIN do0[334]
    DIRECTION OUTPUT ;
    USE SIGNAL ;
    PORT
      LAYER M5 ;
        RECT  18.528 17.064 18.552 17.256 ;
    END
  END do0[334]
  PIN do0[335]
    DIRECTION OUTPUT ;
    USE SIGNAL ;
    PORT
      LAYER M5 ;
        RECT  18.576 17.064 18.6 17.256 ;
    END
  END do0[335]
  PIN do0[336]
    DIRECTION OUTPUT ;
    USE SIGNAL ;
    PORT
      LAYER M5 ;
        RECT  18.624 17.064 18.648 17.256 ;
    END
  END do0[336]
  PIN do0[337]
    DIRECTION OUTPUT ;
    USE SIGNAL ;
    PORT
      LAYER M5 ;
        RECT  18.672 17.064 18.696 17.256 ;
    END
  END do0[337]
  PIN do0[338]
    DIRECTION OUTPUT ;
    USE SIGNAL ;
    PORT
      LAYER M5 ;
        RECT  18.72 17.064 18.744 17.256 ;
    END
  END do0[338]
  PIN do0[339]
    DIRECTION OUTPUT ;
    USE SIGNAL ;
    PORT
      LAYER M5 ;
        RECT  18.768 17.064 18.792 17.256 ;
    END
  END do0[339]
  PIN do0[33]
    DIRECTION OUTPUT ;
    USE SIGNAL ;
    PORT
      LAYER M5 ;
        RECT  4.08 17.064 4.104 17.256 ;
    END
  END do0[33]
  PIN do0[340]
    DIRECTION OUTPUT ;
    USE SIGNAL ;
    PORT
      LAYER M5 ;
        RECT  18.816 17.064 18.84 17.256 ;
    END
  END do0[340]
  PIN do0[341]
    DIRECTION OUTPUT ;
    USE SIGNAL ;
    PORT
      LAYER M5 ;
        RECT  18.864 17.064 18.888 17.256 ;
    END
  END do0[341]
  PIN do0[342]
    DIRECTION OUTPUT ;
    USE SIGNAL ;
    PORT
      LAYER M5 ;
        RECT  18.912 17.064 18.936 17.256 ;
    END
  END do0[342]
  PIN do0[343]
    DIRECTION OUTPUT ;
    USE SIGNAL ;
    PORT
      LAYER M5 ;
        RECT  18.96 17.064 18.984 17.256 ;
    END
  END do0[343]
  PIN do0[344]
    DIRECTION OUTPUT ;
    USE SIGNAL ;
    PORT
      LAYER M5 ;
        RECT  19.008 17.064 19.032 17.256 ;
    END
  END do0[344]
  PIN do0[345]
    DIRECTION OUTPUT ;
    USE SIGNAL ;
    PORT
      LAYER M5 ;
        RECT  19.056 17.064 19.08 17.256 ;
    END
  END do0[345]
  PIN do0[346]
    DIRECTION OUTPUT ;
    USE SIGNAL ;
    PORT
      LAYER M5 ;
        RECT  19.104 17.064 19.128 17.256 ;
    END
  END do0[346]
  PIN do0[347]
    DIRECTION OUTPUT ;
    USE SIGNAL ;
    PORT
      LAYER M5 ;
        RECT  19.152 17.064 19.176 17.256 ;
    END
  END do0[347]
  PIN do0[348]
    DIRECTION OUTPUT ;
    USE SIGNAL ;
    PORT
      LAYER M5 ;
        RECT  19.2 17.064 19.224 17.256 ;
    END
  END do0[348]
  PIN do0[349]
    DIRECTION OUTPUT ;
    USE SIGNAL ;
    PORT
      LAYER M5 ;
        RECT  19.248 17.064 19.272 17.256 ;
    END
  END do0[349]
  PIN do0[34]
    DIRECTION OUTPUT ;
    USE SIGNAL ;
    PORT
      LAYER M5 ;
        RECT  4.128 17.064 4.152 17.256 ;
    END
  END do0[34]
  PIN do0[350]
    DIRECTION OUTPUT ;
    USE SIGNAL ;
    PORT
      LAYER M5 ;
        RECT  19.296 17.064 19.32 17.256 ;
    END
  END do0[350]
  PIN do0[351]
    DIRECTION OUTPUT ;
    USE SIGNAL ;
    PORT
      LAYER M5 ;
        RECT  19.344 17.064 19.368 17.256 ;
    END
  END do0[351]
  PIN do0[352]
    DIRECTION OUTPUT ;
    USE SIGNAL ;
    PORT
      LAYER M5 ;
        RECT  19.392 17.064 19.416 17.256 ;
    END
  END do0[352]
  PIN do0[353]
    DIRECTION OUTPUT ;
    USE SIGNAL ;
    PORT
      LAYER M5 ;
        RECT  19.44 17.064 19.464 17.256 ;
    END
  END do0[353]
  PIN do0[354]
    DIRECTION OUTPUT ;
    USE SIGNAL ;
    PORT
      LAYER M5 ;
        RECT  19.488 17.064 19.512 17.256 ;
    END
  END do0[354]
  PIN do0[355]
    DIRECTION OUTPUT ;
    USE SIGNAL ;
    PORT
      LAYER M5 ;
        RECT  19.536 17.064 19.56 17.256 ;
    END
  END do0[355]
  PIN do0[356]
    DIRECTION OUTPUT ;
    USE SIGNAL ;
    PORT
      LAYER M5 ;
        RECT  19.584 17.064 19.608 17.256 ;
    END
  END do0[356]
  PIN do0[357]
    DIRECTION OUTPUT ;
    USE SIGNAL ;
    PORT
      LAYER M5 ;
        RECT  19.632 17.064 19.656 17.256 ;
    END
  END do0[357]
  PIN do0[358]
    DIRECTION OUTPUT ;
    USE SIGNAL ;
    PORT
      LAYER M5 ;
        RECT  19.68 17.064 19.704 17.256 ;
    END
  END do0[358]
  PIN do0[359]
    DIRECTION OUTPUT ;
    USE SIGNAL ;
    PORT
      LAYER M5 ;
        RECT  19.728 17.064 19.752 17.256 ;
    END
  END do0[359]
  PIN do0[35]
    DIRECTION OUTPUT ;
    USE SIGNAL ;
    PORT
      LAYER M5 ;
        RECT  4.176 17.064 4.2 17.256 ;
    END
  END do0[35]
  PIN do0[360]
    DIRECTION OUTPUT ;
    USE SIGNAL ;
    PORT
      LAYER M5 ;
        RECT  19.776 17.064 19.8 17.256 ;
    END
  END do0[360]
  PIN do0[361]
    DIRECTION OUTPUT ;
    USE SIGNAL ;
    PORT
      LAYER M5 ;
        RECT  19.824 17.064 19.848 17.256 ;
    END
  END do0[361]
  PIN do0[362]
    DIRECTION OUTPUT ;
    USE SIGNAL ;
    PORT
      LAYER M5 ;
        RECT  19.872 17.064 19.896 17.256 ;
    END
  END do0[362]
  PIN do0[363]
    DIRECTION OUTPUT ;
    USE SIGNAL ;
    PORT
      LAYER M5 ;
        RECT  19.92 17.064 19.944 17.256 ;
    END
  END do0[363]
  PIN do0[364]
    DIRECTION OUTPUT ;
    USE SIGNAL ;
    PORT
      LAYER M5 ;
        RECT  19.968 17.064 19.992 17.256 ;
    END
  END do0[364]
  PIN do0[365]
    DIRECTION OUTPUT ;
    USE SIGNAL ;
    PORT
      LAYER M5 ;
        RECT  20.016 17.064 20.04 17.256 ;
    END
  END do0[365]
  PIN do0[366]
    DIRECTION OUTPUT ;
    USE SIGNAL ;
    PORT
      LAYER M5 ;
        RECT  20.064 17.064 20.088 17.256 ;
    END
  END do0[366]
  PIN do0[367]
    DIRECTION OUTPUT ;
    USE SIGNAL ;
    PORT
      LAYER M5 ;
        RECT  20.112 17.064 20.136 17.256 ;
    END
  END do0[367]
  PIN do0[368]
    DIRECTION OUTPUT ;
    USE SIGNAL ;
    PORT
      LAYER M5 ;
        RECT  20.16 17.064 20.184 17.256 ;
    END
  END do0[368]
  PIN do0[369]
    DIRECTION OUTPUT ;
    USE SIGNAL ;
    PORT
      LAYER M5 ;
        RECT  20.208 17.064 20.232 17.256 ;
    END
  END do0[369]
  PIN do0[36]
    DIRECTION OUTPUT ;
    USE SIGNAL ;
    PORT
      LAYER M5 ;
        RECT  4.224 17.064 4.248 17.256 ;
    END
  END do0[36]
  PIN do0[370]
    DIRECTION OUTPUT ;
    USE SIGNAL ;
    PORT
      LAYER M5 ;
        RECT  20.256 17.064 20.28 17.256 ;
    END
  END do0[370]
  PIN do0[371]
    DIRECTION OUTPUT ;
    USE SIGNAL ;
    PORT
      LAYER M5 ;
        RECT  20.304 17.064 20.328 17.256 ;
    END
  END do0[371]
  PIN do0[372]
    DIRECTION OUTPUT ;
    USE SIGNAL ;
    PORT
      LAYER M5 ;
        RECT  20.352 17.064 20.376 17.256 ;
    END
  END do0[372]
  PIN do0[373]
    DIRECTION OUTPUT ;
    USE SIGNAL ;
    PORT
      LAYER M5 ;
        RECT  20.4 17.064 20.424 17.256 ;
    END
  END do0[373]
  PIN do0[374]
    DIRECTION OUTPUT ;
    USE SIGNAL ;
    PORT
      LAYER M5 ;
        RECT  20.448 17.064 20.472 17.256 ;
    END
  END do0[374]
  PIN do0[375]
    DIRECTION OUTPUT ;
    USE SIGNAL ;
    PORT
      LAYER M5 ;
        RECT  20.496 17.064 20.52 17.256 ;
    END
  END do0[375]
  PIN do0[376]
    DIRECTION OUTPUT ;
    USE SIGNAL ;
    PORT
      LAYER M5 ;
        RECT  20.544 17.064 20.568 17.256 ;
    END
  END do0[376]
  PIN do0[377]
    DIRECTION OUTPUT ;
    USE SIGNAL ;
    PORT
      LAYER M5 ;
        RECT  20.592 17.064 20.616 17.256 ;
    END
  END do0[377]
  PIN do0[378]
    DIRECTION OUTPUT ;
    USE SIGNAL ;
    PORT
      LAYER M5 ;
        RECT  20.64 17.064 20.664 17.256 ;
    END
  END do0[378]
  PIN do0[379]
    DIRECTION OUTPUT ;
    USE SIGNAL ;
    PORT
      LAYER M5 ;
        RECT  20.688 17.064 20.712 17.256 ;
    END
  END do0[379]
  PIN do0[37]
    DIRECTION OUTPUT ;
    USE SIGNAL ;
    PORT
      LAYER M5 ;
        RECT  4.272 17.064 4.296 17.256 ;
    END
  END do0[37]
  PIN do0[380]
    DIRECTION OUTPUT ;
    USE SIGNAL ;
    PORT
      LAYER M5 ;
        RECT  20.736 17.064 20.76 17.256 ;
    END
  END do0[380]
  PIN do0[381]
    DIRECTION OUTPUT ;
    USE SIGNAL ;
    PORT
      LAYER M5 ;
        RECT  20.784 17.064 20.808 17.256 ;
    END
  END do0[381]
  PIN do0[382]
    DIRECTION OUTPUT ;
    USE SIGNAL ;
    PORT
      LAYER M5 ;
        RECT  20.832 17.064 20.856 17.256 ;
    END
  END do0[382]
  PIN do0[383]
    DIRECTION OUTPUT ;
    USE SIGNAL ;
    PORT
      LAYER M5 ;
        RECT  20.88 17.064 20.904 17.256 ;
    END
  END do0[383]
  PIN do0[384]
    DIRECTION OUTPUT ;
    USE SIGNAL ;
    PORT
      LAYER M5 ;
        RECT  20.928 17.064 20.952 17.256 ;
    END
  END do0[384]
  PIN do0[385]
    DIRECTION OUTPUT ;
    USE SIGNAL ;
    PORT
      LAYER M5 ;
        RECT  20.976 17.064 21 17.256 ;
    END
  END do0[385]
  PIN do0[386]
    DIRECTION OUTPUT ;
    USE SIGNAL ;
    PORT
      LAYER M5 ;
        RECT  21.024 17.064 21.048 17.256 ;
    END
  END do0[386]
  PIN do0[387]
    DIRECTION OUTPUT ;
    USE SIGNAL ;
    PORT
      LAYER M5 ;
        RECT  21.072 17.064 21.096 17.256 ;
    END
  END do0[387]
  PIN do0[388]
    DIRECTION OUTPUT ;
    USE SIGNAL ;
    PORT
      LAYER M5 ;
        RECT  21.12 17.064 21.144 17.256 ;
    END
  END do0[388]
  PIN do0[389]
    DIRECTION OUTPUT ;
    USE SIGNAL ;
    PORT
      LAYER M5 ;
        RECT  21.168 17.064 21.192 17.256 ;
    END
  END do0[389]
  PIN do0[38]
    DIRECTION OUTPUT ;
    USE SIGNAL ;
    PORT
      LAYER M5 ;
        RECT  4.32 17.064 4.344 17.256 ;
    END
  END do0[38]
  PIN do0[390]
    DIRECTION OUTPUT ;
    USE SIGNAL ;
    PORT
      LAYER M5 ;
        RECT  21.216 17.064 21.24 17.256 ;
    END
  END do0[390]
  PIN do0[391]
    DIRECTION OUTPUT ;
    USE SIGNAL ;
    PORT
      LAYER M5 ;
        RECT  21.264 17.064 21.288 17.256 ;
    END
  END do0[391]
  PIN do0[392]
    DIRECTION OUTPUT ;
    USE SIGNAL ;
    PORT
      LAYER M5 ;
        RECT  21.312 17.064 21.336 17.256 ;
    END
  END do0[392]
  PIN do0[393]
    DIRECTION OUTPUT ;
    USE SIGNAL ;
    PORT
      LAYER M5 ;
        RECT  21.36 17.064 21.384 17.256 ;
    END
  END do0[393]
  PIN do0[394]
    DIRECTION OUTPUT ;
    USE SIGNAL ;
    PORT
      LAYER M5 ;
        RECT  21.408 17.064 21.432 17.256 ;
    END
  END do0[394]
  PIN do0[395]
    DIRECTION OUTPUT ;
    USE SIGNAL ;
    PORT
      LAYER M5 ;
        RECT  21.456 17.064 21.48 17.256 ;
    END
  END do0[395]
  PIN do0[396]
    DIRECTION OUTPUT ;
    USE SIGNAL ;
    PORT
      LAYER M5 ;
        RECT  21.504 17.064 21.528 17.256 ;
    END
  END do0[396]
  PIN do0[397]
    DIRECTION OUTPUT ;
    USE SIGNAL ;
    PORT
      LAYER M5 ;
        RECT  21.552 17.064 21.576 17.256 ;
    END
  END do0[397]
  PIN do0[398]
    DIRECTION OUTPUT ;
    USE SIGNAL ;
    PORT
      LAYER M5 ;
        RECT  21.6 17.064 21.624 17.256 ;
    END
  END do0[398]
  PIN do0[399]
    DIRECTION OUTPUT ;
    USE SIGNAL ;
    PORT
      LAYER M5 ;
        RECT  21.648 17.064 21.672 17.256 ;
    END
  END do0[399]
  PIN do0[39]
    DIRECTION OUTPUT ;
    USE SIGNAL ;
    PORT
      LAYER M5 ;
        RECT  4.368 17.064 4.392 17.256 ;
    END
  END do0[39]
  PIN do0[3]
    DIRECTION OUTPUT ;
    USE SIGNAL ;
    PORT
      LAYER M5 ;
        RECT  2.64 17.064 2.664 17.256 ;
    END
  END do0[3]
  PIN do0[400]
    DIRECTION OUTPUT ;
    USE SIGNAL ;
    PORT
      LAYER M5 ;
        RECT  21.696 17.064 21.72 17.256 ;
    END
  END do0[400]
  PIN do0[401]
    DIRECTION OUTPUT ;
    USE SIGNAL ;
    PORT
      LAYER M5 ;
        RECT  21.744 17.064 21.768 17.256 ;
    END
  END do0[401]
  PIN do0[402]
    DIRECTION OUTPUT ;
    USE SIGNAL ;
    PORT
      LAYER M5 ;
        RECT  21.792 17.064 21.816 17.256 ;
    END
  END do0[402]
  PIN do0[403]
    DIRECTION OUTPUT ;
    USE SIGNAL ;
    PORT
      LAYER M5 ;
        RECT  21.84 17.064 21.864 17.256 ;
    END
  END do0[403]
  PIN do0[404]
    DIRECTION OUTPUT ;
    USE SIGNAL ;
    PORT
      LAYER M5 ;
        RECT  21.888 17.064 21.912 17.256 ;
    END
  END do0[404]
  PIN do0[405]
    DIRECTION OUTPUT ;
    USE SIGNAL ;
    PORT
      LAYER M5 ;
        RECT  21.936 17.064 21.96 17.256 ;
    END
  END do0[405]
  PIN do0[406]
    DIRECTION OUTPUT ;
    USE SIGNAL ;
    PORT
      LAYER M5 ;
        RECT  21.984 17.064 22.008 17.256 ;
    END
  END do0[406]
  PIN do0[407]
    DIRECTION OUTPUT ;
    USE SIGNAL ;
    PORT
      LAYER M5 ;
        RECT  22.032 17.064 22.056 17.256 ;
    END
  END do0[407]
  PIN do0[408]
    DIRECTION OUTPUT ;
    USE SIGNAL ;
    PORT
      LAYER M5 ;
        RECT  22.08 17.064 22.104 17.256 ;
    END
  END do0[408]
  PIN do0[409]
    DIRECTION OUTPUT ;
    USE SIGNAL ;
    PORT
      LAYER M5 ;
        RECT  22.128 17.064 22.152 17.256 ;
    END
  END do0[409]
  PIN do0[40]
    DIRECTION OUTPUT ;
    USE SIGNAL ;
    PORT
      LAYER M5 ;
        RECT  4.416 17.064 4.44 17.256 ;
    END
  END do0[40]
  PIN do0[410]
    DIRECTION OUTPUT ;
    USE SIGNAL ;
    PORT
      LAYER M5 ;
        RECT  22.176 17.064 22.2 17.256 ;
    END
  END do0[410]
  PIN do0[411]
    DIRECTION OUTPUT ;
    USE SIGNAL ;
    PORT
      LAYER M5 ;
        RECT  22.224 17.064 22.248 17.256 ;
    END
  END do0[411]
  PIN do0[412]
    DIRECTION OUTPUT ;
    USE SIGNAL ;
    PORT
      LAYER M5 ;
        RECT  22.272 17.064 22.296 17.256 ;
    END
  END do0[412]
  PIN do0[413]
    DIRECTION OUTPUT ;
    USE SIGNAL ;
    PORT
      LAYER M5 ;
        RECT  22.32 17.064 22.344 17.256 ;
    END
  END do0[413]
  PIN do0[414]
    DIRECTION OUTPUT ;
    USE SIGNAL ;
    PORT
      LAYER M5 ;
        RECT  22.368 17.064 22.392 17.256 ;
    END
  END do0[414]
  PIN do0[415]
    DIRECTION OUTPUT ;
    USE SIGNAL ;
    PORT
      LAYER M5 ;
        RECT  22.416 17.064 22.44 17.256 ;
    END
  END do0[415]
  PIN do0[416]
    DIRECTION OUTPUT ;
    USE SIGNAL ;
    PORT
      LAYER M5 ;
        RECT  22.464 17.064 22.488 17.256 ;
    END
  END do0[416]
  PIN do0[417]
    DIRECTION OUTPUT ;
    USE SIGNAL ;
    PORT
      LAYER M5 ;
        RECT  22.512 17.064 22.536 17.256 ;
    END
  END do0[417]
  PIN do0[418]
    DIRECTION OUTPUT ;
    USE SIGNAL ;
    PORT
      LAYER M5 ;
        RECT  22.56 17.064 22.584 17.256 ;
    END
  END do0[418]
  PIN do0[419]
    DIRECTION OUTPUT ;
    USE SIGNAL ;
    PORT
      LAYER M5 ;
        RECT  22.608 17.064 22.632 17.256 ;
    END
  END do0[419]
  PIN do0[41]
    DIRECTION OUTPUT ;
    USE SIGNAL ;
    PORT
      LAYER M5 ;
        RECT  4.464 17.064 4.488 17.256 ;
    END
  END do0[41]
  PIN do0[420]
    DIRECTION OUTPUT ;
    USE SIGNAL ;
    PORT
      LAYER M5 ;
        RECT  22.656 17.064 22.68 17.256 ;
    END
  END do0[420]
  PIN do0[421]
    DIRECTION OUTPUT ;
    USE SIGNAL ;
    PORT
      LAYER M5 ;
        RECT  22.704 17.064 22.728 17.256 ;
    END
  END do0[421]
  PIN do0[422]
    DIRECTION OUTPUT ;
    USE SIGNAL ;
    PORT
      LAYER M5 ;
        RECT  22.752 17.064 22.776 17.256 ;
    END
  END do0[422]
  PIN do0[423]
    DIRECTION OUTPUT ;
    USE SIGNAL ;
    PORT
      LAYER M5 ;
        RECT  22.8 17.064 22.824 17.256 ;
    END
  END do0[423]
  PIN do0[424]
    DIRECTION OUTPUT ;
    USE SIGNAL ;
    PORT
      LAYER M5 ;
        RECT  22.848 17.064 22.872 17.256 ;
    END
  END do0[424]
  PIN do0[425]
    DIRECTION OUTPUT ;
    USE SIGNAL ;
    PORT
      LAYER M5 ;
        RECT  22.896 17.064 22.92 17.256 ;
    END
  END do0[425]
  PIN do0[426]
    DIRECTION OUTPUT ;
    USE SIGNAL ;
    PORT
      LAYER M5 ;
        RECT  22.944 17.064 22.968 17.256 ;
    END
  END do0[426]
  PIN do0[427]
    DIRECTION OUTPUT ;
    USE SIGNAL ;
    PORT
      LAYER M5 ;
        RECT  22.992 17.064 23.016 17.256 ;
    END
  END do0[427]
  PIN do0[428]
    DIRECTION OUTPUT ;
    USE SIGNAL ;
    PORT
      LAYER M5 ;
        RECT  23.04 17.064 23.064 17.256 ;
    END
  END do0[428]
  PIN do0[429]
    DIRECTION OUTPUT ;
    USE SIGNAL ;
    PORT
      LAYER M5 ;
        RECT  23.088 17.064 23.112 17.256 ;
    END
  END do0[429]
  PIN do0[42]
    DIRECTION OUTPUT ;
    USE SIGNAL ;
    PORT
      LAYER M5 ;
        RECT  4.512 17.064 4.536 17.256 ;
    END
  END do0[42]
  PIN do0[430]
    DIRECTION OUTPUT ;
    USE SIGNAL ;
    PORT
      LAYER M5 ;
        RECT  23.136 17.064 23.16 17.256 ;
    END
  END do0[430]
  PIN do0[431]
    DIRECTION OUTPUT ;
    USE SIGNAL ;
    PORT
      LAYER M5 ;
        RECT  23.184 17.064 23.208 17.256 ;
    END
  END do0[431]
  PIN do0[432]
    DIRECTION OUTPUT ;
    USE SIGNAL ;
    PORT
      LAYER M5 ;
        RECT  23.232 17.064 23.256 17.256 ;
    END
  END do0[432]
  PIN do0[433]
    DIRECTION OUTPUT ;
    USE SIGNAL ;
    PORT
      LAYER M5 ;
        RECT  23.28 17.064 23.304 17.256 ;
    END
  END do0[433]
  PIN do0[434]
    DIRECTION OUTPUT ;
    USE SIGNAL ;
    PORT
      LAYER M5 ;
        RECT  23.328 17.064 23.352 17.256 ;
    END
  END do0[434]
  PIN do0[435]
    DIRECTION OUTPUT ;
    USE SIGNAL ;
    PORT
      LAYER M5 ;
        RECT  23.376 17.064 23.4 17.256 ;
    END
  END do0[435]
  PIN do0[436]
    DIRECTION OUTPUT ;
    USE SIGNAL ;
    PORT
      LAYER M5 ;
        RECT  23.424 17.064 23.448 17.256 ;
    END
  END do0[436]
  PIN do0[437]
    DIRECTION OUTPUT ;
    USE SIGNAL ;
    PORT
      LAYER M5 ;
        RECT  23.472 17.064 23.496 17.256 ;
    END
  END do0[437]
  PIN do0[438]
    DIRECTION OUTPUT ;
    USE SIGNAL ;
    PORT
      LAYER M5 ;
        RECT  23.52 17.064 23.544 17.256 ;
    END
  END do0[438]
  PIN do0[439]
    DIRECTION OUTPUT ;
    USE SIGNAL ;
    PORT
      LAYER M5 ;
        RECT  23.568 17.064 23.592 17.256 ;
    END
  END do0[439]
  PIN do0[43]
    DIRECTION OUTPUT ;
    USE SIGNAL ;
    PORT
      LAYER M5 ;
        RECT  4.56 17.064 4.584 17.256 ;
    END
  END do0[43]
  PIN do0[440]
    DIRECTION OUTPUT ;
    USE SIGNAL ;
    PORT
      LAYER M5 ;
        RECT  23.616 17.064 23.64 17.256 ;
    END
  END do0[440]
  PIN do0[441]
    DIRECTION OUTPUT ;
    USE SIGNAL ;
    PORT
      LAYER M5 ;
        RECT  23.664 17.064 23.688 17.256 ;
    END
  END do0[441]
  PIN do0[442]
    DIRECTION OUTPUT ;
    USE SIGNAL ;
    PORT
      LAYER M5 ;
        RECT  23.712 17.064 23.736 17.256 ;
    END
  END do0[442]
  PIN do0[443]
    DIRECTION OUTPUT ;
    USE SIGNAL ;
    PORT
      LAYER M5 ;
        RECT  23.76 17.064 23.784 17.256 ;
    END
  END do0[443]
  PIN do0[444]
    DIRECTION OUTPUT ;
    USE SIGNAL ;
    PORT
      LAYER M5 ;
        RECT  23.808 17.064 23.832 17.256 ;
    END
  END do0[444]
  PIN do0[445]
    DIRECTION OUTPUT ;
    USE SIGNAL ;
    PORT
      LAYER M5 ;
        RECT  23.856 17.064 23.88 17.256 ;
    END
  END do0[445]
  PIN do0[446]
    DIRECTION OUTPUT ;
    USE SIGNAL ;
    PORT
      LAYER M5 ;
        RECT  23.904 17.064 23.928 17.256 ;
    END
  END do0[446]
  PIN do0[447]
    DIRECTION OUTPUT ;
    USE SIGNAL ;
    PORT
      LAYER M5 ;
        RECT  23.952 17.064 23.976 17.256 ;
    END
  END do0[447]
  PIN do0[448]
    DIRECTION OUTPUT ;
    USE SIGNAL ;
    PORT
      LAYER M5 ;
        RECT  24 17.064 24.024 17.256 ;
    END
  END do0[448]
  PIN do0[449]
    DIRECTION OUTPUT ;
    USE SIGNAL ;
    PORT
      LAYER M5 ;
        RECT  24.048 17.064 24.072 17.256 ;
    END
  END do0[449]
  PIN do0[44]
    DIRECTION OUTPUT ;
    USE SIGNAL ;
    PORT
      LAYER M5 ;
        RECT  4.608 17.064 4.632 17.256 ;
    END
  END do0[44]
  PIN do0[450]
    DIRECTION OUTPUT ;
    USE SIGNAL ;
    PORT
      LAYER M5 ;
        RECT  24.096 17.064 24.12 17.256 ;
    END
  END do0[450]
  PIN do0[451]
    DIRECTION OUTPUT ;
    USE SIGNAL ;
    PORT
      LAYER M5 ;
        RECT  24.144 17.064 24.168 17.256 ;
    END
  END do0[451]
  PIN do0[452]
    DIRECTION OUTPUT ;
    USE SIGNAL ;
    PORT
      LAYER M5 ;
        RECT  24.192 17.064 24.216 17.256 ;
    END
  END do0[452]
  PIN do0[453]
    DIRECTION OUTPUT ;
    USE SIGNAL ;
    PORT
      LAYER M5 ;
        RECT  24.24 17.064 24.264 17.256 ;
    END
  END do0[453]
  PIN do0[454]
    DIRECTION OUTPUT ;
    USE SIGNAL ;
    PORT
      LAYER M5 ;
        RECT  24.288 17.064 24.312 17.256 ;
    END
  END do0[454]
  PIN do0[455]
    DIRECTION OUTPUT ;
    USE SIGNAL ;
    PORT
      LAYER M5 ;
        RECT  24.336 17.064 24.36 17.256 ;
    END
  END do0[455]
  PIN do0[456]
    DIRECTION OUTPUT ;
    USE SIGNAL ;
    PORT
      LAYER M5 ;
        RECT  24.384 17.064 24.408 17.256 ;
    END
  END do0[456]
  PIN do0[457]
    DIRECTION OUTPUT ;
    USE SIGNAL ;
    PORT
      LAYER M5 ;
        RECT  24.432 17.064 24.456 17.256 ;
    END
  END do0[457]
  PIN do0[458]
    DIRECTION OUTPUT ;
    USE SIGNAL ;
    PORT
      LAYER M5 ;
        RECT  24.48 17.064 24.504 17.256 ;
    END
  END do0[458]
  PIN do0[459]
    DIRECTION OUTPUT ;
    USE SIGNAL ;
    PORT
      LAYER M5 ;
        RECT  24.528 17.064 24.552 17.256 ;
    END
  END do0[459]
  PIN do0[45]
    DIRECTION OUTPUT ;
    USE SIGNAL ;
    PORT
      LAYER M5 ;
        RECT  4.656 17.064 4.68 17.256 ;
    END
  END do0[45]
  PIN do0[460]
    DIRECTION OUTPUT ;
    USE SIGNAL ;
    PORT
      LAYER M5 ;
        RECT  24.576 17.064 24.6 17.256 ;
    END
  END do0[460]
  PIN do0[461]
    DIRECTION OUTPUT ;
    USE SIGNAL ;
    PORT
      LAYER M5 ;
        RECT  24.624 17.064 24.648 17.256 ;
    END
  END do0[461]
  PIN do0[462]
    DIRECTION OUTPUT ;
    USE SIGNAL ;
    PORT
      LAYER M5 ;
        RECT  24.672 17.064 24.696 17.256 ;
    END
  END do0[462]
  PIN do0[463]
    DIRECTION OUTPUT ;
    USE SIGNAL ;
    PORT
      LAYER M5 ;
        RECT  24.72 17.064 24.744 17.256 ;
    END
  END do0[463]
  PIN do0[464]
    DIRECTION OUTPUT ;
    USE SIGNAL ;
    PORT
      LAYER M5 ;
        RECT  24.768 17.064 24.792 17.256 ;
    END
  END do0[464]
  PIN do0[465]
    DIRECTION OUTPUT ;
    USE SIGNAL ;
    PORT
      LAYER M5 ;
        RECT  24.816 17.064 24.84 17.256 ;
    END
  END do0[465]
  PIN do0[466]
    DIRECTION OUTPUT ;
    USE SIGNAL ;
    PORT
      LAYER M5 ;
        RECT  24.864 17.064 24.888 17.256 ;
    END
  END do0[466]
  PIN do0[467]
    DIRECTION OUTPUT ;
    USE SIGNAL ;
    PORT
      LAYER M5 ;
        RECT  24.912 17.064 24.936 17.256 ;
    END
  END do0[467]
  PIN do0[468]
    DIRECTION OUTPUT ;
    USE SIGNAL ;
    PORT
      LAYER M5 ;
        RECT  24.96 17.064 24.984 17.256 ;
    END
  END do0[468]
  PIN do0[469]
    DIRECTION OUTPUT ;
    USE SIGNAL ;
    PORT
      LAYER M5 ;
        RECT  25.008 17.064 25.032 17.256 ;
    END
  END do0[469]
  PIN do0[46]
    DIRECTION OUTPUT ;
    USE SIGNAL ;
    PORT
      LAYER M5 ;
        RECT  4.704 17.064 4.728 17.256 ;
    END
  END do0[46]
  PIN do0[470]
    DIRECTION OUTPUT ;
    USE SIGNAL ;
    PORT
      LAYER M5 ;
        RECT  25.056 17.064 25.08 17.256 ;
    END
  END do0[470]
  PIN do0[471]
    DIRECTION OUTPUT ;
    USE SIGNAL ;
    PORT
      LAYER M5 ;
        RECT  25.104 17.064 25.128 17.256 ;
    END
  END do0[471]
  PIN do0[472]
    DIRECTION OUTPUT ;
    USE SIGNAL ;
    PORT
      LAYER M5 ;
        RECT  25.152 17.064 25.176 17.256 ;
    END
  END do0[472]
  PIN do0[473]
    DIRECTION OUTPUT ;
    USE SIGNAL ;
    PORT
      LAYER M5 ;
        RECT  25.2 17.064 25.224 17.256 ;
    END
  END do0[473]
  PIN do0[474]
    DIRECTION OUTPUT ;
    USE SIGNAL ;
    PORT
      LAYER M5 ;
        RECT  25.248 17.064 25.272 17.256 ;
    END
  END do0[474]
  PIN do0[475]
    DIRECTION OUTPUT ;
    USE SIGNAL ;
    PORT
      LAYER M5 ;
        RECT  25.296 17.064 25.32 17.256 ;
    END
  END do0[475]
  PIN do0[476]
    DIRECTION OUTPUT ;
    USE SIGNAL ;
    PORT
      LAYER M5 ;
        RECT  25.344 17.064 25.368 17.256 ;
    END
  END do0[476]
  PIN do0[477]
    DIRECTION OUTPUT ;
    USE SIGNAL ;
    PORT
      LAYER M5 ;
        RECT  25.392 17.064 25.416 17.256 ;
    END
  END do0[477]
  PIN do0[478]
    DIRECTION OUTPUT ;
    USE SIGNAL ;
    PORT
      LAYER M5 ;
        RECT  25.44 17.064 25.464 17.256 ;
    END
  END do0[478]
  PIN do0[479]
    DIRECTION OUTPUT ;
    USE SIGNAL ;
    PORT
      LAYER M5 ;
        RECT  25.488 17.064 25.512 17.256 ;
    END
  END do0[479]
  PIN do0[47]
    DIRECTION OUTPUT ;
    USE SIGNAL ;
    PORT
      LAYER M5 ;
        RECT  4.752 17.064 4.776 17.256 ;
    END
  END do0[47]
  PIN do0[480]
    DIRECTION OUTPUT ;
    USE SIGNAL ;
    PORT
      LAYER M5 ;
        RECT  25.536 17.064 25.56 17.256 ;
    END
  END do0[480]
  PIN do0[481]
    DIRECTION OUTPUT ;
    USE SIGNAL ;
    PORT
      LAYER M5 ;
        RECT  25.584 17.064 25.608 17.256 ;
    END
  END do0[481]
  PIN do0[482]
    DIRECTION OUTPUT ;
    USE SIGNAL ;
    PORT
      LAYER M5 ;
        RECT  25.632 17.064 25.656 17.256 ;
    END
  END do0[482]
  PIN do0[483]
    DIRECTION OUTPUT ;
    USE SIGNAL ;
    PORT
      LAYER M5 ;
        RECT  25.68 17.064 25.704 17.256 ;
    END
  END do0[483]
  PIN do0[484]
    DIRECTION OUTPUT ;
    USE SIGNAL ;
    PORT
      LAYER M5 ;
        RECT  25.728 17.064 25.752 17.256 ;
    END
  END do0[484]
  PIN do0[485]
    DIRECTION OUTPUT ;
    USE SIGNAL ;
    PORT
      LAYER M5 ;
        RECT  25.776 17.064 25.8 17.256 ;
    END
  END do0[485]
  PIN do0[486]
    DIRECTION OUTPUT ;
    USE SIGNAL ;
    PORT
      LAYER M5 ;
        RECT  25.824 17.064 25.848 17.256 ;
    END
  END do0[486]
  PIN do0[487]
    DIRECTION OUTPUT ;
    USE SIGNAL ;
    PORT
      LAYER M5 ;
        RECT  25.872 17.064 25.896 17.256 ;
    END
  END do0[487]
  PIN do0[488]
    DIRECTION OUTPUT ;
    USE SIGNAL ;
    PORT
      LAYER M5 ;
        RECT  25.92 17.064 25.944 17.256 ;
    END
  END do0[488]
  PIN do0[489]
    DIRECTION OUTPUT ;
    USE SIGNAL ;
    PORT
      LAYER M5 ;
        RECT  25.968 17.064 25.992 17.256 ;
    END
  END do0[489]
  PIN do0[48]
    DIRECTION OUTPUT ;
    USE SIGNAL ;
    PORT
      LAYER M5 ;
        RECT  4.8 17.064 4.824 17.256 ;
    END
  END do0[48]
  PIN do0[490]
    DIRECTION OUTPUT ;
    USE SIGNAL ;
    PORT
      LAYER M5 ;
        RECT  26.016 17.064 26.04 17.256 ;
    END
  END do0[490]
  PIN do0[491]
    DIRECTION OUTPUT ;
    USE SIGNAL ;
    PORT
      LAYER M5 ;
        RECT  26.064 17.064 26.088 17.256 ;
    END
  END do0[491]
  PIN do0[492]
    DIRECTION OUTPUT ;
    USE SIGNAL ;
    PORT
      LAYER M5 ;
        RECT  26.112 17.064 26.136 17.256 ;
    END
  END do0[492]
  PIN do0[493]
    DIRECTION OUTPUT ;
    USE SIGNAL ;
    PORT
      LAYER M5 ;
        RECT  26.16 17.064 26.184 17.256 ;
    END
  END do0[493]
  PIN do0[494]
    DIRECTION OUTPUT ;
    USE SIGNAL ;
    PORT
      LAYER M5 ;
        RECT  26.208 17.064 26.232 17.256 ;
    END
  END do0[494]
  PIN do0[495]
    DIRECTION OUTPUT ;
    USE SIGNAL ;
    PORT
      LAYER M5 ;
        RECT  26.256 17.064 26.28 17.256 ;
    END
  END do0[495]
  PIN do0[496]
    DIRECTION OUTPUT ;
    USE SIGNAL ;
    PORT
      LAYER M5 ;
        RECT  26.304 17.064 26.328 17.256 ;
    END
  END do0[496]
  PIN do0[497]
    DIRECTION OUTPUT ;
    USE SIGNAL ;
    PORT
      LAYER M5 ;
        RECT  26.352 17.064 26.376 17.256 ;
    END
  END do0[497]
  PIN do0[498]
    DIRECTION OUTPUT ;
    USE SIGNAL ;
    PORT
      LAYER M5 ;
        RECT  26.4 17.064 26.424 17.256 ;
    END
  END do0[498]
  PIN do0[499]
    DIRECTION OUTPUT ;
    USE SIGNAL ;
    PORT
      LAYER M5 ;
        RECT  26.448 17.064 26.472 17.256 ;
    END
  END do0[499]
  PIN do0[49]
    DIRECTION OUTPUT ;
    USE SIGNAL ;
    PORT
      LAYER M5 ;
        RECT  4.848 17.064 4.872 17.256 ;
    END
  END do0[49]
  PIN do0[4]
    DIRECTION OUTPUT ;
    USE SIGNAL ;
    PORT
      LAYER M5 ;
        RECT  2.688 17.064 2.712 17.256 ;
    END
  END do0[4]
  PIN do0[500]
    DIRECTION OUTPUT ;
    USE SIGNAL ;
    PORT
      LAYER M5 ;
        RECT  26.496 17.064 26.52 17.256 ;
    END
  END do0[500]
  PIN do0[501]
    DIRECTION OUTPUT ;
    USE SIGNAL ;
    PORT
      LAYER M5 ;
        RECT  26.544 17.064 26.568 17.256 ;
    END
  END do0[501]
  PIN do0[502]
    DIRECTION OUTPUT ;
    USE SIGNAL ;
    PORT
      LAYER M5 ;
        RECT  26.592 17.064 26.616 17.256 ;
    END
  END do0[502]
  PIN do0[503]
    DIRECTION OUTPUT ;
    USE SIGNAL ;
    PORT
      LAYER M5 ;
        RECT  26.64 17.064 26.664 17.256 ;
    END
  END do0[503]
  PIN do0[504]
    DIRECTION OUTPUT ;
    USE SIGNAL ;
    PORT
      LAYER M5 ;
        RECT  26.688 17.064 26.712 17.256 ;
    END
  END do0[504]
  PIN do0[505]
    DIRECTION OUTPUT ;
    USE SIGNAL ;
    PORT
      LAYER M5 ;
        RECT  26.736 17.064 26.76 17.256 ;
    END
  END do0[505]
  PIN do0[506]
    DIRECTION OUTPUT ;
    USE SIGNAL ;
    PORT
      LAYER M5 ;
        RECT  26.784 17.064 26.808 17.256 ;
    END
  END do0[506]
  PIN do0[507]
    DIRECTION OUTPUT ;
    USE SIGNAL ;
    PORT
      LAYER M5 ;
        RECT  26.832 17.064 26.856 17.256 ;
    END
  END do0[507]
  PIN do0[508]
    DIRECTION OUTPUT ;
    USE SIGNAL ;
    PORT
      LAYER M5 ;
        RECT  26.88 17.064 26.904 17.256 ;
    END
  END do0[508]
  PIN do0[509]
    DIRECTION OUTPUT ;
    USE SIGNAL ;
    PORT
      LAYER M5 ;
        RECT  26.928 17.064 26.952 17.256 ;
    END
  END do0[509]
  PIN do0[50]
    DIRECTION OUTPUT ;
    USE SIGNAL ;
    PORT
      LAYER M5 ;
        RECT  4.896 17.064 4.92 17.256 ;
    END
  END do0[50]
  PIN do0[510]
    DIRECTION OUTPUT ;
    USE SIGNAL ;
    PORT
      LAYER M5 ;
        RECT  26.976 17.064 27 17.256 ;
    END
  END do0[510]
  PIN do0[511]
    DIRECTION OUTPUT ;
    USE SIGNAL ;
    PORT
      LAYER M5 ;
        RECT  27.024 17.064 27.048 17.256 ;
    END
  END do0[511]
  PIN do0[51]
    DIRECTION OUTPUT ;
    USE SIGNAL ;
    PORT
      LAYER M5 ;
        RECT  4.944 17.064 4.968 17.256 ;
    END
  END do0[51]
  PIN do0[52]
    DIRECTION OUTPUT ;
    USE SIGNAL ;
    PORT
      LAYER M5 ;
        RECT  4.992 17.064 5.016 17.256 ;
    END
  END do0[52]
  PIN do0[53]
    DIRECTION OUTPUT ;
    USE SIGNAL ;
    PORT
      LAYER M5 ;
        RECT  5.04 17.064 5.064 17.256 ;
    END
  END do0[53]
  PIN do0[54]
    DIRECTION OUTPUT ;
    USE SIGNAL ;
    PORT
      LAYER M5 ;
        RECT  5.088 17.064 5.112 17.256 ;
    END
  END do0[54]
  PIN do0[55]
    DIRECTION OUTPUT ;
    USE SIGNAL ;
    PORT
      LAYER M5 ;
        RECT  5.136 17.064 5.16 17.256 ;
    END
  END do0[55]
  PIN do0[56]
    DIRECTION OUTPUT ;
    USE SIGNAL ;
    PORT
      LAYER M5 ;
        RECT  5.184 17.064 5.208 17.256 ;
    END
  END do0[56]
  PIN do0[57]
    DIRECTION OUTPUT ;
    USE SIGNAL ;
    PORT
      LAYER M5 ;
        RECT  5.232 17.064 5.256 17.256 ;
    END
  END do0[57]
  PIN do0[58]
    DIRECTION OUTPUT ;
    USE SIGNAL ;
    PORT
      LAYER M5 ;
        RECT  5.28 17.064 5.304 17.256 ;
    END
  END do0[58]
  PIN do0[59]
    DIRECTION OUTPUT ;
    USE SIGNAL ;
    PORT
      LAYER M5 ;
        RECT  5.328 17.064 5.352 17.256 ;
    END
  END do0[59]
  PIN do0[5]
    DIRECTION OUTPUT ;
    USE SIGNAL ;
    PORT
      LAYER M5 ;
        RECT  2.736 17.064 2.76 17.256 ;
    END
  END do0[5]
  PIN do0[60]
    DIRECTION OUTPUT ;
    USE SIGNAL ;
    PORT
      LAYER M5 ;
        RECT  5.376 17.064 5.4 17.256 ;
    END
  END do0[60]
  PIN do0[61]
    DIRECTION OUTPUT ;
    USE SIGNAL ;
    PORT
      LAYER M5 ;
        RECT  5.424 17.064 5.448 17.256 ;
    END
  END do0[61]
  PIN do0[62]
    DIRECTION OUTPUT ;
    USE SIGNAL ;
    PORT
      LAYER M5 ;
        RECT  5.472 17.064 5.496 17.256 ;
    END
  END do0[62]
  PIN do0[63]
    DIRECTION OUTPUT ;
    USE SIGNAL ;
    PORT
      LAYER M5 ;
        RECT  5.52 17.064 5.544 17.256 ;
    END
  END do0[63]
  PIN do0[64]
    DIRECTION OUTPUT ;
    USE SIGNAL ;
    PORT
      LAYER M5 ;
        RECT  5.568 17.064 5.592 17.256 ;
    END
  END do0[64]
  PIN do0[65]
    DIRECTION OUTPUT ;
    USE SIGNAL ;
    PORT
      LAYER M5 ;
        RECT  5.616 17.064 5.64 17.256 ;
    END
  END do0[65]
  PIN do0[66]
    DIRECTION OUTPUT ;
    USE SIGNAL ;
    PORT
      LAYER M5 ;
        RECT  5.664 17.064 5.688 17.256 ;
    END
  END do0[66]
  PIN do0[67]
    DIRECTION OUTPUT ;
    USE SIGNAL ;
    PORT
      LAYER M5 ;
        RECT  5.712 17.064 5.736 17.256 ;
    END
  END do0[67]
  PIN do0[68]
    DIRECTION OUTPUT ;
    USE SIGNAL ;
    PORT
      LAYER M5 ;
        RECT  5.76 17.064 5.784 17.256 ;
    END
  END do0[68]
  PIN do0[69]
    DIRECTION OUTPUT ;
    USE SIGNAL ;
    PORT
      LAYER M5 ;
        RECT  5.808 17.064 5.832 17.256 ;
    END
  END do0[69]
  PIN do0[6]
    DIRECTION OUTPUT ;
    USE SIGNAL ;
    PORT
      LAYER M5 ;
        RECT  2.784 17.064 2.808 17.256 ;
    END
  END do0[6]
  PIN do0[70]
    DIRECTION OUTPUT ;
    USE SIGNAL ;
    PORT
      LAYER M5 ;
        RECT  5.856 17.064 5.88 17.256 ;
    END
  END do0[70]
  PIN do0[71]
    DIRECTION OUTPUT ;
    USE SIGNAL ;
    PORT
      LAYER M5 ;
        RECT  5.904 17.064 5.928 17.256 ;
    END
  END do0[71]
  PIN do0[72]
    DIRECTION OUTPUT ;
    USE SIGNAL ;
    PORT
      LAYER M5 ;
        RECT  5.952 17.064 5.976 17.256 ;
    END
  END do0[72]
  PIN do0[73]
    DIRECTION OUTPUT ;
    USE SIGNAL ;
    PORT
      LAYER M5 ;
        RECT  6 17.064 6.024 17.256 ;
    END
  END do0[73]
  PIN do0[74]
    DIRECTION OUTPUT ;
    USE SIGNAL ;
    PORT
      LAYER M5 ;
        RECT  6.048 17.064 6.072 17.256 ;
    END
  END do0[74]
  PIN do0[75]
    DIRECTION OUTPUT ;
    USE SIGNAL ;
    PORT
      LAYER M5 ;
        RECT  6.096 17.064 6.12 17.256 ;
    END
  END do0[75]
  PIN do0[76]
    DIRECTION OUTPUT ;
    USE SIGNAL ;
    PORT
      LAYER M5 ;
        RECT  6.144 17.064 6.168 17.256 ;
    END
  END do0[76]
  PIN do0[77]
    DIRECTION OUTPUT ;
    USE SIGNAL ;
    PORT
      LAYER M5 ;
        RECT  6.192 17.064 6.216 17.256 ;
    END
  END do0[77]
  PIN do0[78]
    DIRECTION OUTPUT ;
    USE SIGNAL ;
    PORT
      LAYER M5 ;
        RECT  6.24 17.064 6.264 17.256 ;
    END
  END do0[78]
  PIN do0[79]
    DIRECTION OUTPUT ;
    USE SIGNAL ;
    PORT
      LAYER M5 ;
        RECT  6.288 17.064 6.312 17.256 ;
    END
  END do0[79]
  PIN do0[7]
    DIRECTION OUTPUT ;
    USE SIGNAL ;
    PORT
      LAYER M5 ;
        RECT  2.832 17.064 2.856 17.256 ;
    END
  END do0[7]
  PIN do0[80]
    DIRECTION OUTPUT ;
    USE SIGNAL ;
    PORT
      LAYER M5 ;
        RECT  6.336 17.064 6.36 17.256 ;
    END
  END do0[80]
  PIN do0[81]
    DIRECTION OUTPUT ;
    USE SIGNAL ;
    PORT
      LAYER M5 ;
        RECT  6.384 17.064 6.408 17.256 ;
    END
  END do0[81]
  PIN do0[82]
    DIRECTION OUTPUT ;
    USE SIGNAL ;
    PORT
      LAYER M5 ;
        RECT  6.432 17.064 6.456 17.256 ;
    END
  END do0[82]
  PIN do0[83]
    DIRECTION OUTPUT ;
    USE SIGNAL ;
    PORT
      LAYER M5 ;
        RECT  6.48 17.064 6.504 17.256 ;
    END
  END do0[83]
  PIN do0[84]
    DIRECTION OUTPUT ;
    USE SIGNAL ;
    PORT
      LAYER M5 ;
        RECT  6.528 17.064 6.552 17.256 ;
    END
  END do0[84]
  PIN do0[85]
    DIRECTION OUTPUT ;
    USE SIGNAL ;
    PORT
      LAYER M5 ;
        RECT  6.576 17.064 6.6 17.256 ;
    END
  END do0[85]
  PIN do0[86]
    DIRECTION OUTPUT ;
    USE SIGNAL ;
    PORT
      LAYER M5 ;
        RECT  6.624 17.064 6.648 17.256 ;
    END
  END do0[86]
  PIN do0[87]
    DIRECTION OUTPUT ;
    USE SIGNAL ;
    PORT
      LAYER M5 ;
        RECT  6.672 17.064 6.696 17.256 ;
    END
  END do0[87]
  PIN do0[88]
    DIRECTION OUTPUT ;
    USE SIGNAL ;
    PORT
      LAYER M5 ;
        RECT  6.72 17.064 6.744 17.256 ;
    END
  END do0[88]
  PIN do0[89]
    DIRECTION OUTPUT ;
    USE SIGNAL ;
    PORT
      LAYER M5 ;
        RECT  6.768 17.064 6.792 17.256 ;
    END
  END do0[89]
  PIN do0[8]
    DIRECTION OUTPUT ;
    USE SIGNAL ;
    PORT
      LAYER M5 ;
        RECT  2.88 17.064 2.904 17.256 ;
    END
  END do0[8]
  PIN do0[90]
    DIRECTION OUTPUT ;
    USE SIGNAL ;
    PORT
      LAYER M5 ;
        RECT  6.816 17.064 6.84 17.256 ;
    END
  END do0[90]
  PIN do0[91]
    DIRECTION OUTPUT ;
    USE SIGNAL ;
    PORT
      LAYER M5 ;
        RECT  6.864 17.064 6.888 17.256 ;
    END
  END do0[91]
  PIN do0[92]
    DIRECTION OUTPUT ;
    USE SIGNAL ;
    PORT
      LAYER M5 ;
        RECT  6.912 17.064 6.936 17.256 ;
    END
  END do0[92]
  PIN do0[93]
    DIRECTION OUTPUT ;
    USE SIGNAL ;
    PORT
      LAYER M5 ;
        RECT  6.96 17.064 6.984 17.256 ;
    END
  END do0[93]
  PIN do0[94]
    DIRECTION OUTPUT ;
    USE SIGNAL ;
    PORT
      LAYER M5 ;
        RECT  7.008 17.064 7.032 17.256 ;
    END
  END do0[94]
  PIN do0[95]
    DIRECTION OUTPUT ;
    USE SIGNAL ;
    PORT
      LAYER M5 ;
        RECT  7.056 17.064 7.08 17.256 ;
    END
  END do0[95]
  PIN do0[96]
    DIRECTION OUTPUT ;
    USE SIGNAL ;
    PORT
      LAYER M5 ;
        RECT  7.104 17.064 7.128 17.256 ;
    END
  END do0[96]
  PIN do0[97]
    DIRECTION OUTPUT ;
    USE SIGNAL ;
    PORT
      LAYER M5 ;
        RECT  7.152 17.064 7.176 17.256 ;
    END
  END do0[97]
  PIN do0[98]
    DIRECTION OUTPUT ;
    USE SIGNAL ;
    PORT
      LAYER M5 ;
        RECT  7.2 17.064 7.224 17.256 ;
    END
  END do0[98]
  PIN do0[99]
    DIRECTION OUTPUT ;
    USE SIGNAL ;
    PORT
      LAYER M5 ;
        RECT  7.248 17.064 7.272 17.256 ;
    END
  END do0[99]
  PIN do0[9]
    DIRECTION OUTPUT ;
    USE SIGNAL ;
    PORT
      LAYER M5 ;
        RECT  2.928 17.064 2.952 17.256 ;
    END
  END do0[9]
  PIN fi0[0]
    DIRECTION INPUT ;
    USE SIGNAL ;
    PORT
      LAYER M5 ;
        RECT  2.304 0 2.328 0.192 ;
    END
  END fi0[0]
  PIN fo0[0]
    DIRECTION OUTPUT ;
    USE SIGNAL ;
    PORT
      LAYER M5 ;
        RECT  2.304 17.064 2.328 17.256 ;
    END
  END fo0[0]
  PIN VDD
    DIRECTION INOUT ;
    USE POWER ;
    PORT
      LAYER M7 ;
        RECT  27.856 0.531 28.144 16.479 ;
        RECT  17.056 0.531 17.344 16.479 ;
        RECT  6.256 0.531 6.544 16.479 ;
      LAYER M6 ;
        RECT  0 12.372 0.032 12.66 ;
        RECT  0 6.972 0.032 7.26 ;
        RECT  0 1.572 0.032 1.86 ;
      LAYER M2 ;
        RECT  0 16.461 0.018 16.479 ;
        RECT  0 15.921 0.018 15.939 ;
        RECT  0 15.381 0.018 15.399 ;
        RECT  0 14.841 0.018 14.859 ;
        RECT  0 14.301 0.018 14.319 ;
        RECT  0 13.761 0.018 13.779 ;
        RECT  0 13.221 0.018 13.239 ;
        RECT  0 12.681 0.018 12.699 ;
        RECT  0 12.141 0.018 12.159 ;
        RECT  0 11.601 0.018 11.619 ;
        RECT  0 11.061 0.018 11.079 ;
        RECT  0 10.521 0.018 10.539 ;
        RECT  0 9.981 0.018 9.999 ;
        RECT  0 9.441 0.018 9.459 ;
        RECT  0 8.901 0.018 8.919 ;
        RECT  0 8.361 0.018 8.379 ;
        RECT  0 7.821 0.018 7.839 ;
        RECT  0 7.281 0.018 7.299 ;
        RECT  0 6.741 0.018 6.759 ;
        RECT  0 6.201 0.018 6.219 ;
        RECT  0 5.661 0.018 5.679 ;
        RECT  0 5.121 0.018 5.139 ;
        RECT  0 4.581 0.018 4.599 ;
        RECT  0 4.041 0.018 4.059 ;
        RECT  0 3.501 0.018 3.519 ;
        RECT  0 2.961 0.018 2.979 ;
        RECT  0 2.421 0.018 2.439 ;
        RECT  0 1.881 0.018 1.899 ;
        RECT  0 1.341 0.018 1.359 ;
        RECT  0 0.801 0.018 0.819 ;
      LAYER M1 ;
        RECT  0 16.461 0.018 16.479 ;
        RECT  0 15.921 0.018 15.939 ;
        RECT  0 15.381 0.018 15.399 ;
        RECT  0 14.841 0.018 14.859 ;
        RECT  0 14.301 0.018 14.319 ;
        RECT  0 13.761 0.018 13.779 ;
        RECT  0 13.221 0.018 13.239 ;
        RECT  0 12.681 0.018 12.699 ;
        RECT  0 12.141 0.018 12.159 ;
        RECT  0 11.601 0.018 11.619 ;
        RECT  0 11.061 0.018 11.079 ;
        RECT  0 10.521 0.018 10.539 ;
        RECT  0 9.981 0.018 9.999 ;
        RECT  0 9.441 0.018 9.459 ;
        RECT  0 8.901 0.018 8.919 ;
        RECT  0 8.361 0.018 8.379 ;
        RECT  0 7.821 0.018 7.839 ;
        RECT  0 7.281 0.018 7.299 ;
        RECT  0 6.741 0.018 6.759 ;
        RECT  0 6.201 0.018 6.219 ;
        RECT  0 5.661 0.018 5.679 ;
        RECT  0 5.121 0.018 5.139 ;
        RECT  0 4.581 0.018 4.599 ;
        RECT  0 4.041 0.018 4.059 ;
        RECT  0 3.501 0.018 3.519 ;
        RECT  0 2.961 0.018 2.979 ;
        RECT  0 2.421 0.018 2.439 ;
        RECT  0 1.881 0.018 1.899 ;
        RECT  0 1.341 0.018 1.359 ;
        RECT  0 0.801 0.018 0.819 ;
    END
  END VDD
  PIN VSS
    DIRECTION INOUT ;
    USE GROUND ;
    PORT
      LAYER M7 ;
        RECT  22.456 0.531 22.744 16.479 ;
        RECT  11.656 0.531 11.944 16.479 ;
        RECT  0.856 0.531 1.144 16.479 ;
      LAYER M6 ;
        RECT  0 11.796 0.032 12.084 ;
        RECT  0 6.396 0.032 6.684 ;
        RECT  0 0.996 0.032 1.284 ;
      LAYER M2 ;
        RECT  0 16.191 0.018 16.209 ;
        RECT  0 15.651 0.018 15.669 ;
        RECT  0 15.111 0.018 15.129 ;
        RECT  0 14.571 0.018 14.589 ;
        RECT  0 14.031 0.018 14.049 ;
        RECT  0 13.491 0.018 13.509 ;
        RECT  0 12.951 0.018 12.969 ;
        RECT  0 12.411 0.018 12.429 ;
        RECT  0 11.871 0.018 11.889 ;
        RECT  0 11.331 0.018 11.349 ;
        RECT  0 10.791 0.018 10.809 ;
        RECT  0 10.251 0.018 10.269 ;
        RECT  0 9.711 0.018 9.729 ;
        RECT  0 9.171 0.018 9.189 ;
        RECT  0 8.631 0.018 8.649 ;
        RECT  0 8.091 0.018 8.109 ;
        RECT  0 7.551 0.018 7.569 ;
        RECT  0 7.011 0.018 7.029 ;
        RECT  0 6.471 0.018 6.489 ;
        RECT  0 5.931 0.018 5.949 ;
        RECT  0 5.391 0.018 5.409 ;
        RECT  0 4.851 0.018 4.869 ;
        RECT  0 4.311 0.018 4.329 ;
        RECT  0 3.771 0.018 3.789 ;
        RECT  0 3.231 0.018 3.249 ;
        RECT  0 2.691 0.018 2.709 ;
        RECT  0 2.151 0.018 2.169 ;
        RECT  0 1.611 0.018 1.629 ;
        RECT  0 1.071 0.018 1.089 ;
        RECT  0 0.531 0.018 0.549 ;
      LAYER M1 ;
        RECT  0 16.191 0.018 16.209 ;
        RECT  0 15.651 0.018 15.669 ;
        RECT  0 15.111 0.018 15.129 ;
        RECT  0 14.571 0.018 14.589 ;
        RECT  0 14.031 0.018 14.049 ;
        RECT  0 13.491 0.018 13.509 ;
        RECT  0 12.951 0.018 12.969 ;
        RECT  0 12.411 0.018 12.429 ;
        RECT  0 11.871 0.018 11.889 ;
        RECT  0 11.331 0.018 11.349 ;
        RECT  0 10.791 0.018 10.809 ;
        RECT  0 10.251 0.018 10.269 ;
        RECT  0 9.711 0.018 9.729 ;
        RECT  0 9.171 0.018 9.189 ;
        RECT  0 8.631 0.018 8.649 ;
        RECT  0 8.091 0.018 8.109 ;
        RECT  0 7.551 0.018 7.569 ;
        RECT  0 7.011 0.018 7.029 ;
        RECT  0 6.471 0.018 6.489 ;
        RECT  0 5.931 0.018 5.949 ;
        RECT  0 5.391 0.018 5.409 ;
        RECT  0 4.851 0.018 4.869 ;
        RECT  0 4.311 0.018 4.329 ;
        RECT  0 3.771 0.018 3.789 ;
        RECT  0 3.231 0.018 3.249 ;
        RECT  0 2.691 0.018 2.709 ;
        RECT  0 2.151 0.018 2.169 ;
        RECT  0 1.611 0.018 1.629 ;
        RECT  0 1.071 0.018 1.089 ;
        RECT  0 0.531 0.018 0.549 ;
    END
  END VSS
  OBS
    LAYER RVTN ;
     RECT  0 0.54 29.322 0.675 ;
     RECT  0 0.945 29.322 1.215 ;
     RECT  0 1.485 29.322 1.755 ;
     RECT  0 2.025 29.322 2.295 ;
     RECT  0 2.565 29.322 2.835 ;
     RECT  0 3.105 29.322 3.375 ;
     RECT  0 3.645 29.322 3.915 ;
     RECT  0 4.185 29.322 4.455 ;
     RECT  0 4.725 29.322 4.995 ;
     RECT  0 5.265 29.322 5.535 ;
     RECT  0 5.805 29.322 6.075 ;
     RECT  0 6.345 29.322 6.615 ;
     RECT  0 6.885 29.322 7.155 ;
     RECT  0 7.425 29.322 7.695 ;
     RECT  0 7.965 29.322 8.235 ;
     RECT  0 8.505 29.322 8.775 ;
     RECT  0 9.045 29.322 9.315 ;
     RECT  0 9.585 29.322 9.855 ;
     RECT  0 10.125 29.322 10.395 ;
     RECT  0 10.665 29.322 10.935 ;
     RECT  0 11.205 29.322 11.475 ;
     RECT  0 11.745 29.322 12.015 ;
     RECT  0 12.285 29.322 12.555 ;
     RECT  0 12.825 29.322 13.095 ;
     RECT  0 13.365 29.322 13.635 ;
     RECT  0 13.905 29.322 14.175 ;
     RECT  0 14.445 29.322 14.715 ;
     RECT  0 14.985 29.322 15.255 ;
     RECT  0 15.525 29.322 15.795 ;
     RECT  0 16.065 29.322 16.335 ;
    LAYER RVTP ;
     RECT  0 0.675 29.322 0.945 ;
     RECT  0 1.215 29.322 1.485 ;
     RECT  0 1.755 29.322 2.025 ;
     RECT  0 2.295 29.322 2.565 ;
     RECT  0 2.835 29.322 3.105 ;
     RECT  0 3.375 29.322 3.645 ;
     RECT  0 3.915 29.322 4.185 ;
     RECT  0 4.455 29.322 4.725 ;
     RECT  0 4.995 29.322 5.265 ;
     RECT  0 5.535 29.322 5.805 ;
     RECT  0 6.075 29.322 6.345 ;
     RECT  0 6.615 29.322 6.885 ;
     RECT  0 7.155 29.322 7.425 ;
     RECT  0 7.695 29.322 7.965 ;
     RECT  0 8.235 29.322 8.505 ;
     RECT  0 8.775 29.322 9.045 ;
     RECT  0 9.315 29.322 9.585 ;
     RECT  0 9.855 29.322 10.125 ;
     RECT  0 10.395 29.322 10.665 ;
     RECT  0 10.935 29.322 11.205 ;
     RECT  0 11.475 29.322 11.745 ;
     RECT  0 12.015 29.322 12.285 ;
     RECT  0 12.555 29.322 12.825 ;
     RECT  0 13.095 29.322 13.365 ;
     RECT  0 13.635 29.322 13.905 ;
     RECT  0 14.175 29.322 14.445 ;
     RECT  0 14.715 29.322 14.985 ;
     RECT  0 15.255 29.322 15.525 ;
     RECT  0 15.795 29.322 16.065 ;
     RECT  0 16.335 29.322 16.47 ;
    LAYER M1 ;
     RECT  0 0.531 29.322 16.479 ;
    LAYER M2 ;
     RECT  0 0.531 21.811 16.479 ;
     RECT  21.811 0.414 21.911 16.479 ;
     RECT  21.911 0.531 21.955 16.479 ;
     RECT  21.955 0.531 23.063 16.524 ;
     RECT  23.063 0.531 25.015 16.479 ;
     RECT  25.015 0.531 25.547 16.524 ;
     RECT  25.547 0.531 26.527 16.479 ;
     RECT  26.527 0.531 27.059 16.524 ;
     RECT  27.059 0.531 29.322 16.479 ;
    LAYER M3 ;
     RECT  11.232 0.187 11.25 0.283 ;
     RECT  16.344 0.187 16.362 0.283 ;
     RECT  20.34 0.187 20.358 0.283 ;
     RECT  12.744 0.283 12.762 0.331 ;
     RECT  13.896 0.283 17.802 0.379 ;
     RECT  25.632 0.283 27.018 0.379 ;
     RECT  2.376 0.283 2.394 0.475 ;
     RECT  3.204 0.283 11.25 0.475 ;
     RECT  12.744 0.331 13.05 0.475 ;
     RECT  2.376 0.475 11.25 0.523 ;
     RECT  25.308 0.379 27.018 0.523 ;
     RECT  2.376 0.523 11.286 0.571 ;
     RECT  12.636 0.475 13.05 0.571 ;
     RECT  13.896 0.379 18.018 0.571 ;
     RECT  19.188 0.283 24.174 0.571 ;
     RECT  25.308 0.523 27.345 0.571 ;
     RECT  19.188 0.571 27.345 0.751 ;
     RECT  1.476 0.751 1.494 0.763 ;
     RECT  2.34 0.571 18.234 0.763 ;
     RECT  0.255 0.523 0.345 0.793 ;
     RECT  0.255 0.793 0.537 0.985 ;
     RECT  1.476 0.763 18.234 0.985 ;
     RECT  0.255 0.985 18.234 1.021 ;
     RECT  19.188 0.751 28.062 1.021 ;
     RECT  0.255 1.021 18.342 1.139 ;
     RECT  1.584 1.139 18.342 1.147 ;
     RECT  19.188 1.021 28.17 1.147 ;
     RECT  1.584 1.147 28.17 1.291 ;
     RECT  1.584 1.291 28.422 1.319 ;
     RECT  0.255 1.139 0.846 1.679 ;
     RECT  1.584 1.319 6.93 2.101 ;
     RECT  7.668 1.319 28.422 2.101 ;
     RECT  0.255 1.679 0.537 2.767 ;
     RECT  1.512 2.101 28.422 2.767 ;
     RECT  0.255 2.767 28.422 3.335 ;
     RECT  1.584 3.335 28.422 4.765 ;
     RECT  1.548 4.765 28.422 4.955 ;
     RECT  1.584 4.955 28.422 7.963 ;
     RECT  1.404 7.963 28.422 8.159 ;
     RECT  1.584 8.159 28.422 13.901 ;
     RECT  0.255 3.335 0.537 14.143 ;
     RECT  1.584 13.901 28.35 14.143 ;
     RECT  0.255 14.143 28.35 14.639 ;
     RECT  1.728 14.639 28.35 15.899 ;
     RECT  1.8 15.899 28.35 15.989 ;
     RECT  0.255 14.639 0.537 16.217 ;
     RECT  1.8 15.989 28.314 16.259 ;
     RECT  2.088 16.259 28.314 16.295 ;
     RECT  2.124 16.295 28.314 16.301 ;
     RECT  2.124 16.301 28.278 16.331 ;
     RECT  0.447 16.217 0.537 16.487 ;
     RECT  2.124 16.331 28.026 16.529 ;
     RECT  2.124 16.529 25.326 16.589 ;
     RECT  2.124 16.589 11.79 16.637 ;
     RECT  12.672 16.589 25.326 16.637 ;
     RECT  26.064 16.529 28.026 16.637 ;
     RECT  2.124 16.637 7.974 16.685 ;
     RECT  8.856 16.637 11.79 16.685 ;
     RECT  12.672 16.637 15.894 16.685 ;
     RECT  16.812 16.637 18.774 16.685 ;
     RECT  19.584 16.637 20.502 16.685 ;
     RECT  23.832 16.637 25.326 16.685 ;
     RECT  26.064 16.637 26.514 16.685 ;
     RECT  27.324 16.637 28.026 16.685 ;
     RECT  2.124 16.685 2.97 16.733 ;
     RECT  4.428 16.685 6.39 16.733 ;
     RECT  7.956 16.685 7.974 16.733 ;
     RECT  9.108 16.685 11.43 16.733 ;
     RECT  12.744 16.685 13.662 16.733 ;
     RECT  14.688 16.685 15.894 16.733 ;
     RECT  21.312 16.637 22.986 16.733 ;
     RECT  24.336 16.685 25.326 16.733 ;
     RECT  26.496 16.685 26.514 16.733 ;
     RECT  2.124 16.733 2.79 16.781 ;
     RECT  4.5 16.733 4.986 16.781 ;
     RECT  5.976 16.733 6.39 16.781 ;
     RECT  9.108 16.733 9.306 16.781 ;
     RECT  10.404 16.733 11.43 16.781 ;
     RECT  16.812 16.685 18.738 16.781 ;
     RECT  19.584 16.685 20.034 16.781 ;
     RECT  25.02 16.733 25.038 16.781 ;
     RECT  2.772 16.781 2.79 16.829 ;
     RECT  6.012 16.781 6.39 16.829 ;
     RECT  9.288 16.781 9.306 16.829 ;
     RECT  10.404 16.781 10.998 16.829 ;
     RECT  12.96 16.733 12.978 16.829 ;
     RECT  15.444 16.733 15.858 16.829 ;
     RECT  16.92 16.781 18.738 16.829 ;
     RECT  21.816 16.733 22.734 16.829 ;
     RECT  4.536 16.781 4.554 16.877 ;
     RECT  6.012 16.829 6.102 16.877 ;
     RECT  17.028 16.829 18.738 16.877 ;
     RECT  19.62 16.781 20.034 16.877 ;
     RECT  21.96 16.829 22.734 16.877 ;
     RECT  6.084 16.877 6.102 16.925 ;
     RECT  10.98 16.829 10.998 16.925 ;
     RECT  17.496 16.877 18.738 16.925 ;
     RECT  19.872 16.877 20.034 16.925 ;
     RECT  22.212 16.877 22.734 16.925 ;
     RECT  17.748 16.925 18.738 16.973 ;
     RECT  22.212 16.925 22.23 16.973 ;
     RECT  28.008 16.685 28.026 16.973 ;
     RECT  15.84 16.829 15.858 17.069 ;
     RECT  20.016 16.925 20.034 17.069 ;
    LAYER M4 ;
     RECT  0.248 0.528 0.352 16.212 ;
     RECT  0.352 0.798 0.44 16.212 ;
     RECT  0.44 0.798 0.544 16.482 ;
     RECT  0.544 7.968 2.005 7.992 ;
     RECT  1.789 16.032 2.005 16.056 ;
     RECT  1.933 2.256 2.077 2.28 ;
     RECT  2.005 7.44 2.089 7.992 ;
     RECT  2.005 16.032 2.113 16.248 ;
     RECT  2.185 0.768 2.293 0.792 ;
     RECT  2.113 14.208 2.293 14.232 ;
     RECT  2.293 14.208 2.339 14.856 ;
     RECT  2.293 0.192 2.435 1.176 ;
     RECT  2.339 14.784 2.441 14.856 ;
     RECT  2.441 14.832 2.473 14.856 ;
     RECT  2.113 16.032 2.473 16.776 ;
     RECT  2.089 7.92 2.509 7.992 ;
     RECT  2.473 10.32 2.509 10.344 ;
     RECT  2.437 3.984 2.531 4.008 ;
     RECT  2.437 12.192 2.627 13.32 ;
     RECT  2.077 2.256 2.636 2.904 ;
     RECT  1.933 9.072 2.653 9.096 ;
     RECT  2.636 2.256 2.723 3.432 ;
     RECT  2.653 9.024 2.725 9.096 ;
     RECT  2.473 14.832 2.761 16.776 ;
     RECT  2.725 5.712 2.819 5.736 ;
     RECT  2.725 9.024 2.869 9.192 ;
     RECT  2.509 10.32 2.869 10.872 ;
     RECT  2.435 0.288 2.941 1.176 ;
     RECT  2.723 2.256 2.941 3.384 ;
     RECT  2.761 14.832 2.963 16.824 ;
     RECT  2.509 7.92 3.193 8.04 ;
     RECT  2.869 9.024 3.193 10.872 ;
     RECT  3.193 7.92 3.301 10.872 ;
     RECT  3.229 6.816 3.349 6.84 ;
     RECT  3.301 7.92 3.349 11.448 ;
     RECT  3.349 6.816 3.385 11.448 ;
     RECT  2.627 12.528 3.404 13.32 ;
     RECT  2.963 14.832 3.404 16.728 ;
     RECT  2.941 0.288 3.413 3.384 ;
     RECT  3.385 6.816 3.443 11.064 ;
     RECT  3.404 12.528 3.521 16.728 ;
     RECT  3.521 13.152 3.601 16.728 ;
     RECT  3.601 14.112 3.809 16.728 ;
     RECT  3.809 14.208 3.853 16.728 ;
     RECT  3.443 6.816 4.025 7.944 ;
     RECT  3.413 0.288 4.211 2.856 ;
     RECT  4.211 0.288 4.259 2.568 ;
     RECT  3.853 15.984 4.261 16.728 ;
     RECT  3.925 4.512 4.345 4.536 ;
     RECT  3.443 9.072 4.393 11.064 ;
     RECT  4.025 7.344 4.489 7.944 ;
     RECT  4.393 9.072 4.489 10.248 ;
     RECT  4.261 15.984 4.565 16.872 ;
     RECT  4.489 7.344 4.573 10.248 ;
     RECT  4.345 4.416 4.885 5.16 ;
     RECT  4.885 4.416 5.065 6.024 ;
     RECT  4.573 7.344 5.065 8.04 ;
     RECT  3.853 14.208 5.201 15 ;
     RECT  4.565 15.984 5.201 16.776 ;
     RECT  4.921 12.192 5.209 12.216 ;
     RECT  4.259 0.288 5.317 2.28 ;
     RECT  5.065 4.416 5.317 8.04 ;
     RECT  4.573 9.072 5.425 10.248 ;
     RECT  5.209 12.192 5.509 13.176 ;
     RECT  5.201 14.208 5.509 16.776 ;
     RECT  5.317 0.288 5.648 2.904 ;
     RECT  5.317 3.936 5.648 8.04 ;
     RECT  5.425 9.072 5.648 10.296 ;
     RECT  5.509 12.192 5.648 16.776 ;
     RECT  5.648 0.288 5.941 16.776 ;
     RECT  5.941 0.288 5.944 16.872 ;
     RECT  5.944 13.056 6.04 16.872 ;
     RECT  5.944 6.288 6.121 11.448 ;
     RECT  6.04 13.056 6.179 16.92 ;
     RECT  6.179 13.056 6.401 16.824 ;
     RECT  5.944 2.256 6.473 5.208 ;
     RECT  6.121 6.288 6.581 11.4 ;
     RECT  6.473 3.264 6.611 5.208 ;
     RECT  6.401 13.056 6.653 16.68 ;
     RECT  6.581 6.72 6.689 11.4 ;
     RECT  6.689 6.72 6.761 9.72 ;
     RECT  6.689 10.848 6.833 11.4 ;
     RECT  6.653 13.056 6.995 13.128 ;
     RECT  6.611 3.312 7.045 5.208 ;
     RECT  6.833 10.848 7.165 10.968 ;
     RECT  7.045 3.312 7.18 5.688 ;
     RECT  6.761 9.168 7.235 9.72 ;
     RECT  6.761 6.72 7.331 8.136 ;
     RECT  7.141 12 7.333 12.024 ;
     RECT  7.333 12 7.373 12.744 ;
     RECT  7.18 3.312 7.427 4.584 ;
     RECT  7.235 9.168 7.427 9.192 ;
     RECT  7.18 5.664 7.621 5.688 ;
     RECT  5.944 0.288 7.628 1.224 ;
     RECT  6.473 2.256 7.628 2.28 ;
     RECT  7.628 0.288 7.667 2.28 ;
     RECT  7.667 0.288 7.715 1.704 ;
     RECT  7.621 5.664 7.763 6.312 ;
     RECT  7.331 7.392 7.801 8.136 ;
     RECT  7.763 5.664 7.805 5.736 ;
     RECT  6.653 14.112 7.861 16.68 ;
     RECT  7.373 12.192 7.957 12.744 ;
     RECT  7.427 3.312 8.053 3.96 ;
     RECT  7.957 12.192 8.101 13.08 ;
     RECT  7.861 14.112 8.101 16.728 ;
     RECT  8.101 12.192 8.137 16.728 ;
     RECT  8.053 10.992 8.149 11.016 ;
     RECT  8.053 2.832 8.195 3.96 ;
     RECT  8.149 10.848 8.269 11.016 ;
     RECT  8.269 10.32 8.353 11.016 ;
     RECT  7.805 5.712 8.533 5.736 ;
     RECT  8.195 2.832 8.579 2.856 ;
     RECT  8.195 3.888 8.597 3.96 ;
     RECT  7.801 7.392 8.701 8.616 ;
     RECT  7.715 0.288 8.78 1.176 ;
     RECT  8.78 0.288 8.845 1.608 ;
     RECT  8.701 7.392 8.917 9.192 ;
     RECT  8.353 10.992 9.001 11.016 ;
     RECT  8.137 12.384 9.097 16.728 ;
     RECT  9.097 12.384 9.137 16.776 ;
     RECT  9.137 12.384 9.173 13.128 ;
     RECT  8.917 6.864 9.205 9.192 ;
     RECT  9.137 14.496 9.205 16.776 ;
     RECT  9.205 14.496 9.317 16.824 ;
     RECT  9.317 14.496 9.347 16.776 ;
     RECT  9.385 11.424 9.469 11.448 ;
     RECT  8.597 3.888 9.541 3.912 ;
     RECT  9.541 3.696 9.565 3.912 ;
     RECT  9.205 6.864 9.637 9.768 ;
     RECT  9.565 3.696 9.649 4.008 ;
     RECT  9.637 5.952 9.665 9.768 ;
     RECT  9.649 3.696 9.677 3.72 ;
     RECT  9.665 5.136 9.721 9.768 ;
     RECT  9.721 6.768 9.733 9.768 ;
     RECT  9.721 5.136 9.749 5.736 ;
     RECT  9.745 2.928 9.781 3.432 ;
     RECT  8.845 0.288 9.853 1.704 ;
     RECT  9.781 2.832 9.853 3.432 ;
     RECT  9.347 14.496 9.973 16.728 ;
     RECT  9.733 6.768 10.021 10.008 ;
     RECT  9.173 13.056 10.165 13.128 ;
     RECT  10.165 13.056 10.249 13.416 ;
     RECT  9.973 15.888 10.393 16.728 ;
     RECT  10.249 12.288 10.429 13.416 ;
     RECT  9.973 14.496 10.429 14.808 ;
     RECT  10.021 6.768 10.537 10.92 ;
     RECT  9.749 5.712 10.709 5.736 ;
     RECT  10.537 6.768 10.709 11.016 ;
     RECT  10.709 5.712 10.741 11.016 ;
     RECT  10.429 12.288 10.741 14.808 ;
     RECT  10.393 15.888 10.969 16.824 ;
     RECT  9.853 0.288 11.048 3.432 ;
     RECT  10.741 5.712 11.048 14.808 ;
     RECT  10.969 15.888 11.048 16.92 ;
     RECT  11.048 0.288 11.219 16.92 ;
     RECT  11.219 0.288 11.221 16.776 ;
     RECT  11.221 0.192 11.305 16.776 ;
     RECT  11.305 0.336 11.344 16.776 ;
     RECT  11.344 9.744 11.441 12.072 ;
     RECT  11.344 13.104 11.452 16.776 ;
     RECT  11.344 0.336 11.555 3.336 ;
     RECT  11.441 9.744 11.693 11.544 ;
     RECT  11.555 0.336 11.747 1.224 ;
     RECT  11.344 5.088 11.917 8.52 ;
     RECT  11.452 13.104 11.981 16.68 ;
     RECT  11.917 6.288 12.053 8.52 ;
     RECT  11.555 2.256 12.445 3.336 ;
     RECT  11.693 9.744 12.553 10.872 ;
     RECT  12.445 2.256 12.565 3.432 ;
     RECT  11.981 15.984 12.661 16.68 ;
     RECT  11.747 0.48 12.733 1.224 ;
     RECT  12.661 15.984 12.757 16.728 ;
     RECT  12.565 2.256 12.805 3.768 ;
     RECT  12.805 2.256 12.841 4.008 ;
     RECT  11.917 5.088 12.841 5.16 ;
     RECT  12.553 9.648 12.877 10.872 ;
     RECT  12.661 11.952 12.877 11.976 ;
     RECT  12.841 2.256 12.925 5.16 ;
     RECT  12.877 9.648 12.949 11.976 ;
     RECT  11.981 13.104 12.949 14.76 ;
     RECT  12.757 15.984 12.989 16.824 ;
     RECT  12.949 9.168 13.033 11.976 ;
     RECT  12.949 13.104 13.06 14.856 ;
     RECT  12.925 5.088 13.093 5.16 ;
     RECT  12.053 6.288 13.093 7.608 ;
     RECT  13.06 13.104 13.129 14.904 ;
     RECT  13.033 9.408 13.133 11.976 ;
     RECT  13.093 5.088 13.177 7.608 ;
     RECT  13.133 11.376 13.237 11.976 ;
     RECT  13.129 13.056 13.237 14.904 ;
     RECT  13.237 11.376 13.349 14.904 ;
     RECT  12.733 0.288 13.453 1.224 ;
     RECT  12.925 2.256 13.453 4.008 ;
     RECT  13.349 11.376 13.457 13.08 ;
     RECT  13.133 9.408 13.501 10.344 ;
     RECT  13.349 14.208 13.573 14.904 ;
     RECT  12.989 15.984 13.573 16.728 ;
     RECT  13.453 0.288 13.609 4.008 ;
     RECT  13.177 5.472 13.628 7.608 ;
     RECT  13.628 5.472 13.715 8.376 ;
     RECT  13.609 0.288 13.9 3.816 ;
     RECT  13.9 0.288 14.099 3.432 ;
     RECT  13.457 11.376 14.101 11.448 ;
     RECT  13.715 5.472 14.105 8.04 ;
     RECT  13.457 12.528 14.177 13.08 ;
     RECT  13.501 9.408 14.195 9.768 ;
     RECT  14.101 10.848 14.257 11.448 ;
     RECT  14.195 9.408 14.317 9.672 ;
     RECT  14.177 12.528 14.429 12.744 ;
     RECT  14.105 5.472 14.497 7.992 ;
     RECT  14.429 12.528 14.497 12.552 ;
     RECT  14.317 9.12 14.675 9.672 ;
     RECT  14.257 10.848 14.819 10.872 ;
     RECT  14.099 0.288 15.109 0.6 ;
     RECT  14.099 1.584 15.109 3.432 ;
     RECT  14.497 5.088 15.289 7.992 ;
     RECT  14.497 12.288 15.301 12.552 ;
     RECT  14.675 9.648 15.317 9.672 ;
     RECT  15.109 0.288 15.337 3.432 ;
     RECT  15.289 5.088 15.401 8.04 ;
     RECT  13.573 14.208 15.433 16.728 ;
     RECT  15.301 11.568 15.437 12.552 ;
     RECT  15.337 0.288 15.443 3.384 ;
     RECT  15.433 14.208 15.443 16.824 ;
     RECT  15.401 5.088 15.577 5.688 ;
     RECT  15.401 6.864 15.577 8.04 ;
     RECT  15.443 14.688 15.781 16.824 ;
     RECT  15.781 14.688 15.869 17.064 ;
     RECT  15.577 6.864 16.189 8.568 ;
     RECT  15.317 9.648 16.189 10.344 ;
     RECT  15.721 13.104 16.189 13.176 ;
     RECT  16.189 6.864 16.225 10.344 ;
     RECT  16.189 11.424 16.225 11.544 ;
     RECT  15.443 0.288 16.333 1.752 ;
     RECT  16.333 0.192 16.448 1.752 ;
     RECT  15.443 2.88 16.448 3.384 ;
     RECT  15.577 4.56 16.448 5.688 ;
     RECT  16.225 6.864 16.448 11.544 ;
     RECT  16.189 13.104 16.448 13.704 ;
     RECT  15.869 14.688 16.448 16.872 ;
     RECT  16.448 0.192 16.739 16.872 ;
     RECT  16.739 0.288 16.744 16.872 ;
     RECT  16.744 5.136 16.885 8.664 ;
     RECT  16.744 9.744 16.885 16.872 ;
     RECT  16.744 0.288 16.924 0.744 ;
     RECT  16.885 12 16.933 16.872 ;
     RECT  16.885 5.136 16.949 8.616 ;
     RECT  16.924 0.288 16.957 0.648 ;
     RECT  16.949 5.136 16.972 6.312 ;
     RECT  16.933 12 17.077 16.92 ;
     RECT  16.744 3.024 17.088 4.008 ;
     RECT  17.077 12 17.093 16.968 ;
     RECT  17.088 3.12 17.137 4.008 ;
     RECT  16.957 0.288 17.171 0.6 ;
     RECT  17.137 3.408 17.363 4.008 ;
     RECT  17.093 14.256 17.594 16.968 ;
     RECT  16.744 1.728 17.669 1.752 ;
     RECT  17.594 14.304 17.677 16.968 ;
     RECT  17.171 0.288 17.891 0.408 ;
     RECT  16.885 9.744 17.941 10.872 ;
     RECT  17.093 12 17.941 13.224 ;
     RECT  16.949 7.44 17.993 8.616 ;
     RECT  17.891 0.384 18.029 0.408 ;
     RECT  17.941 9.744 18.085 13.224 ;
     RECT  16.972 5.136 18.125 5.16 ;
     RECT  18.085 9.744 18.173 13.32 ;
     RECT  17.363 3.408 18.197 3.48 ;
     RECT  18.173 13.008 18.227 13.32 ;
     RECT  18.227 13.008 18.245 13.176 ;
     RECT  18.197 3.024 18.281 3.48 ;
     RECT  18.245 13.008 18.281 13.032 ;
     RECT  18.125 5.136 18.325 5.256 ;
     RECT  16.972 6.288 18.325 6.312 ;
     RECT  18.281 3.408 18.341 3.48 ;
     RECT  18.341 3.408 18.425 4.008 ;
     RECT  18.325 5.136 18.457 6.312 ;
     RECT  17.993 7.44 18.457 8.04 ;
     RECT  18.173 9.744 18.637 11.88 ;
     RECT  18.197 0.576 18.668 1.176 ;
     RECT  18.457 5.136 18.677 8.04 ;
     RECT  18.668 0.576 18.709 1.368 ;
     RECT  18.637 9.168 18.721 11.88 ;
     RECT  17.677 14.832 18.749 16.968 ;
     RECT  18.749 14.832 18.853 16.92 ;
     RECT  18.709 0.576 18.893 1.464 ;
     RECT  18.853 14.304 18.947 16.92 ;
     RECT  18.677 5.328 19.073 8.04 ;
     RECT  18.425 3.408 19.283 3.624 ;
     RECT  19.349 13.152 19.388 13.176 ;
     RECT  19.283 3.408 19.433 3.432 ;
     RECT  19.073 6.864 19.601 8.04 ;
     RECT  18.947 14.544 19.765 16.92 ;
     RECT  18.721 9.648 19.801 11.88 ;
     RECT  19.388 13.152 19.813 13.32 ;
     RECT  19.765 14.544 19.861 16.968 ;
     RECT  19.801 11.376 19.865 11.88 ;
     RECT  19.861 14.544 20.045 17.064 ;
     RECT  19.813 13.152 20.101 13.56 ;
     RECT  20.101 13.104 20.197 13.56 ;
     RECT  20.045 14.544 20.197 16.68 ;
     RECT  18.997 0.288 20.245 0.408 ;
     RECT  20.245 0.288 20.285 0.552 ;
     RECT  19.073 5.328 20.333 5.784 ;
     RECT  20.285 0.192 20.369 0.552 ;
     RECT  20.197 13.104 20.369 16.68 ;
     RECT  20.369 13.104 20.444 14.904 ;
     RECT  20.369 15.984 20.476 16.68 ;
     RECT  19.801 9.648 20.513 10.344 ;
     RECT  19.601 6.864 20.533 8.616 ;
     RECT  20.333 5.616 20.677 5.784 ;
     RECT  20.533 6.768 20.677 8.616 ;
     RECT  20.369 0.288 20.689 0.552 ;
     RECT  20.677 5.616 20.693 8.616 ;
     RECT  20.693 5.616 20.837 8.376 ;
     RECT  20.513 9.696 20.837 10.344 ;
     RECT  19.897 2.784 20.869 2.952 ;
     RECT  19.249 1.68 20.876 1.704 ;
     RECT  20.869 2.784 20.876 3.432 ;
     RECT  20.444 12.528 20.881 14.904 ;
     RECT  20.689 0.288 20.897 0.6 ;
     RECT  20.876 1.68 20.897 3.432 ;
     RECT  20.897 0.288 20.98 3.432 ;
     RECT  19.865 11.376 21.013 11.4 ;
     RECT  20.881 12.528 21.013 14.856 ;
     RECT  20.837 9.888 21.121 10.344 ;
     RECT  21.013 11.376 21.121 14.856 ;
     RECT  20.476 16.176 21.253 16.68 ;
     RECT  21.253 16.176 21.445 16.728 ;
     RECT  21.445 15.984 21.548 16.728 ;
     RECT  21.481 4.56 21.553 4.584 ;
     RECT  20.98 0.288 21.617 3.48 ;
     RECT  21.553 4.56 21.617 4.632 ;
     RECT  21.548 15.888 21.805 16.728 ;
     RECT  21.805 15.888 21.829 16.824 ;
     RECT  21.617 0.288 21.848 4.632 ;
     RECT  20.837 5.616 21.848 7.992 ;
     RECT  21.121 9.888 21.848 14.856 ;
     RECT  21.829 15.888 21.848 16.968 ;
     RECT  21.848 0.288 22.144 16.968 ;
     RECT  22.144 3.36 22.241 4.104 ;
     RECT  22.144 10.272 22.241 16.968 ;
     RECT  22.241 10.272 22.457 16.92 ;
     RECT  22.457 10.8 22.643 16.92 ;
     RECT  22.144 5.184 22.673 9.096 ;
     RECT  22.643 12.528 22.739 16.92 ;
     RECT  22.739 14.784 22.745 16.92 ;
     RECT  22.643 10.8 22.817 11.448 ;
     RECT  22.739 12.528 22.817 13.608 ;
     RECT  22.144 0.288 22.853 2.28 ;
     RECT  22.817 11.424 22.853 11.448 ;
     RECT  22.673 6.432 22.961 9.096 ;
     RECT  22.853 0.288 23.315 1.224 ;
     RECT  22.853 2.256 23.393 2.28 ;
     RECT  22.241 3.408 23.569 4.104 ;
     RECT  23.569 2.832 23.681 4.104 ;
     RECT  23.681 3.408 23.701 4.104 ;
     RECT  22.673 5.184 23.701 5.448 ;
     RECT  22.817 13.488 23.749 13.608 ;
     RECT  22.745 14.784 23.749 16.728 ;
     RECT  23.701 3.408 23.845 5.448 ;
     RECT  22.961 6.432 23.845 9.048 ;
     RECT  23.845 3.408 24.037 9.048 ;
     RECT  24.037 10.848 24.085 10.872 ;
     RECT  24.037 12.192 24.101 12.216 ;
     RECT  23.749 13.488 24.101 16.728 ;
     RECT  24.037 3.408 24.227 9.24 ;
     RECT  24.101 12.192 24.275 16.728 ;
     RECT  24.227 3.408 24.293 3.768 ;
     RECT  24.085 10.512 24.325 10.872 ;
     RECT  23.315 0.288 24.371 1.176 ;
     RECT  24.275 13.2 24.661 16.728 ;
     RECT  24.227 5.136 24.689 9.24 ;
     RECT  24.293 3.408 24.709 3.528 ;
     RECT  24.689 5.232 24.725 9.24 ;
     RECT  24.709 2.88 25.081 3.528 ;
     RECT  24.725 5.616 25.093 9.24 ;
     RECT  24.371 0.384 25.117 1.176 ;
     RECT  24.325 10.512 25.141 10.968 ;
     RECT  24.275 12.192 25.141 12.216 ;
     RECT  25.093 5.616 25.189 9.288 ;
     RECT  25.141 10.512 25.189 12.216 ;
     RECT  25.189 5.616 25.229 12.216 ;
     RECT  25.117 0.384 25.285 1.224 ;
     RECT  25.081 2.256 25.285 3.528 ;
     RECT  25.285 0.384 25.373 3.528 ;
     RECT  25.229 5.664 25.477 12.216 ;
     RECT  24.661 13.2 25.477 16.776 ;
     RECT  25.373 0.384 25.621 3.48 ;
     RECT  25.477 5.664 25.733 16.776 ;
     RECT  25.733 14.112 25.861 16.776 ;
     RECT  25.733 5.664 26.188 12.936 ;
     RECT  26.188 5.664 26.533 11.4 ;
     RECT  25.621 0.288 26.581 3.48 ;
     RECT  26.533 5.616 26.629 11.4 ;
     RECT  26.188 12.528 26.773 12.936 ;
     RECT  25.861 14.112 26.773 16.968 ;
     RECT  26.581 0.288 27.029 3.864 ;
     RECT  27.029 0.384 27.059 3.864 ;
     RECT  27.059 0.528 27.248 3.864 ;
     RECT  26.629 5.136 27.248 11.4 ;
     RECT  26.773 12.528 27.248 16.968 ;
     RECT  27.248 0.528 27.352 16.968 ;
     RECT  27.352 0.798 27.544 16.968 ;
     RECT  27.544 16.032 27.749 16.968 ;
     RECT  27.544 3.84 27.929 3.864 ;
     RECT  27.749 16.272 28.037 16.968 ;
     RECT  28.037 16.272 28.325 16.296 ;
    LAYER M5 ;
     RECT  2.4 0.053 2.424 0.144 ;
     RECT  2.304 0.144 27.048 0.227 ;
     RECT  2.496 0.227 27.048 0.517 ;
     RECT  0.24 0.517 0.36 0.787 ;
     RECT  2.496 0.517 27.36 0.787 ;
     RECT  2.496 0.787 27.552 2.915 ;
     RECT  5.472 2.915 27.552 3.203 ;
     RECT  2.496 2.915 4.44 3.299 ;
     RECT  5.472 3.203 11.448 3.385 ;
     RECT  2.496 3.299 3.288 3.395 ;
     RECT  12.48 3.203 27.552 3.443 ;
     RECT  12.576 3.443 27.552 3.819 ;
     RECT  4.272 3.299 4.44 3.925 ;
     RECT  5.472 3.385 11.352 3.925 ;
     RECT  2.496 3.395 2.856 4.019 ;
     RECT  12.816 3.819 27.552 4.019 ;
     RECT  4.272 3.925 11.352 4.341 ;
     RECT  3.936 4.341 11.352 4.587 ;
     RECT  4.272 4.587 11.352 5.077 ;
     RECT  12.864 4.019 27.552 5.077 ;
     RECT  4.272 5.077 27.552 5.171 ;
     RECT  18.144 5.171 27.552 5.267 ;
     RECT  2.784 4.019 2.856 5.747 ;
     RECT  18.336 5.267 27.552 5.747 ;
     RECT  19.824 5.747 27.552 5.795 ;
     RECT  18.336 5.747 18.792 5.843 ;
     RECT  4.272 5.171 16.968 6.239 ;
     RECT  4.272 6.239 17.64 6.323 ;
     RECT  18.768 5.843 18.792 6.837 ;
     RECT  18.528 6.837 18.792 6.925 ;
     RECT  4.272 6.323 7.32 6.995 ;
     RECT  20.352 5.795 27.552 6.995 ;
     RECT  19.2 7.045 19.224 7.189 ;
     RECT  2.832 5.747 2.856 7.237 ;
     RECT  4.272 6.995 7.272 7.237 ;
     RECT  2.832 7.237 7.272 7.391 ;
     RECT  8.544 6.323 16.968 7.391 ;
     RECT  19.2 7.189 19.368 7.413 ;
     RECT  2.016 7.391 7.272 7.475 ;
     RECT  8.544 7.391 17.64 7.475 ;
     RECT  20.736 6.995 27.552 7.475 ;
     RECT  19.2 7.413 19.464 7.957 ;
     RECT  2.784 7.475 7.272 7.967 ;
     RECT  19.2 7.957 19.704 7.967 ;
     RECT  2.784 7.967 7.32 8.051 ;
     RECT  18.192 7.967 19.704 8.051 ;
     RECT  2.832 8.051 7.32 8.341 ;
     RECT  8.544 7.475 16.968 8.341 ;
     RECT  19.632 8.051 19.704 8.341 ;
     RECT  2.832 8.341 16.968 8.427 ;
     RECT  14.16 8.427 16.968 8.437 ;
     RECT  14.16 8.437 17.208 8.543 ;
     RECT  19.632 8.341 20.136 8.543 ;
     RECT  21.312 7.475 27.552 8.543 ;
     RECT  14.16 8.543 17.64 8.627 ;
     RECT  19.632 8.543 27.552 8.627 ;
     RECT  2.832 8.427 12.984 9.203 ;
     RECT  4.416 9.203 12.984 9.397 ;
     RECT  14.16 8.627 17.208 9.397 ;
     RECT  19.68 8.627 20.136 9.589 ;
     RECT  21.312 8.627 27.552 9.589 ;
     RECT  18.672 9.119 18.696 9.637 ;
     RECT  19.68 9.589 27.552 9.637 ;
     RECT  4.416 9.397 17.208 9.695 ;
     RECT  18.672 9.637 27.552 9.695 ;
     RECT  4.416 9.695 27.552 9.731 ;
     RECT  3.264 9.203 3.432 9.779 ;
     RECT  8.064 9.731 27.552 9.779 ;
     RECT  4.416 9.731 7.08 10.213 ;
     RECT  3.264 9.779 3.288 10.271 ;
     RECT  8.064 9.779 13.464 10.799 ;
     RECT  14.544 9.779 27.552 10.799 ;
     RECT  2.832 10.271 3.288 10.805 ;
     RECT  4.368 10.213 7.08 10.805 ;
     RECT  8.064 10.799 27.552 10.805 ;
     RECT  2.736 10.805 3.288 10.893 ;
     RECT  4.368 10.805 27.552 10.893 ;
     RECT  3.264 10.893 3.288 10.933 ;
     RECT  4.368 10.893 7.08 10.933 ;
     RECT  3.264 10.933 7.08 10.979 ;
     RECT  3.264 10.979 7.032 11.017 ;
     RECT  8.064 10.893 27.552 11.027 ;
     RECT  4.32 11.017 7.032 11.075 ;
     RECT  3.264 11.017 3.336 11.459 ;
     RECT  4.368 11.075 7.032 11.989 ;
     RECT  3.264 11.459 3.288 12.143 ;
     RECT  4.368 11.989 7.176 12.143 ;
     RECT  8.16 11.027 27.552 12.143 ;
     RECT  2.592 12.143 3.288 12.709 ;
     RECT  2.496 12.709 3.288 12.793 ;
     RECT  3.168 12.793 3.288 13.103 ;
     RECT  4.368 12.143 27.552 13.103 ;
     RECT  3.168 13.103 27.552 14.197 ;
     RECT  2.304 14.197 27.552 14.867 ;
     RECT  2.688 14.867 27.552 15.983 ;
     RECT  1.824 15.983 27.552 16.067 ;
     RECT  0.24 0.787 0.552 16.223 ;
     RECT  0.432 16.223 0.552 16.493 ;
     RECT  2.304 16.067 27.552 16.493 ;
     RECT  2.304 16.493 27.048 17.104 ;
    LAYER M6 ;
     RECT  1.813 16 1.845 16.032 ;
     RECT  1.845 14.784 1.899 16.032 ;
     RECT  0 6.396 2.005 7.26 ;
     RECT  0 0.996 2.037 1.86 ;
     RECT  2.037 0.256 2.389 1.86 ;
     RECT  1.899 14.784 2.435 14.816 ;
     RECT  0 11.796 2.485 12.66 ;
     RECT  2.658 3.392 2.677 3.424 ;
     RECT  2.485 11.796 2.725 12.768 ;
     RECT  2.677 3.392 2.731 4.384 ;
     RECT  2.005 6.396 2.773 7.456 ;
     RECT  2.773 6.396 2.821 8.032 ;
     RECT  2.725 10.816 2.821 12.768 ;
     RECT  2.821 6.396 2.923 12.768 ;
     RECT  2.389 0.064 3.115 1.86 ;
     RECT  2.923 8.576 3.541 12.768 ;
     RECT  3.445 14.208 3.541 14.24 ;
     RECT  3.541 8.576 3.627 14.24 ;
     RECT  3.627 14.208 3.877 14.24 ;
     RECT  2.731 4.352 3.925 4.384 ;
     RECT  3.925 4.352 3.971 4.576 ;
     RECT  3.115 0.128 4.011 1.86 ;
     RECT  2.923 6.396 4.213 7.26 ;
     RECT  3.627 8.576 4.213 12.66 ;
     RECT  3.877 14.208 4.405 14.304 ;
     RECT  4.213 6.396 4.523 12.66 ;
     RECT  3.971 4.544 4.971 4.576 ;
     RECT  4.405 14.208 5.045 14.88 ;
     RECT  4.523 11.796 5.221 12.66 ;
     RECT  5.045 14.208 5.221 14.944 ;
     RECT  5.221 11.796 5.269 14.944 ;
     RECT  5.269 11.796 5.291 15.008 ;
     RECT  4.011 0.192 5.365 1.86 ;
     RECT  4.523 6.396 5.941 10.336 ;
     RECT  5.291 11.796 5.941 12.66 ;
     RECT  5.291 14.272 6.005 15.008 ;
     RECT  5.941 6.396 6.083 12.66 ;
     RECT  6.005 14.272 6.083 16.032 ;
     RECT  6.083 14.272 6.227 14.944 ;
     RECT  5.365 0.064 6.571 1.86 ;
     RECT  6.083 9.728 6.699 12.66 ;
     RECT  6.757 4.544 6.805 4.576 ;
     RECT  6.083 6.396 6.805 8.032 ;
     RECT  6.805 4.544 7.381 8.032 ;
     RECT  7.381 4.544 7.541 9.184 ;
     RECT  6.699 10.816 7.573 12.66 ;
     RECT  7.541 3.456 7.93 9.184 ;
     RECT  6.227 14.848 8.003 14.944 ;
     RECT  7.93 5.184 8.051 9.184 ;
     RECT  6.571 0.128 8.235 1.86 ;
     RECT  8.051 5.696 8.293 9.184 ;
     RECT  7.573 10.816 8.293 12.768 ;
     RECT  8.293 5.696 8.437 12.768 ;
     RECT  8.003 14.848 8.939 14.88 ;
     RECT  8.437 5.696 9.082 13.152 ;
     RECT  9.082 5.696 9.589 12.768 ;
     RECT  9.589 5.12 9.731 12.768 ;
     RECT  8.235 0.256 10.229 1.86 ;
     RECT  10.229 0.128 10.421 1.86 ;
     RECT  9.731 5.696 10.923 12.768 ;
     RECT  10.923 6.144 10.933 12.768 ;
     RECT  10.597 14.272 10.933 14.304 ;
     RECT  10.933 6.144 10.997 14.304 ;
     RECT  10.421 0.064 11.253 1.86 ;
     RECT  11.253 0.064 11.459 2.016 ;
     RECT  7.957 3.328 11.459 3.36 ;
     RECT  10.997 6.144 11.459 14.944 ;
     RECT  11.459 6.272 11.507 13.728 ;
     RECT  11.507 6.272 11.891 10.336 ;
     RECT  11.459 0.064 11.947 1.86 ;
     RECT  11.891 6.272 12.782 7.776 ;
     RECT  12.469 3.776 12.917 3.808 ;
     RECT  12.782 5.12 12.917 7.776 ;
     RECT  11.507 11.796 12.995 13.728 ;
     RECT  11.891 9.152 13.035 10.336 ;
     RECT  13.035 10.304 13.045 10.336 ;
     RECT  12.995 11.796 13.045 12.768 ;
     RECT  12.917 3.776 13.139 7.776 ;
     RECT  13.139 5.568 13.173 7.776 ;
     RECT  11.947 0.256 13.301 1.86 ;
     RECT  13.045 10.304 13.498 12.768 ;
     RECT  13.173 5.568 13.715 8.416 ;
     RECT  13.139 3.776 13.763 3.808 ;
     RECT  13.301 0.128 13.867 1.86 ;
     RECT  13.715 5.568 14.074 8.032 ;
     RECT  13.498 10.816 14.291 12.768 ;
     RECT  13.867 0.192 14.675 1.86 ;
     RECT  13.141 14.272 14.699 14.304 ;
     RECT  14.291 10.816 14.842 12.66 ;
     RECT  14.074 6.144 14.867 8.032 ;
     RECT  14.867 6.396 15.347 8.032 ;
     RECT  15.347 6.396 15.443 7.776 ;
     RECT  14.773 14.528 15.443 14.56 ;
     RECT  14.842 11.796 15.733 12.66 ;
     RECT  14.675 0.256 15.877 1.86 ;
     RECT  15.443 6.396 16.245 7.648 ;
     RECT  15.877 0.256 16.309 3.04 ;
     RECT  15.349 10.304 16.309 10.336 ;
     RECT  15.733 11.796 16.309 13.152 ;
     RECT  16.245 5.632 16.373 7.648 ;
     RECT  16.373 5.504 16.501 7.648 ;
     RECT  16.309 0.256 16.555 3.424 ;
     RECT  16.501 5.376 16.814 7.648 ;
     RECT  16.309 9.728 16.814 13.152 ;
     RECT  16.814 5.376 16.837 13.152 ;
     RECT  16.837 5.376 17.582 13.728 ;
     RECT  16.555 0.256 18.275 3.04 ;
     RECT  17.582 5.376 18.987 14.304 ;
     RECT  18.987 5.376 19.243 13.344 ;
     RECT  19.243 6.144 19.499 13.344 ;
     RECT  19.499 8.576 19.763 13.344 ;
     RECT  19.763 8.576 20.459 10.336 ;
     RECT  20.459 8.576 20.579 8.608 ;
     RECT  20.459 10.304 20.651 10.336 ;
     RECT  20.149 14.848 20.907 14.88 ;
     RECT  18.275 0.256 20.917 1.86 ;
     RECT  19.763 11.796 21.061 13.344 ;
     RECT  19.499 6.144 21.23 7.26 ;
     RECT  21.23 5.632 21.299 7.26 ;
     RECT  21.061 10.368 21.685 13.344 ;
     RECT  21.685 10.368 21.803 14.304 ;
     RECT  21.877 16.576 22.163 16.608 ;
     RECT  21.803 11.328 22.259 14.304 ;
     RECT  22.259 11.796 22.309 14.304 ;
     RECT  22.309 11.796 22.379 14.88 ;
     RECT  21.299 6.144 22.693 7.26 ;
     RECT  22.693 6.144 22.741 8.032 ;
     RECT  22.741 6.144 23.093 8.224 ;
     RECT  22.379 11.796 23.795 14.304 ;
     RECT  20.917 0.256 23.851 2.208 ;
     RECT  23.778 4.8 23.851 4.832 ;
     RECT  23.795 11.796 23.939 14.24 ;
     RECT  23.093 6.144 24.181 8.608 ;
     RECT  23.845 16 24.363 16.032 ;
     RECT  23.939 11.796 24.421 13.728 ;
     RECT  24.421 10.816 24.491 13.728 ;
     RECT  24.181 5.696 25.139 8.608 ;
     RECT  24.491 11.796 25.139 13.728 ;
     RECT  25.139 5.696 25.643 7.968 ;
     RECT  25.237 14.848 25.643 14.88 ;
     RECT  25.139 11.796 25.973 12.768 ;
     RECT  25.973 11.392 26.101 12.768 ;
     RECT  26.101 10.304 26.291 12.768 ;
     RECT  25.643 5.696 26.533 7.26 ;
     RECT  26.291 11.328 26.549 12.768 ;
     RECT  26.533 5.632 26.603 7.26 ;
     RECT  26.606 9.728 26.675 9.76 ;
     RECT  26.725 9.152 26.795 9.184 ;
     RECT  26.549 11.328 26.819 13.728 ;
     RECT  23.851 0.256 27.059 1.86 ;
     RECT  27.059 0.996 27.36 1.86 ;
     RECT  26.603 6.396 27.36 7.26 ;
     RECT  26.819 11.796 27.36 12.66 ;
     RECT  27.36 1.572 28.144 1.86 ;
     RECT  27.36 6.972 28.144 7.26 ;
     RECT  27.36 12.372 28.144 12.66 ;
    LAYER M7 ;
     RECT  3.072 0.053 3.104 0.117 ;
     RECT  5.376 0.053 6.56 0.117 ;
     RECT  10.432 0.053 10.464 0.117 ;
     RECT  11.904 0.053 11.936 0.117 ;
     RECT  3.072 0.117 4 0.181 ;
     RECT  5.376 0.117 8.224 0.181 ;
     RECT  13.312 0.117 13.856 0.181 ;
     RECT  3.072 0.181 8.224 0.245 ;
     RECT  10.24 0.117 11.936 0.245 ;
     RECT  13.312 0.181 14.368 0.245 ;
     RECT  2.048 0.245 26.784 0.531 ;
     RECT  0.856 0.531 28.144 7.467 ;
     RECT  2.496 7.467 28.144 11.435 ;
     RECT  2.496 11.435 9.056 12.779 ;
     RECT  10.368 11.435 28.144 12.779 ;
     RECT  3.584 12.779 9.056 13.163 ;
     RECT  10.624 12.779 28.144 13.163 ;
     RECT  16.896 13.163 28.144 13.355 ;
     RECT  16.896 13.355 17.632 13.739 ;
     RECT  18.944 13.355 28.144 13.739 ;
     RECT  3.904 13.163 8.928 14.315 ;
     RECT  10.624 13.163 14.688 14.315 ;
     RECT  17.056 13.739 17.632 14.315 ;
     RECT  18.944 13.739 25.632 14.315 ;
     RECT  0.856 7.467 1.144 14.773 ;
     RECT  4.416 14.315 8.928 14.891 ;
     RECT  20.16 14.315 20.896 14.891 ;
     RECT  22.336 14.315 25.632 14.891 ;
     RECT  5.056 14.891 6.544 14.955 ;
     RECT  11.008 14.315 11.944 14.955 ;
     RECT  5.632 14.955 6.544 15.019 ;
     RECT  0.856 14.773 1.888 16.043 ;
     RECT  6.016 15.019 6.544 16.043 ;
     RECT  22.456 14.891 24.352 16.043 ;
     RECT  0.856 16.043 1.144 16.479 ;
     RECT  6.256 16.043 6.544 16.479 ;
     RECT  11.656 14.955 11.944 16.479 ;
     RECT  17.056 14.315 17.344 16.479 ;
     RECT  22.456 16.043 22.744 16.479 ;
     RECT  27.856 13.739 28.144 16.479 ;
  END
END dsfd_stnv_512x1
END LIBRARY
